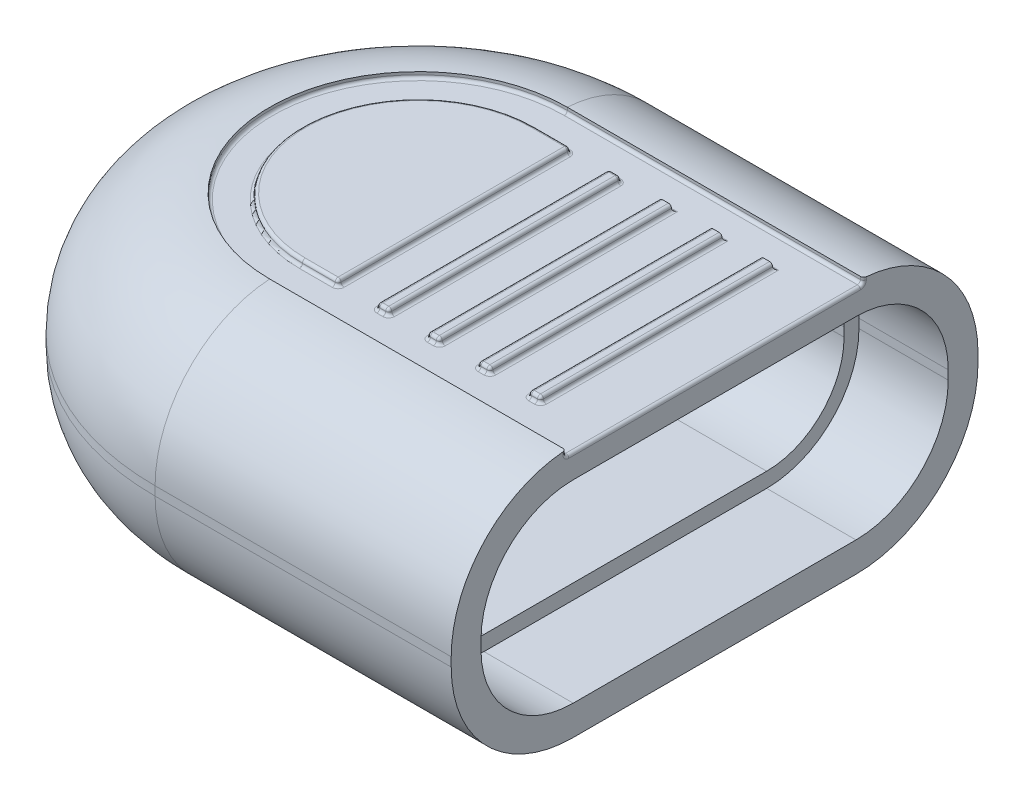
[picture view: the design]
ISO-10303-21;
HEADER;
FILE_DESCRIPTION(('STEP AP214'),'2;1');
FILE_NAME('part.step','',(''),(''),'','','');
FILE_SCHEMA(('AUTOMOTIVE_DESIGN { 1 0 10303 214 1 1 1 1 }'));
ENDSEC;
DATA;
#1=APPLICATION_CONTEXT('core data for automotive mechanical design processes');
#2=APPLICATION_PROTOCOL_DEFINITION('international standard','automotive_design',2000,#1);
#3=PRODUCT_CONTEXT('',#1,'mechanical');
#4=PRODUCT('Part','Part','',(#3));
#5=PRODUCT_RELATED_PRODUCT_CATEGORY('part','',(#4));
#6=PRODUCT_DEFINITION_FORMATION('','',#4);
#7=PRODUCT_DEFINITION_CONTEXT('part definition',#1,'design');
#8=PRODUCT_DEFINITION('design','',#6,#7);
#9=PRODUCT_DEFINITION_SHAPE('','',#8);
#10=(LENGTH_UNIT() NAMED_UNIT(*) SI_UNIT(.MILLI.,.METRE.));
#11=(NAMED_UNIT(*) PLANE_ANGLE_UNIT() SI_UNIT($,.RADIAN.));
#12=(NAMED_UNIT(*) SI_UNIT($,.STERADIAN.) SOLID_ANGLE_UNIT());
#13=UNCERTAINTY_MEASURE_WITH_UNIT(LENGTH_MEASURE(1.E-05),#10,'distance_accuracy_value','');
#14=(GEOMETRIC_REPRESENTATION_CONTEXT(3) GLOBAL_UNCERTAINTY_ASSIGNED_CONTEXT((#13)) GLOBAL_UNIT_ASSIGNED_CONTEXT((#10,
#11,#12)) REPRESENTATION_CONTEXT('',''));
#15=CARTESIAN_POINT('',(0.,0.,0.));
#16=DIRECTION('',(0.,0.,1.));
#17=DIRECTION('',(1.,0.,0.));
#18=AXIS2_PLACEMENT_3D('',#15,#16,#17);
#19=CARTESIAN_POINT('',(0.,4.25,0.));
#20=DIRECTION('',(0.,-1.,0.));
#21=DIRECTION('',(0.,0.,-1.));
#22=AXIS2_PLACEMENT_3D('',#19,#20,#21);
#23=CYLINDRICAL_SURFACE('',#22,7.35);
#24=DIRECTION('',(0.,-1.,0.));
#25=VECTOR('',#24,1.);
#26=CARTESIAN_POINT('',(-3.86781592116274,4.25,-6.25));
#27=LINE('',#26,#25);
#28=CARTESIAN_POINT('',(-3.86781592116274,-0.150000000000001,-6.25));
#29=VERTEX_POINT('',#28);
#30=CARTESIAN_POINT('',(-3.86781592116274,0.150000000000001,-6.25));
#31=VERTEX_POINT('',#30);
#32=EDGE_CURVE('E736',#29,#31,#27,.F.);
#33=ORIENTED_EDGE('',*,*,#32,.T.);
#34=CARTESIAN_POINT('',(0.,0.150000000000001,0.));
#35=DIRECTION('',(0.,-1.,0.));
#36=DIRECTION('',(0.,0.,-1.));
#37=AXIS2_PLACEMENT_3D('',#34,#35,#36);
#38=CIRCLE('',#37,7.35);
#39=CARTESIAN_POINT('',(-3.86781592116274,0.150000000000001,6.25));
#40=VERTEX_POINT('',#39);
#41=EDGE_CURVE('E931',#40,#31,#38,.T.);
#42=ORIENTED_EDGE('',*,*,#41,.F.);
#43=DIRECTION('',(0.,-1.,0.));
#44=VECTOR('',#43,1.);
#45=CARTESIAN_POINT('',(-3.86781592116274,4.25,6.25));
#46=LINE('',#45,#44);
#47=CARTESIAN_POINT('',(-3.86781592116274,-0.150000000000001,6.25));
#48=VERTEX_POINT('',#47);
#49=EDGE_CURVE('E756',#48,#40,#46,.F.);
#50=ORIENTED_EDGE('',*,*,#49,.F.);
#51=CARTESIAN_POINT('',(0.,-0.150000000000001,0.));
#52=DIRECTION('',(0.,-1.,0.));
#53=DIRECTION('',(0.,0.,-1.));
#54=AXIS2_PLACEMENT_3D('',#51,#52,#53);
#55=CIRCLE('',#54,7.35);
#56=EDGE_CURVE('E926',#29,#48,#55,.F.);
#57=ORIENTED_EDGE('',*,*,#56,.F.);
#58=EDGE_LOOP('',(#33,#42,#50,#57));
#59=FACE_BOUND('',#58,.T.);
#60=ADVANCED_FACE('F44',(#59),#23,.F.);
#61=CARTESIAN_POINT('',(9.95000000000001,4.25,-8.85));
#62=DIRECTION('',(1.,0.,0.));
#63=DIRECTION('',(0.,0.,-1.));
#64=AXIS2_PLACEMENT_3D('',#61,#62,#63);
#65=PLANE('',#64);
#66=CARTESIAN_POINT('',(9.95000000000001,0.150000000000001,-4.75));
#67=DIRECTION('',(1.,0.,0.));
#68=DIRECTION('',(0.,0.,-1.));
#69=AXIS2_PLACEMENT_3D('',#66,#67,#68);
#70=CIRCLE('',#69,4.1);
#71=CARTESIAN_POINT('',(9.95000000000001,0.150000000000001,-8.85));
#72=VERTEX_POINT('',#71);
#73=CARTESIAN_POINT('',(9.95000000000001,4.23503365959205,-5.1));
#74=VERTEX_POINT('',#73);
#75=EDGE_CURVE('E1022',#72,#74,#70,.T.);
#76=ORIENTED_EDGE('',*,*,#75,.T.);
#77=DIRECTION('',(0.,1.,0.));
#78=VECTOR('',#77,1.);
#79=CARTESIAN_POINT('',(9.95000000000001,4.25,-5.1));
#80=LINE('',#79,#78);
#81=CARTESIAN_POINT('',(9.95000000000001,4.15,-5.1));
#82=VERTEX_POINT('',#81);
#83=EDGE_CURVE('E1143',#74,#82,#80,.F.);
#84=ORIENTED_EDGE('',*,*,#83,.T.);
#85=CARTESIAN_POINT('',(9.95000000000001,4.15,-4.9));
#86=DIRECTION('',(1.,0.,0.));
#87=DIRECTION('',(0.,0.,-1.));
#88=AXIS2_PLACEMENT_3D('',#85,#86,#87);
#89=CIRCLE('',#88,0.2);
#90=CARTESIAN_POINT('',(9.95000000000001,3.95,-4.9));
#91=VERTEX_POINT('',#90);
#92=EDGE_CURVE('E1904',#91,#82,#89,.T.);
#93=ORIENTED_EDGE('',*,*,#92,.F.);
#94=DIRECTION('',(0.,0.,-1.));
#95=VECTOR('',#94,1.);
#96=CARTESIAN_POINT('',(9.95000000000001,3.95,-8.85));
#97=LINE('',#96,#95);
#98=CARTESIAN_POINT('',(9.95000000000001,3.95,4.9));
#99=VERTEX_POINT('',#98);
#100=EDGE_CURVE('E1908',#91,#99,#97,.F.);
#101=ORIENTED_EDGE('',*,*,#100,.T.);
#102=CARTESIAN_POINT('',(9.95000000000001,4.15,4.9));
#103=DIRECTION('',(1.,0.,0.));
#104=DIRECTION('',(0.,0.,-1.));
#105=AXIS2_PLACEMENT_3D('',#102,#103,#104);
#106=CIRCLE('',#105,0.2);
#107=CARTESIAN_POINT('',(9.95000000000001,4.15,5.1));
#108=VERTEX_POINT('',#107);
#109=EDGE_CURVE('E1086',#108,#99,#106,.T.);
#110=ORIENTED_EDGE('',*,*,#109,.F.);
#111=DIRECTION('',(0.,1.,0.));
#112=VECTOR('',#111,1.);
#113=CARTESIAN_POINT('',(9.95000000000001,4.24237095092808,5.1));
#114=LINE('',#113,#112);
#115=CARTESIAN_POINT('',(9.95000000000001,4.23503365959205,5.1));
#116=VERTEX_POINT('',#115);
#117=EDGE_CURVE('E1906',#108,#116,#114,.T.);
#118=ORIENTED_EDGE('',*,*,#117,.T.);
#119=CARTESIAN_POINT('',(9.95000000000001,0.150000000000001,4.75));
#120=DIRECTION('',(1.,0.,0.));
#121=DIRECTION('',(0.,0.,-1.));
#122=AXIS2_PLACEMENT_3D('',#119,#120,#121);
#123=CIRCLE('',#122,4.1);
#124=CARTESIAN_POINT('',(9.95000000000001,0.150000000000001,8.85));
#125=VERTEX_POINT('',#124);
#126=EDGE_CURVE('E1019',#116,#125,#123,.T.);
#127=ORIENTED_EDGE('',*,*,#126,.T.);
#128=DIRECTION('',(0.,-1.,0.));
#129=VECTOR('',#128,1.);
#130=CARTESIAN_POINT('',(9.95000000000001,4.25,8.85));
#131=LINE('',#130,#129);
#132=CARTESIAN_POINT('',(9.95000000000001,-0.150000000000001,8.85));
#133=VERTEX_POINT('',#132);
#134=EDGE_CURVE('E998',#125,#133,#131,.T.);
#135=ORIENTED_EDGE('',*,*,#134,.T.);
#136=CARTESIAN_POINT('',(9.95000000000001,-0.150000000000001,4.75));
#137=DIRECTION('',(1.,0.,0.));
#138=DIRECTION('',(0.,0.,-1.));
#139=AXIS2_PLACEMENT_3D('',#136,#137,#138);
#140=CIRCLE('',#139,4.1);
#141=CARTESIAN_POINT('',(9.95000000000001,-4.25,4.75));
#142=VERTEX_POINT('',#141);
#143=EDGE_CURVE('E1016',#133,#142,#140,.T.);
#144=ORIENTED_EDGE('',*,*,#143,.T.);
#145=DIRECTION('',(0.,0.,1.));
#146=VECTOR('',#145,1.);
#147=CARTESIAN_POINT('',(9.95000000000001,-4.25,-8.85));
#148=LINE('',#147,#146);
#149=CARTESIAN_POINT('',(9.95000000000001,-4.25,-4.75));
#150=VERTEX_POINT('',#149);
#151=EDGE_CURVE('E985',#150,#142,#148,.T.);
#152=ORIENTED_EDGE('',*,*,#151,.F.);
#153=CARTESIAN_POINT('',(9.95000000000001,-0.150000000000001,-4.75));
#154=DIRECTION('',(1.,0.,0.));
#155=DIRECTION('',(0.,0.,-1.));
#156=AXIS2_PLACEMENT_3D('',#153,#154,#155);
#157=CIRCLE('',#156,4.1);
#158=CARTESIAN_POINT('',(9.95000000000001,-0.150000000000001,-8.85));
#159=VERTEX_POINT('',#158);
#160=EDGE_CURVE('E1026',#150,#159,#157,.T.);
#161=ORIENTED_EDGE('',*,*,#160,.T.);
#162=DIRECTION('',(0.,-1.,0.));
#163=VECTOR('',#162,1.);
#164=CARTESIAN_POINT('',(9.95000000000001,4.25,-8.85));
#165=LINE('',#164,#163);
#166=EDGE_CURVE('E994',#72,#159,#165,.T.);
#167=ORIENTED_EDGE('',*,*,#166,.F.);
#168=EDGE_LOOP('',(#76,#84,#93,#101,#110,#118,#127,#135,#144,#152,#161,#167));
#169=FACE_BOUND('',#168,.T.);
#170=CARTESIAN_POINT('',(9.95000000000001,0.150000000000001,-4.75));
#171=DIRECTION('',(1.,0.,0.));
#172=DIRECTION('',(0.,0.,-1.));
#173=AXIS2_PLACEMENT_3D('',#170,#171,#172);
#174=CIRCLE('',#173,3.1);
#175=CARTESIAN_POINT('',(9.95000000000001,0.150000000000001,-7.85));
#176=VERTEX_POINT('',#175);
#177=CARTESIAN_POINT('',(9.95000000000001,3.25,-4.75));
#178=VERTEX_POINT('',#177);
#179=EDGE_CURVE('E822',#176,#178,#174,.T.);
#180=ORIENTED_EDGE('',*,*,#179,.F.);
#181=DIRECTION('',(0.,-1.,0.));
#182=VECTOR('',#181,1.);
#183=CARTESIAN_POINT('',(9.95000000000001,0.,-7.85));
#184=LINE('',#183,#182);
#185=CARTESIAN_POINT('',(9.95000000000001,-0.150000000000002,-7.85));
#186=VERTEX_POINT('',#185);
#187=EDGE_CURVE('E759',#176,#186,#184,.T.);
#188=ORIENTED_EDGE('',*,*,#187,.T.);
#189=CARTESIAN_POINT('',(9.95000000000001,-0.150000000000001,-4.75));
#190=DIRECTION('',(1.,0.,0.));
#191=DIRECTION('',(0.,0.,-1.));
#192=AXIS2_PLACEMENT_3D('',#189,#190,#191);
#193=CIRCLE('',#192,3.1);
#194=CARTESIAN_POINT('',(9.95000000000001,-3.25,-4.75));
#195=VERTEX_POINT('',#194);
#196=EDGE_CURVE('E791',#195,#186,#193,.T.);
#197=ORIENTED_EDGE('',*,*,#196,.F.);
#198=DIRECTION('',(0.,0.,1.));
#199=VECTOR('',#198,1.);
#200=CARTESIAN_POINT('',(9.95000000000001,-3.25,0.));
#201=LINE('',#200,#199);
#202=CARTESIAN_POINT('',(9.95000000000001,-3.25,4.75));
#203=VERTEX_POINT('',#202);
#204=EDGE_CURVE('E842',#195,#203,#201,.T.);
#205=ORIENTED_EDGE('',*,*,#204,.T.);
#206=CARTESIAN_POINT('',(9.95000000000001,-0.150000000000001,4.75));
#207=DIRECTION('',(1.,0.,0.));
#208=DIRECTION('',(0.,0.,-1.));
#209=AXIS2_PLACEMENT_3D('',#206,#207,#208);
#210=CIRCLE('',#209,3.1);
#211=CARTESIAN_POINT('',(9.95000000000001,-0.150000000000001,7.85));
#212=VERTEX_POINT('',#211);
#213=EDGE_CURVE('E838',#212,#203,#210,.T.);
#214=ORIENTED_EDGE('',*,*,#213,.F.);
#215=DIRECTION('',(0.,-1.,0.));
#216=VECTOR('',#215,1.);
#217=CARTESIAN_POINT('',(9.95000000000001,0.,7.85));
#218=LINE('',#217,#216);
#219=CARTESIAN_POINT('',(9.95000000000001,0.150000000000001,7.85));
#220=VERTEX_POINT('',#219);
#221=EDGE_CURVE('E834',#220,#212,#218,.T.);
#222=ORIENTED_EDGE('',*,*,#221,.F.);
#223=CARTESIAN_POINT('',(9.95000000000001,0.150000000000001,4.75));
#224=DIRECTION('',(1.,0.,0.));
#225=DIRECTION('',(0.,0.,-1.));
#226=AXIS2_PLACEMENT_3D('',#223,#224,#225);
#227=CIRCLE('',#226,3.1);
#228=CARTESIAN_POINT('',(9.95000000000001,3.25,4.75));
#229=VERTEX_POINT('',#228);
#230=EDGE_CURVE('E830',#229,#220,#227,.T.);
#231=ORIENTED_EDGE('',*,*,#230,.F.);
#232=DIRECTION('',(0.,0.,1.));
#233=VECTOR('',#232,1.);
#234=CARTESIAN_POINT('',(9.95000000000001,3.25,0.));
#235=LINE('',#234,#233);
#236=EDGE_CURVE('E826',#178,#229,#235,.T.);
#237=ORIENTED_EDGE('',*,*,#236,.F.);
#238=EDGE_LOOP('',(#180,#188,#197,#205,#214,#222,#231,#237));
#239=FACE_BOUND('',#238,.T.);
#240=ADVANCED_FACE('F1793',(#169,#239),#65,.T.);
#241=CARTESIAN_POINT('',(0.,0.150000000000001,-4.75));
#242=DIRECTION('',(1.,0.,0.));
#243=DIRECTION('',(0.,0.,-1.));
#244=AXIS2_PLACEMENT_3D('',#241,#242,#243);
#245=CYLINDRICAL_SURFACE('',#244,4.1);
#246=DIRECTION('',(1.,0.,0.));
#247=VECTOR('',#246,1.);
#248=CARTESIAN_POINT('',(0.,4.24237095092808,-5.));
#249=LINE('',#248,#247);
#250=CARTESIAN_POINT('',(0.,4.24237095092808,-5.));
#251=VERTEX_POINT('',#250);
#252=CARTESIAN_POINT('',(9.85000000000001,4.24237095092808,-5.));
#253=VERTEX_POINT('',#252);
#254=EDGE_CURVE('E1048',#251,#253,#249,.T.);
#255=ORIENTED_EDGE('',*,*,#254,.T.);
#256=CARTESIAN_POINT('',(9.85000000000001,4.24237095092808,-5.));
#257=CARTESIAN_POINT('',(9.85561729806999,4.24237091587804,-4.99999518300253));
#258=CARTESIAN_POINT('',(9.8612331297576,4.24234204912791,-5.00047302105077));
#259=CARTESIAN_POINT('',(9.87230133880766,4.24222639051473,-5.00235842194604));
#260=CARTESIAN_POINT('',(9.87775384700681,4.2421396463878,-5.00376521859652));
#261=CARTESIAN_POINT('',(9.88834713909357,4.24190791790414,-5.00747392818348));
#262=CARTESIAN_POINT('',(9.89348777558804,4.24176290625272,-5.0097762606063));
#263=CARTESIAN_POINT('',(9.90330831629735,4.24141444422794,-5.01520797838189));
#264=CARTESIAN_POINT('',(9.90798829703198,4.24121100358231,-5.01833722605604));
#265=CARTESIAN_POINT('',(9.91675889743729,4.24074595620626,-5.02533575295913));
#266=CARTESIAN_POINT('',(9.9208491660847,4.24048431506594,-5.02920546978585));
#267=CARTESIAN_POINT('',(9.92832272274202,4.23990450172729,-5.0375738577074));
#268=CARTESIAN_POINT('',(9.93170587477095,4.23958631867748,-5.04207264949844));
#269=CARTESIAN_POINT('',(9.93767549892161,4.2388962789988,-5.05157909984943));
#270=CARTESIAN_POINT('',(9.9402603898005,4.23852431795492,-5.05658774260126));
#271=CARTESIAN_POINT('',(9.94455186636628,4.23773301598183,-5.06696338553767));
#272=CARTESIAN_POINT('',(9.94625891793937,4.23731370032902,-5.07233019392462));
#273=CARTESIAN_POINT('',(9.9483337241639,4.23658301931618,-5.08144020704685));
#274=CARTESIAN_POINT('',(9.94895828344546,4.23628229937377,-5.08512786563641));
#275=CARTESIAN_POINT('',(9.94979137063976,4.23566739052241,-5.09254334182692));
#276=CARTESIAN_POINT('',(9.95000049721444,4.23535322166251,-5.09627109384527));
#277=CARTESIAN_POINT('',(9.95000000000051,4.23503365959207,-5.09999999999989));
#278=B_SPLINE_CURVE_WITH_KNOTS('',3,(#256,#257,#258,#259,#260,#261,#262,#263,#264,#265,#266,
#267,#268,#269,#270,#271,#272,#273,#274,#275,#276,#277),.UNSPECIFIED.,.F.,.F.,(4,2,2,2,2,2,2,2,
2,2,4),(0.,0.0168294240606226,0.033644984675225,0.0504684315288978,0.0672890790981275,
0.0841196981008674,0.100953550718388,0.117820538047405,0.134678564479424,0.145913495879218,
0.157132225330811),.UNSPECIFIED.);
#279=EDGE_CURVE('E1077',#253,#74,#278,.T.);
#280=ORIENTED_EDGE('',*,*,#279,.T.);
#281=ORIENTED_EDGE('',*,*,#75,.F.);
#282=DIRECTION('',(1.,0.,0.));
#283=VECTOR('',#282,1.);
#284=CARTESIAN_POINT('',(0.,0.150000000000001,-8.85));
#285=LINE('',#284,#283);
#286=CARTESIAN_POINT('',(0.,0.150000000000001,-8.85));
#287=VERTEX_POINT('',#286);
#288=EDGE_CURVE('E1029',#287,#72,#285,.T.);
#289=ORIENTED_EDGE('',*,*,#288,.F.);
#290=CARTESIAN_POINT('',(0.,0.150000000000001,-4.75));
#291=DIRECTION('',(1.,0.,0.));
#292=DIRECTION('',(0.,0.,-1.));
#293=AXIS2_PLACEMENT_3D('',#290,#291,#292);
#294=CIRCLE('',#293,4.1);
#295=EDGE_CURVE('E936',#287,#251,#294,.T.);
#296=ORIENTED_EDGE('',*,*,#295,.T.);
#297=EDGE_LOOP('',(#255,#280,#281,#289,#296));
#298=FACE_BOUND('',#297,.T.);
#299=ADVANCED_FACE('F1088',(#298),#245,.T.);
#300=CARTESIAN_POINT('',(0.,4.25,0.));
#301=DIRECTION('',(0.,-1.,0.));
#302=DIRECTION('',(0.,0.,-1.));
#303=AXIS2_PLACEMENT_3D('',#300,#301,#302);
#304=CYLINDRICAL_SURFACE('',#303,8.85);
#305=DIRECTION('',(0.,-1.,0.));
#306=VECTOR('',#305,1.);
#307=CARTESIAN_POINT('',(0.,4.25,-8.85));
#308=LINE('',#307,#306);
#309=CARTESIAN_POINT('',(0.,-0.150000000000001,-8.85));
#310=VERTEX_POINT('',#309);
#311=EDGE_CURVE('E989',#287,#310,#308,.T.);
#312=ORIENTED_EDGE('',*,*,#311,.T.);
#313=CARTESIAN_POINT('',(0.,-0.150000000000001,0.));
#314=DIRECTION('',(0.,1.,0.));
#315=DIRECTION('',(0.,0.,1.));
#316=AXIS2_PLACEMENT_3D('',#313,#314,#315);
#317=CIRCLE('',#316,8.85);
#318=CARTESIAN_POINT('',(0.,-0.150000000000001,8.85));
#319=VERTEX_POINT('',#318);
#320=EDGE_CURVE('E1039',#310,#319,#317,.T.);
#321=ORIENTED_EDGE('',*,*,#320,.T.);
#322=DIRECTION('',(0.,-1.,0.));
#323=VECTOR('',#322,1.);
#324=CARTESIAN_POINT('',(0.,4.25,8.85));
#325=LINE('',#324,#323);
#326=CARTESIAN_POINT('',(0.,0.150000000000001,8.85));
#327=VERTEX_POINT('',#326);
#328=EDGE_CURVE('E1002',#327,#319,#325,.T.);
#329=ORIENTED_EDGE('',*,*,#328,.F.);
#330=CARTESIAN_POINT('',(0.,0.150000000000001,0.));
#331=DIRECTION('',(0.,1.,0.));
#332=DIRECTION('',(0.,0.,1.));
#333=AXIS2_PLACEMENT_3D('',#330,#331,#332);
#334=CIRCLE('',#333,8.85);
#335=EDGE_CURVE('E1036',#327,#287,#334,.F.);
#336=ORIENTED_EDGE('',*,*,#335,.T.);
#337=EDGE_LOOP('',(#312,#321,#329,#336));
#338=FACE_BOUND('',#337,.T.);
#339=ADVANCED_FACE('F1867',(#338),#304,.T.);
#340=CARTESIAN_POINT('',(9.95000000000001,4.25,8.85));
#341=DIRECTION('',(0.,0.,1.));
#342=DIRECTION('',(1.,0.,0.));
#343=AXIS2_PLACEMENT_3D('',#340,#341,#342);
#344=PLANE('',#343);
#345=ORIENTED_EDGE('',*,*,#134,.F.);
#346=DIRECTION('',(-1.,0.,0.));
#347=VECTOR('',#346,1.);
#348=CARTESIAN_POINT('',(9.95000000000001,0.150000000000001,8.85));
#349=LINE('',#348,#347);
#350=EDGE_CURVE('E1045',#125,#327,#349,.T.);
#351=ORIENTED_EDGE('',*,*,#350,.T.);
#352=ORIENTED_EDGE('',*,*,#328,.T.);
#353=DIRECTION('',(-1.,0.,0.));
#354=VECTOR('',#353,1.);
#355=CARTESIAN_POINT('',(9.95000000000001,-0.150000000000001,8.85));
#356=LINE('',#355,#354);
#357=EDGE_CURVE('E1042',#319,#133,#356,.F.);
#358=ORIENTED_EDGE('',*,*,#357,.T.);
#359=EDGE_LOOP('',(#345,#351,#352,#358));
#360=FACE_BOUND('',#359,.T.);
#361=ADVANCED_FACE('F1862',(#360),#344,.T.);
#362=CARTESIAN_POINT('',(0.,4.25,-8.85));
#363=DIRECTION('',(0.,0.,-1.));
#364=DIRECTION('',(-1.,0.,0.));
#365=AXIS2_PLACEMENT_3D('',#362,#363,#364);
#366=PLANE('',#365);
#367=ORIENTED_EDGE('',*,*,#166,.T.);
#368=DIRECTION('',(1.,0.,0.));
#369=VECTOR('',#368,1.);
#370=CARTESIAN_POINT('',(0.,-0.150000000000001,-8.85));
#371=LINE('',#370,#369);
#372=EDGE_CURVE('E1033',#159,#310,#371,.F.);
#373=ORIENTED_EDGE('',*,*,#372,.T.);
#374=ORIENTED_EDGE('',*,*,#311,.F.);
#375=ORIENTED_EDGE('',*,*,#288,.T.);
#376=EDGE_LOOP('',(#367,#373,#374,#375));
#377=FACE_BOUND('',#376,.T.);
#378=ADVANCED_FACE('F1859',(#377),#366,.T.);
#379=CARTESIAN_POINT('',(0.,-4.25,0.));
#380=DIRECTION('',(0.,1.,0.));
#381=DIRECTION('',(0.,0.,1.));
#382=AXIS2_PLACEMENT_3D('',#379,#380,#381);
#383=PLANE('',#382);
#384=CARTESIAN_POINT('',(0.,-4.25,0.));
#385=DIRECTION('',(0.,1.,0.));
#386=DIRECTION('',(0.,0.,1.));
#387=AXIS2_PLACEMENT_3D('',#384,#385,#386);
#388=CIRCLE('',#387,4.75);
#389=CARTESIAN_POINT('',(0.,-4.25,4.75));
#390=VERTEX_POINT('',#389);
#391=CARTESIAN_POINT('',(0.,-4.25,-4.75));
#392=VERTEX_POINT('',#391);
#393=EDGE_CURVE('E1009',#390,#392,#388,.F.);
#394=ORIENTED_EDGE('',*,*,#393,.T.);
#395=DIRECTION('',(1.,0.,0.));
#396=VECTOR('',#395,1.);
#397=CARTESIAN_POINT('',(9.95000000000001,-4.25,-4.75));
#398=LINE('',#397,#396);
#399=EDGE_CURVE('E1012',#392,#150,#398,.T.);
#400=ORIENTED_EDGE('',*,*,#399,.T.);
#401=ORIENTED_EDGE('',*,*,#151,.T.);
#402=DIRECTION('',(-1.,0.,0.));
#403=VECTOR('',#402,1.);
#404=CARTESIAN_POINT('',(0.,-4.25,4.75));
#405=LINE('',#404,#403);
#406=EDGE_CURVE('E1006',#142,#390,#405,.T.);
#407=ORIENTED_EDGE('',*,*,#406,.T.);
#408=EDGE_LOOP('',(#394,#400,#401,#407));
#409=FACE_BOUND('',#408,.T.);
#410=ADVANCED_FACE('F1855',(#409),#383,.F.);
#411=CARTESIAN_POINT('',(0.,-0.150000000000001,4.75));
#412=DIRECTION('',(1.,0.,0.));
#413=DIRECTION('',(0.,0.,-1.));
#414=AXIS2_PLACEMENT_3D('',#411,#412,#413);
#415=CYLINDRICAL_SURFACE('',#414,4.1);
#416=ORIENTED_EDGE('',*,*,#143,.F.);
#417=ORIENTED_EDGE('',*,*,#357,.F.);
#418=CARTESIAN_POINT('',(0.,-0.150000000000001,4.75));
#419=DIRECTION('',(-1.,0.,0.));
#420=DIRECTION('',(0.,0.,1.));
#421=AXIS2_PLACEMENT_3D('',#418,#419,#420);
#422=CIRCLE('',#421,4.1);
#423=EDGE_CURVE('E990',#390,#319,#422,.T.);
#424=ORIENTED_EDGE('',*,*,#423,.F.);
#425=ORIENTED_EDGE('',*,*,#406,.F.);
#426=EDGE_LOOP('',(#416,#417,#424,#425));
#427=FACE_BOUND('',#426,.T.);
#428=ADVANCED_FACE('F1858',(#427),#415,.T.);
#429=CARTESIAN_POINT('',(0.,-0.150000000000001,0.));
#430=DIRECTION('',(0.,1.,0.));
#431=DIRECTION('',(0.,0.,1.));
#432=AXIS2_PLACEMENT_3D('',#429,#430,#431);
#433=TOROIDAL_SURFACE('',#432,4.75,4.1);
#434=ORIENTED_EDGE('',*,*,#423,.T.);
#435=ORIENTED_EDGE('',*,*,#320,.F.);
#436=CARTESIAN_POINT('',(0.,-0.150000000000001,-4.75));
#437=DIRECTION('',(1.,0.,0.));
#438=DIRECTION('',(0.,0.,-1.));
#439=AXIS2_PLACEMENT_3D('',#436,#437,#438);
#440=CIRCLE('',#439,4.1);
#441=EDGE_CURVE('E1049',#392,#310,#440,.T.);
#442=ORIENTED_EDGE('',*,*,#441,.F.);
#443=ORIENTED_EDGE('',*,*,#393,.F.);
#444=EDGE_LOOP('',(#434,#435,#442,#443));
#445=FACE_BOUND('',#444,.T.);
#446=ADVANCED_FACE('F1875',(#445),#433,.T.);
#447=CARTESIAN_POINT('',(0.,-0.150000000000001,-4.75));
#448=DIRECTION('',(-1.,0.,0.));
#449=DIRECTION('',(0.,0.,1.));
#450=AXIS2_PLACEMENT_3D('',#447,#448,#449);
#451=CYLINDRICAL_SURFACE('',#450,4.1);
#452=ORIENTED_EDGE('',*,*,#441,.T.);
#453=ORIENTED_EDGE('',*,*,#372,.F.);
#454=ORIENTED_EDGE('',*,*,#160,.F.);
#455=ORIENTED_EDGE('',*,*,#399,.F.);
#456=EDGE_LOOP('',(#452,#453,#454,#455));
#457=FACE_BOUND('',#456,.T.);
#458=ADVANCED_FACE('F1872',(#457),#451,.T.);
#459=CARTESIAN_POINT('',(9.95000000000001,0.150000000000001,4.75));
#460=DIRECTION('',(-1.,0.,0.));
#461=DIRECTION('',(0.,0.,1.));
#462=AXIS2_PLACEMENT_3D('',#459,#460,#461);
#463=CYLINDRICAL_SURFACE('',#462,4.1);
#464=ORIENTED_EDGE('',*,*,#126,.F.);
#465=CARTESIAN_POINT('',(9.95000000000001,4.23503365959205,5.1));
#466=CARTESIAN_POINT('',(9.95000475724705,4.23551667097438,5.09436780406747));
#467=CARTESIAN_POINT('',(9.94952444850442,4.23598704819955,5.08873569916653));
#468=CARTESIAN_POINT('',(9.94762747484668,4.23689211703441,5.07763218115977));
#469=CARTESIAN_POINT('',(9.94621142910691,4.23732683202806,5.07216066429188));
#470=CARTESIAN_POINT('',(9.94247564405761,4.23815105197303,5.06152803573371));
#471=CARTESIAN_POINT('',(9.9401554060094,4.23854053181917,5.05636709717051));
#472=CARTESIAN_POINT('',(9.93467797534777,4.2392673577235,5.04650778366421));
#473=CARTESIAN_POINT('',(9.93152096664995,4.23960471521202,5.04180930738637));
#474=CARTESIAN_POINT('',(9.92446615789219,4.24022246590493,5.03301874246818));
#475=CARTESIAN_POINT('',(9.92056999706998,4.24050298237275,5.02892534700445));
#476=CARTESIAN_POINT('',(9.91214167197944,4.24100587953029,5.02144974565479));
#477=CARTESIAN_POINT('',(9.90760938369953,4.24122824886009,5.01806767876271));
#478=CARTESIAN_POINT('',(9.89805027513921,4.24161358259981,5.01212055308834));
#479=CARTESIAN_POINT('',(9.89302463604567,4.24177668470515,5.00955360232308));
#480=CARTESIAN_POINT('',(9.8826134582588,4.24204423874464,5.00530083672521));
#481=CARTESIAN_POINT('',(9.87722814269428,4.24214872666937,5.00361448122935));
#482=CARTESIAN_POINT('',(9.86817396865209,4.24227314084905,5.00159723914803));
#483=CARTESIAN_POINT('',(9.86456272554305,4.24230985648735,5.00099863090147));
#484=CARTESIAN_POINT('',(9.85730149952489,4.24235872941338,5.00020007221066));
#485=CARTESIAN_POINT('',(9.85365157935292,4.24237092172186,4.99999955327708));
#486=CARTESIAN_POINT('',(9.85000000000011,4.24237095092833,4.99999999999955));
#487=B_SPLINE_CURVE_WITH_KNOTS('',3,(#465,#466,#467,#468,#469,#470,#471,#472,#473,#474,#475,
#476,#477,#478,#479,#480,#481,#482,#483,#484,#485,#486),.UNSPECIFIED.,.F.,.F.,(4,2,2,2,2,2,2,2,
2,2,4),(0.,0.0169365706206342,0.0338619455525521,0.0507966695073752,0.0677276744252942,
0.0846215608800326,0.101518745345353,0.118376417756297,0.135223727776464,0.14618537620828,
0.157131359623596),.UNSPECIFIED.);
#488=CARTESIAN_POINT('',(9.85000000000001,4.24237095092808,5.));
#489=VERTEX_POINT('',#488);
#490=EDGE_CURVE('E1134',#116,#489,#487,.T.);
#491=ORIENTED_EDGE('',*,*,#490,.T.);
#492=DIRECTION('',(-1.,0.,0.));
#493=VECTOR('',#492,1.);
#494=CARTESIAN_POINT('',(9.95000000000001,4.24237095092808,5.));
#495=LINE('',#494,#493);
#496=CARTESIAN_POINT('',(0.,4.24237095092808,5.));
#497=VERTEX_POINT('',#496);
#498=EDGE_CURVE('E914',#497,#489,#495,.F.);
#499=ORIENTED_EDGE('',*,*,#498,.F.);
#500=CARTESIAN_POINT('',(0.,0.150000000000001,4.75));
#501=DIRECTION('',(-1.,0.,0.));
#502=DIRECTION('',(0.,0.,1.));
#503=AXIS2_PLACEMENT_3D('',#500,#501,#502);
#504=CIRCLE('',#503,4.1);
#505=EDGE_CURVE('E1053',#327,#497,#504,.T.);
#506=ORIENTED_EDGE('',*,*,#505,.F.);
#507=ORIENTED_EDGE('',*,*,#350,.F.);
#508=EDGE_LOOP('',(#464,#491,#499,#506,#507));
#509=FACE_BOUND('',#508,.T.);
#510=ADVANCED_FACE('F1100',(#509),#463,.T.);
#511=CARTESIAN_POINT('',(0.,0.150000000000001,0.));
#512=DIRECTION('',(0.,1.,0.));
#513=DIRECTION('',(0.,0.,1.));
#514=AXIS2_PLACEMENT_3D('',#511,#512,#513);
#515=TOROIDAL_SURFACE('',#514,4.75,4.1);
#516=CARTESIAN_POINT('',(0.,4.24237095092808,0.));
#517=DIRECTION('',(0.,-1.,0.));
#518=DIRECTION('',(0.,0.,-1.));
#519=AXIS2_PLACEMENT_3D('',#516,#517,#518);
#520=CIRCLE('',#519,5.);
#521=EDGE_CURVE('E1066',#251,#497,#520,.F.);
#522=ORIENTED_EDGE('',*,*,#521,.F.);
#523=ORIENTED_EDGE('',*,*,#295,.F.);
#524=ORIENTED_EDGE('',*,*,#335,.F.);
#525=ORIENTED_EDGE('',*,*,#505,.T.);
#526=EDGE_LOOP('',(#522,#523,#524,#525));
#527=FACE_BOUND('',#526,.T.);
#528=ADVANCED_FACE('F1944',(#527),#515,.T.);
#529=CARTESIAN_POINT('',(0.,4.05,-3.9));
#530=DIRECTION('',(0.,0.,1.));
#531=DIRECTION('',(1.,0.,0.));
#532=AXIS2_PLACEMENT_3D('',#529,#530,#531);
#533=PLANE('',#532);
#534=DIRECTION('',(1.,0.,0.));
#535=VECTOR('',#534,1.);
#536=CARTESIAN_POINT('',(0.,4.15,-3.9));
#537=LINE('',#536,#535);
#538=CARTESIAN_POINT('',(8.,4.15,-3.9));
#539=VERTEX_POINT('',#538);
#540=CARTESIAN_POINT('',(7.6,4.15,-3.9));
#541=VERTEX_POINT('',#540);
#542=EDGE_CURVE('E1288',#539,#541,#537,.F.);
#543=ORIENTED_EDGE('',*,*,#542,.T.);
#544=CARTESIAN_POINT('',(7.7,4.15,-3.9));
#545=DIRECTION('',(0.,0.,1.));
#546=DIRECTION('',(1.,0.,0.));
#547=AXIS2_PLACEMENT_3D('',#544,#545,#546);
#548=CIRCLE('',#547,0.1);
#549=CARTESIAN_POINT('',(7.7,4.25,-3.9));
#550=VERTEX_POINT('',#549);
#551=EDGE_CURVE('E1562',#541,#550,#548,.F.);
#552=ORIENTED_EDGE('',*,*,#551,.T.);
#553=DIRECTION('',(1.,0.,0.));
#554=VECTOR('',#553,1.);
#555=CARTESIAN_POINT('',(0.,4.25,-3.9));
#556=LINE('',#555,#554);
#557=CARTESIAN_POINT('',(7.9,4.25,-3.9));
#558=VERTEX_POINT('',#557);
#559=EDGE_CURVE('E906',#550,#558,#556,.T.);
#560=ORIENTED_EDGE('',*,*,#559,.T.);
#561=CARTESIAN_POINT('',(7.9,4.15,-3.9));
#562=DIRECTION('',(0.,0.,1.));
#563=DIRECTION('',(1.,0.,0.));
#564=AXIS2_PLACEMENT_3D('',#561,#562,#563);
#565=CIRCLE('',#564,0.1);
#566=EDGE_CURVE('E1559',#558,#539,#565,.F.);
#567=ORIENTED_EDGE('',*,*,#566,.T.);
#568=EDGE_LOOP('',(#543,#552,#560,#567));
#569=FACE_BOUND('',#568,.T.);
#570=ADVANCED_FACE('F1963',(#569),#533,.F.);
#571=CARTESIAN_POINT('',(0.,4.05,-3.9));
#572=DIRECTION('',(0.,0.,1.));
#573=DIRECTION('',(1.,0.,0.));
#574=AXIS2_PLACEMENT_3D('',#571,#572,#573);
#575=PLANE('',#574);
#576=DIRECTION('',(1.,0.,0.));
#577=VECTOR('',#576,1.);
#578=CARTESIAN_POINT('',(0.,4.15,-3.9));
#579=LINE('',#578,#577);
#580=CARTESIAN_POINT('',(6.3,4.15,-3.9));
#581=VERTEX_POINT('',#580);
#582=CARTESIAN_POINT('',(5.9,4.15,-3.9));
#583=VERTEX_POINT('',#582);
#584=EDGE_CURVE('E1303',#581,#583,#579,.F.);
#585=ORIENTED_EDGE('',*,*,#584,.T.);
#586=CARTESIAN_POINT('',(6.,4.15,-3.9));
#587=DIRECTION('',(0.,0.,1.));
#588=DIRECTION('',(1.,0.,0.));
#589=AXIS2_PLACEMENT_3D('',#586,#587,#588);
#590=CIRCLE('',#589,0.1);
#591=CARTESIAN_POINT('',(6.,4.25,-3.9));
#592=VERTEX_POINT('',#591);
#593=EDGE_CURVE('E1578',#583,#592,#590,.F.);
#594=ORIENTED_EDGE('',*,*,#593,.T.);
#595=DIRECTION('',(1.,0.,0.));
#596=VECTOR('',#595,1.);
#597=CARTESIAN_POINT('',(0.,4.25,-3.9));
#598=LINE('',#597,#596);
#599=CARTESIAN_POINT('',(6.2,4.25,-3.9));
#600=VERTEX_POINT('',#599);
#601=EDGE_CURVE('E901',#592,#600,#598,.T.);
#602=ORIENTED_EDGE('',*,*,#601,.T.);
#603=CARTESIAN_POINT('',(6.2,4.15,-3.9));
#604=DIRECTION('',(0.,0.,1.));
#605=DIRECTION('',(1.,0.,0.));
#606=AXIS2_PLACEMENT_3D('',#603,#604,#605);
#607=CIRCLE('',#606,0.1);
#608=EDGE_CURVE('E1575',#600,#581,#607,.F.);
#609=ORIENTED_EDGE('',*,*,#608,.T.);
#610=EDGE_LOOP('',(#585,#594,#602,#609));
#611=FACE_BOUND('',#610,.T.);
#612=ADVANCED_FACE('F1957',(#611),#575,.F.);
#613=CARTESIAN_POINT('',(0.,4.05,-3.9));
#614=DIRECTION('',(0.,0.,1.));
#615=DIRECTION('',(1.,0.,0.));
#616=AXIS2_PLACEMENT_3D('',#613,#614,#615);
#617=PLANE('',#616);
#618=DIRECTION('',(1.,0.,0.));
#619=VECTOR('',#618,1.);
#620=CARTESIAN_POINT('',(0.,4.15,-3.9));
#621=LINE('',#620,#619);
#622=CARTESIAN_POINT('',(4.6,4.15,-3.9));
#623=VERTEX_POINT('',#622);
#624=CARTESIAN_POINT('',(4.2,4.15,-3.9));
#625=VERTEX_POINT('',#624);
#626=EDGE_CURVE('E1318',#623,#625,#621,.F.);
#627=ORIENTED_EDGE('',*,*,#626,.T.);
#628=CARTESIAN_POINT('',(4.3,4.15,-3.9));
#629=DIRECTION('',(0.,0.,1.));
#630=DIRECTION('',(1.,0.,0.));
#631=AXIS2_PLACEMENT_3D('',#628,#629,#630);
#632=CIRCLE('',#631,0.1);
#633=CARTESIAN_POINT('',(4.3,4.25,-3.9));
#634=VERTEX_POINT('',#633);
#635=EDGE_CURVE('E1594',#625,#634,#632,.F.);
#636=ORIENTED_EDGE('',*,*,#635,.T.);
#637=DIRECTION('',(1.,0.,0.));
#638=VECTOR('',#637,1.);
#639=CARTESIAN_POINT('',(0.,4.25,-3.9));
#640=LINE('',#639,#638);
#641=CARTESIAN_POINT('',(4.5,4.25,-3.9));
#642=VERTEX_POINT('',#641);
#643=EDGE_CURVE('E897',#634,#642,#640,.T.);
#644=ORIENTED_EDGE('',*,*,#643,.T.);
#645=CARTESIAN_POINT('',(4.5,4.15,-3.9));
#646=DIRECTION('',(0.,0.,1.));
#647=DIRECTION('',(1.,0.,0.));
#648=AXIS2_PLACEMENT_3D('',#645,#646,#647);
#649=CIRCLE('',#648,0.1);
#650=EDGE_CURVE('E1591',#642,#623,#649,.F.);
#651=ORIENTED_EDGE('',*,*,#650,.T.);
#652=EDGE_LOOP('',(#627,#636,#644,#651));
#653=FACE_BOUND('',#652,.T.);
#654=ADVANCED_FACE('F1950',(#653),#617,.F.);
#655=CARTESIAN_POINT('',(0.,4.05,5.));
#656=DIRECTION('',(0.,0.,1.));
#657=DIRECTION('',(1.,0.,0.));
#658=AXIS2_PLACEMENT_3D('',#655,#656,#657);
#659=PLANE('',#658);
#660=ORIENTED_EDGE('',*,*,#498,.T.);
#661=DIRECTION('',(0.,1.,0.));
#662=VECTOR('',#661,1.);
#663=CARTESIAN_POINT('',(9.85000000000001,4.05,5.));
#664=LINE('',#663,#662);
#665=CARTESIAN_POINT('',(9.85000000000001,4.15,5.));
#666=VERTEX_POINT('',#665);
#667=EDGE_CURVE('E1147',#489,#666,#664,.F.);
#668=ORIENTED_EDGE('',*,*,#667,.T.);
#669=DIRECTION('',(1.,0.,0.));
#670=VECTOR('',#669,1.);
#671=CARTESIAN_POINT('',(0.,4.15,5.));
#672=LINE('',#671,#670);
#673=CARTESIAN_POINT('',(0.,4.15,5.));
#674=VERTEX_POINT('',#673);
#675=EDGE_CURVE('E1142',#666,#674,#672,.F.);
#676=ORIENTED_EDGE('',*,*,#675,.T.);
#677=DIRECTION('',(0.,1.,0.));
#678=VECTOR('',#677,1.);
#679=CARTESIAN_POINT('',(0.,4.05,5.));
#680=LINE('',#679,#678);
#681=EDGE_CURVE('E911',#674,#497,#680,.T.);
#682=ORIENTED_EDGE('',*,*,#681,.T.);
#683=EDGE_LOOP('',(#660,#668,#676,#682));
#684=FACE_BOUND('',#683,.T.);
#685=ADVANCED_FACE('F1804',(#684),#659,.F.);
#686=CARTESIAN_POINT('',(0.,4.05,0.));
#687=DIRECTION('',(0.,1.,0.));
#688=DIRECTION('',(0.,0.,1.));
#689=AXIS2_PLACEMENT_3D('',#686,#687,#688);
#690=CYLINDRICAL_SURFACE('',#689,5.);
#691=ORIENTED_EDGE('',*,*,#681,.F.);
#692=CARTESIAN_POINT('',(0.,4.15,0.));
#693=DIRECTION('',(0.,1.,0.));
#694=DIRECTION('',(0.,0.,1.));
#695=AXIS2_PLACEMENT_3D('',#692,#693,#694);
#696=CIRCLE('',#695,5.);
#697=CARTESIAN_POINT('',(0.,4.15,-5.));
#698=VERTEX_POINT('',#697);
#699=EDGE_CURVE('E1353',#674,#698,#696,.F.);
#700=ORIENTED_EDGE('',*,*,#699,.T.);
#701=DIRECTION('',(0.,1.,0.));
#702=VECTOR('',#701,1.);
#703=CARTESIAN_POINT('',(0.,4.05,-5.));
#704=LINE('',#703,#702);
#705=EDGE_CURVE('E910',#698,#251,#704,.T.);
#706=ORIENTED_EDGE('',*,*,#705,.T.);
#707=ORIENTED_EDGE('',*,*,#521,.T.);
#708=EDGE_LOOP('',(#691,#700,#706,#707));
#709=FACE_BOUND('',#708,.T.);
#710=ADVANCED_FACE('F1946',(#709),#690,.F.);
#711=CARTESIAN_POINT('',(0.,4.05,-5.));
#712=DIRECTION('',(0.,0.,1.));
#713=DIRECTION('',(1.,0.,0.));
#714=AXIS2_PLACEMENT_3D('',#711,#712,#713);
#715=PLANE('',#714);
#716=DIRECTION('',(1.,0.,0.));
#717=VECTOR('',#716,1.);
#718=CARTESIAN_POINT('',(9.95000000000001,4.15,-5.));
#719=LINE('',#718,#717);
#720=CARTESIAN_POINT('',(9.85000000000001,4.15,-5.));
#721=VERTEX_POINT('',#720);
#722=EDGE_CURVE('E1070',#698,#721,#719,.T.);
#723=ORIENTED_EDGE('',*,*,#722,.T.);
#724=DIRECTION('',(0.,1.,0.));
#725=VECTOR('',#724,1.);
#726=CARTESIAN_POINT('',(9.85000000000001,4.05,-5.));
#727=LINE('',#726,#725);
#728=EDGE_CURVE('E1073',#721,#253,#727,.T.);
#729=ORIENTED_EDGE('',*,*,#728,.T.);
#730=ORIENTED_EDGE('',*,*,#254,.F.);
#731=ORIENTED_EDGE('',*,*,#705,.F.);
#732=EDGE_LOOP('',(#723,#729,#730,#731));
#733=FACE_BOUND('',#732,.T.);
#734=ADVANCED_FACE('F1955',(#733),#715,.T.);
#735=CARTESIAN_POINT('',(0.,4.05,0.));
#736=DIRECTION('',(0.,1.,0.));
#737=DIRECTION('',(0.,0.,1.));
#738=AXIS2_PLACEMENT_3D('',#735,#736,#737);
#739=PLANE('',#738);
#740=CARTESIAN_POINT('',(7.9,4.05,3.8));
#741=DIRECTION('',(0.,1.,0.));
#742=DIRECTION('',(0.,0.,1.));
#743=AXIS2_PLACEMENT_3D('',#740,#741,#742);
#744=CIRCLE('',#743,0.2);
#745=CARTESIAN_POINT('',(7.9,4.05,4.));
#746=VERTEX_POINT('',#745);
#747=CARTESIAN_POINT('',(8.1,4.05,3.8));
#748=VERTEX_POINT('',#747);
#749=EDGE_CURVE('E1269',#746,#748,#744,.T.);
#750=ORIENTED_EDGE('',*,*,#749,.F.);
#751=DIRECTION('',(1.,0.,0.));
#752=VECTOR('',#751,1.);
#753=CARTESIAN_POINT('',(7.6,4.05,4.));
#754=LINE('',#753,#752);
#755=CARTESIAN_POINT('',(7.7,4.05,4.));
#756=VERTEX_POINT('',#755);
#757=EDGE_CURVE('E1277',#746,#756,#754,.F.);
#758=ORIENTED_EDGE('',*,*,#757,.T.);
#759=CARTESIAN_POINT('',(7.7,4.05,3.8));
#760=DIRECTION('',(0.,1.,0.));
#761=DIRECTION('',(0.,0.,1.));
#762=AXIS2_PLACEMENT_3D('',#759,#760,#761);
#763=CIRCLE('',#762,0.2);
#764=CARTESIAN_POINT('',(7.5,4.05,3.8));
#765=VERTEX_POINT('',#764);
#766=EDGE_CURVE('E1273',#765,#756,#763,.T.);
#767=ORIENTED_EDGE('',*,*,#766,.F.);
#768=DIRECTION('',(0.,0.,1.));
#769=VECTOR('',#768,1.);
#770=CARTESIAN_POINT('',(7.5,4.05,-3.9));
#771=LINE('',#770,#769);
#772=CARTESIAN_POINT('',(7.5,4.05,-4.));
#773=VERTEX_POINT('',#772);
#774=EDGE_CURVE('E1265',#765,#773,#771,.F.);
#775=ORIENTED_EDGE('',*,*,#774,.T.);
#776=DIRECTION('',(1.,0.,0.));
#777=VECTOR('',#776,1.);
#778=CARTESIAN_POINT('',(0.,4.05,-4.));
#779=LINE('',#778,#777);
#780=CARTESIAN_POINT('',(8.1,4.05,-4.));
#781=VERTEX_POINT('',#780);
#782=EDGE_CURVE('E1259',#773,#781,#779,.T.);
#783=ORIENTED_EDGE('',*,*,#782,.T.);
#784=DIRECTION('',(0.,0.,1.));
#785=VECTOR('',#784,1.);
#786=CARTESIAN_POINT('',(8.1,4.05,0.));
#787=LINE('',#786,#785);
#788=EDGE_CURVE('E1262',#781,#748,#787,.T.);
#789=ORIENTED_EDGE('',*,*,#788,.T.);
#790=EDGE_LOOP('',(#750,#758,#767,#775,#783,#789));
#791=FACE_BOUND('',#790,.T.);
#792=CARTESIAN_POINT('',(6.2,4.05,3.8));
#793=DIRECTION('',(0.,1.,0.));
#794=DIRECTION('',(0.,0.,1.));
#795=AXIS2_PLACEMENT_3D('',#792,#793,#794);
#796=CIRCLE('',#795,0.2);
#797=CARTESIAN_POINT('',(6.2,4.05,4.));
#798=VERTEX_POINT('',#797);
#799=CARTESIAN_POINT('',(6.4,4.05,3.8));
#800=VERTEX_POINT('',#799);
#801=EDGE_CURVE('E1248',#798,#800,#796,.T.);
#802=ORIENTED_EDGE('',*,*,#801,.F.);
#803=DIRECTION('',(1.,0.,0.));
#804=VECTOR('',#803,1.);
#805=CARTESIAN_POINT('',(5.9,4.05,4.));
#806=LINE('',#805,#804);
#807=CARTESIAN_POINT('',(6.,4.05,4.));
#808=VERTEX_POINT('',#807);
#809=EDGE_CURVE('E1256',#798,#808,#806,.F.);
#810=ORIENTED_EDGE('',*,*,#809,.T.);
#811=CARTESIAN_POINT('',(6.,4.05,3.8));
#812=DIRECTION('',(0.,1.,0.));
#813=DIRECTION('',(0.,0.,1.));
#814=AXIS2_PLACEMENT_3D('',#811,#812,#813);
#815=CIRCLE('',#814,0.2);
#816=CARTESIAN_POINT('',(5.8,4.05,3.8));
#817=VERTEX_POINT('',#816);
#818=EDGE_CURVE('E1252',#817,#808,#815,.T.);
#819=ORIENTED_EDGE('',*,*,#818,.F.);
#820=DIRECTION('',(0.,0.,1.));
#821=VECTOR('',#820,1.);
#822=CARTESIAN_POINT('',(5.8,4.05,-3.9));
#823=LINE('',#822,#821);
#824=CARTESIAN_POINT('',(5.8,4.05,-4.));
#825=VERTEX_POINT('',#824);
#826=EDGE_CURVE('E1244',#817,#825,#823,.F.);
#827=ORIENTED_EDGE('',*,*,#826,.T.);
#828=DIRECTION('',(1.,0.,0.));
#829=VECTOR('',#828,1.);
#830=CARTESIAN_POINT('',(0.,4.05,-4.));
#831=LINE('',#830,#829);
#832=CARTESIAN_POINT('',(6.4,4.05,-4.));
#833=VERTEX_POINT('',#832);
#834=EDGE_CURVE('E1238',#825,#833,#831,.T.);
#835=ORIENTED_EDGE('',*,*,#834,.T.);
#836=DIRECTION('',(0.,0.,1.));
#837=VECTOR('',#836,1.);
#838=CARTESIAN_POINT('',(6.4,4.05,0.));
#839=LINE('',#838,#837);
#840=EDGE_CURVE('E1241',#833,#800,#839,.T.);
#841=ORIENTED_EDGE('',*,*,#840,.T.);
#842=EDGE_LOOP('',(#802,#810,#819,#827,#835,#841));
#843=FACE_BOUND('',#842,.T.);
#844=CARTESIAN_POINT('',(4.5,4.05,3.8));
#845=DIRECTION('',(0.,1.,0.));
#846=DIRECTION('',(0.,0.,1.));
#847=AXIS2_PLACEMENT_3D('',#844,#845,#846);
#848=CIRCLE('',#847,0.2);
#849=CARTESIAN_POINT('',(4.5,4.05,4.));
#850=VERTEX_POINT('',#849);
#851=CARTESIAN_POINT('',(4.7,4.05,3.8));
#852=VERTEX_POINT('',#851);
#853=EDGE_CURVE('E1227',#850,#852,#848,.T.);
#854=ORIENTED_EDGE('',*,*,#853,.F.);
#855=DIRECTION('',(1.,0.,0.));
#856=VECTOR('',#855,1.);
#857=CARTESIAN_POINT('',(4.2,4.05,4.));
#858=LINE('',#857,#856);
#859=CARTESIAN_POINT('',(4.3,4.05,4.));
#860=VERTEX_POINT('',#859);
#861=EDGE_CURVE('E1235',#850,#860,#858,.F.);
#862=ORIENTED_EDGE('',*,*,#861,.T.);
#863=CARTESIAN_POINT('',(4.3,4.05,3.8));
#864=DIRECTION('',(0.,1.,0.));
#865=DIRECTION('',(0.,0.,1.));
#866=AXIS2_PLACEMENT_3D('',#863,#864,#865);
#867=CIRCLE('',#866,0.2);
#868=CARTESIAN_POINT('',(4.1,4.05,3.8));
#869=VERTEX_POINT('',#868);
#870=EDGE_CURVE('E1231',#869,#860,#867,.T.);
#871=ORIENTED_EDGE('',*,*,#870,.F.);
#872=DIRECTION('',(0.,0.,1.));
#873=VECTOR('',#872,1.);
#874=CARTESIAN_POINT('',(4.1,4.05,-3.9));
#875=LINE('',#874,#873);
#876=CARTESIAN_POINT('',(4.1,4.05,-4.));
#877=VERTEX_POINT('',#876);
#878=EDGE_CURVE('E1223',#869,#877,#875,.F.);
#879=ORIENTED_EDGE('',*,*,#878,.T.);
#880=DIRECTION('',(1.,0.,0.));
#881=VECTOR('',#880,1.);
#882=CARTESIAN_POINT('',(0.,4.05,-4.));
#883=LINE('',#882,#881);
#884=CARTESIAN_POINT('',(4.7,4.05,-4.));
#885=VERTEX_POINT('',#884);
#886=EDGE_CURVE('E1217',#877,#885,#883,.T.);
#887=ORIENTED_EDGE('',*,*,#886,.T.);
#888=DIRECTION('',(0.,0.,1.));
#889=VECTOR('',#888,1.);
#890=CARTESIAN_POINT('',(4.7,4.05,0.));
#891=LINE('',#890,#889);
#892=EDGE_CURVE('E1220',#885,#852,#891,.T.);
#893=ORIENTED_EDGE('',*,*,#892,.T.);
#894=EDGE_LOOP('',(#854,#862,#871,#879,#887,#893));
#895=FACE_BOUND('',#894,.T.);
#896=CARTESIAN_POINT('',(2.8,4.05,3.8));
#897=DIRECTION('',(0.,1.,0.));
#898=DIRECTION('',(0.,0.,1.));
#899=AXIS2_PLACEMENT_3D('',#896,#897,#898);
#900=CIRCLE('',#899,0.2);
#901=CARTESIAN_POINT('',(2.8,4.05,4.));
#902=VERTEX_POINT('',#901);
#903=CARTESIAN_POINT('',(3.,4.05,3.8));
#904=VERTEX_POINT('',#903);
#905=EDGE_CURVE('E1206',#902,#904,#900,.T.);
#906=ORIENTED_EDGE('',*,*,#905,.F.);
#907=DIRECTION('',(1.,0.,0.));
#908=VECTOR('',#907,1.);
#909=CARTESIAN_POINT('',(2.5,4.05,4.));
#910=LINE('',#909,#908);
#911=CARTESIAN_POINT('',(2.6,4.05,4.));
#912=VERTEX_POINT('',#911);
#913=EDGE_CURVE('E1214',#902,#912,#910,.F.);
#914=ORIENTED_EDGE('',*,*,#913,.T.);
#915=CARTESIAN_POINT('',(2.6,4.05,3.8));
#916=DIRECTION('',(0.,1.,0.));
#917=DIRECTION('',(0.,0.,1.));
#918=AXIS2_PLACEMENT_3D('',#915,#916,#917);
#919=CIRCLE('',#918,0.2);
#920=CARTESIAN_POINT('',(2.4,4.05,3.8));
#921=VERTEX_POINT('',#920);
#922=EDGE_CURVE('E1210',#921,#912,#919,.T.);
#923=ORIENTED_EDGE('',*,*,#922,.F.);
#924=DIRECTION('',(0.,0.,1.));
#925=VECTOR('',#924,1.);
#926=CARTESIAN_POINT('',(2.4,4.05,-3.9));
#927=LINE('',#926,#925);
#928=CARTESIAN_POINT('',(2.4,4.05,-3.8));
#929=VERTEX_POINT('',#928);
#930=EDGE_CURVE('E1202',#921,#929,#927,.F.);
#931=ORIENTED_EDGE('',*,*,#930,.T.);
#932=CARTESIAN_POINT('',(2.6,4.05,-3.8));
#933=DIRECTION('',(0.,1.,0.));
#934=DIRECTION('',(0.,0.,1.));
#935=AXIS2_PLACEMENT_3D('',#932,#933,#934);
#936=CIRCLE('',#935,0.2);
#937=CARTESIAN_POINT('',(2.6,4.05,-4.));
#938=VERTEX_POINT('',#937);
#939=EDGE_CURVE('E1198',#938,#929,#936,.T.);
#940=ORIENTED_EDGE('',*,*,#939,.F.);
#941=DIRECTION('',(1.,0.,0.));
#942=VECTOR('',#941,1.);
#943=CARTESIAN_POINT('',(0.,4.05,-4.));
#944=LINE('',#943,#942);
#945=CARTESIAN_POINT('',(2.8,4.05,-4.));
#946=VERTEX_POINT('',#945);
#947=EDGE_CURVE('E1192',#938,#946,#944,.T.);
#948=ORIENTED_EDGE('',*,*,#947,.T.);
#949=CARTESIAN_POINT('',(2.8,4.05,-3.8));
#950=DIRECTION('',(0.,1.,0.));
#951=DIRECTION('',(0.,0.,1.));
#952=AXIS2_PLACEMENT_3D('',#949,#950,#951);
#953=CIRCLE('',#952,0.2);
#954=CARTESIAN_POINT('',(3.,4.05,-3.8));
#955=VERTEX_POINT('',#954);
#956=EDGE_CURVE('E1188',#955,#946,#953,.T.);
#957=ORIENTED_EDGE('',*,*,#956,.F.);
#958=DIRECTION('',(0.,0.,1.));
#959=VECTOR('',#958,1.);
#960=CARTESIAN_POINT('',(3.,4.05,0.));
#961=LINE('',#960,#959);
#962=EDGE_CURVE('E1195',#955,#904,#961,.T.);
#963=ORIENTED_EDGE('',*,*,#962,.T.);
#964=EDGE_LOOP('',(#906,#914,#923,#931,#940,#948,#957,#963));
#965=FACE_BOUND('',#964,.T.);
#966=CARTESIAN_POINT('',(1.1,4.05,-3.8));
#967=DIRECTION('',(0.,1.,0.));
#968=DIRECTION('',(0.,0.,1.));
#969=AXIS2_PLACEMENT_3D('',#966,#967,#968);
#970=CIRCLE('',#969,0.2);
#971=CARTESIAN_POINT('',(1.3,4.05,-3.8));
#972=VERTEX_POINT('',#971);
#973=CARTESIAN_POINT('',(1.1,4.05,-4.));
#974=VERTEX_POINT('',#973);
#975=EDGE_CURVE('E1177',#972,#974,#970,.T.);
#976=ORIENTED_EDGE('',*,*,#975,.F.);
#977=DIRECTION('',(0.,0.,1.));
#978=VECTOR('',#977,1.);
#979=CARTESIAN_POINT('',(1.3,4.05,0.));
#980=LINE('',#979,#978);
#981=CARTESIAN_POINT('',(1.3,4.05,3.8));
#982=VERTEX_POINT('',#981);
#983=EDGE_CURVE('E1185',#972,#982,#980,.T.);
#984=ORIENTED_EDGE('',*,*,#983,.T.);
#985=CARTESIAN_POINT('',(1.1,4.05,3.8));
#986=DIRECTION('',(0.,1.,0.));
#987=DIRECTION('',(0.,0.,1.));
#988=AXIS2_PLACEMENT_3D('',#985,#986,#987);
#989=CIRCLE('',#988,0.2);
#990=CARTESIAN_POINT('',(1.1,4.05,4.));
#991=VERTEX_POINT('',#990);
#992=EDGE_CURVE('E1181',#991,#982,#989,.T.);
#993=ORIENTED_EDGE('',*,*,#992,.F.);
#994=DIRECTION('',(1.,0.,0.));
#995=VECTOR('',#994,1.);
#996=CARTESIAN_POINT('',(0.,4.05,4.));
#997=LINE('',#996,#995);
#998=CARTESIAN_POINT('',(0.,4.05,4.));
#999=VERTEX_POINT('',#998);
#1000=EDGE_CURVE('E1173',#991,#999,#997,.F.);
#1001=ORIENTED_EDGE('',*,*,#1000,.T.);
#1002=CARTESIAN_POINT('',(0.,4.05,0.));
#1003=DIRECTION('',(0.,1.,0.));
#1004=DIRECTION('',(0.,0.,1.));
#1005=AXIS2_PLACEMENT_3D('',#1002,#1003,#1004);
#1006=CIRCLE('',#1005,4.);
#1007=CARTESIAN_POINT('',(0.,4.05,-4.));
#1008=VERTEX_POINT('',#1007);
#1009=EDGE_CURVE('E1167',#999,#1008,#1006,.F.);
#1010=ORIENTED_EDGE('',*,*,#1009,.T.);
#1011=DIRECTION('',(1.,0.,0.));
#1012=VECTOR('',#1011,1.);
#1013=CARTESIAN_POINT('',(0.,4.05,-4.));
#1014=LINE('',#1013,#1012);
#1015=EDGE_CURVE('E1170',#1008,#974,#1014,.T.);
#1016=ORIENTED_EDGE('',*,*,#1015,.T.);
#1017=EDGE_LOOP('',(#976,#984,#993,#1001,#1010,#1016));
#1018=FACE_BOUND('',#1017,.T.);
#1019=DIRECTION('',(1.,0.,0.));
#1020=VECTOR('',#1019,1.);
#1021=CARTESIAN_POINT('',(0.,4.05,-4.9));
#1022=LINE('',#1021,#1020);
#1023=CARTESIAN_POINT('',(9.85000000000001,4.05,-4.9));
#1024=VERTEX_POINT('',#1023);
#1025=CARTESIAN_POINT('',(0.,4.05,-4.9));
#1026=VERTEX_POINT('',#1025);
#1027=EDGE_CURVE('E1160',#1024,#1026,#1022,.F.);
#1028=ORIENTED_EDGE('',*,*,#1027,.T.);
#1029=CARTESIAN_POINT('',(0.,4.05,0.));
#1030=DIRECTION('',(0.,1.,0.));
#1031=DIRECTION('',(0.,0.,1.));
#1032=AXIS2_PLACEMENT_3D('',#1029,#1030,#1031);
#1033=CIRCLE('',#1032,4.9);
#1034=CARTESIAN_POINT('',(0.,4.05,4.9));
#1035=VERTEX_POINT('',#1034);
#1036=EDGE_CURVE('E1163',#1026,#1035,#1033,.T.);
#1037=ORIENTED_EDGE('',*,*,#1036,.T.);
#1038=DIRECTION('',(1.,0.,0.));
#1039=VECTOR('',#1038,1.);
#1040=CARTESIAN_POINT('',(0.,4.05,4.9));
#1041=LINE('',#1040,#1039);
#1042=CARTESIAN_POINT('',(9.85000000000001,4.05,4.9));
#1043=VERTEX_POINT('',#1042);
#1044=EDGE_CURVE('E1154',#1035,#1043,#1041,.T.);
#1045=ORIENTED_EDGE('',*,*,#1044,.T.);
#1046=DIRECTION('',(0.,0.,-1.));
#1047=VECTOR('',#1046,1.);
#1048=CARTESIAN_POINT('',(9.85000000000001,4.05,0.));
#1049=LINE('',#1048,#1047);
#1050=EDGE_CURVE('E1157',#1043,#1024,#1049,.T.);
#1051=ORIENTED_EDGE('',*,*,#1050,.T.);
#1052=EDGE_LOOP('',(#1028,#1037,#1045,#1051));
#1053=FACE_BOUND('',#1052,.T.);
#1054=ADVANCED_FACE('F1852',(#791,#843,#895,#965,#1018,#1053),#739,.T.);
#1055=CARTESIAN_POINT('',(0.,4.25,0.));
#1056=DIRECTION('',(0.,1.,0.));
#1057=DIRECTION('',(0.,0.,1.));
#1058=AXIS2_PLACEMENT_3D('',#1055,#1056,#1057);
#1059=PLANE('',#1058);
#1060=ORIENTED_EDGE('',*,*,#559,.F.);
#1061=DIRECTION('',(0.,0.,1.));
#1062=VECTOR('',#1061,1.);
#1063=CARTESIAN_POINT('',(7.7,4.25,0.));
#1064=LINE('',#1063,#1062);
#1065=CARTESIAN_POINT('',(7.7,4.25,3.8));
#1066=VERTEX_POINT('',#1065);
#1067=EDGE_CURVE('E1555',#550,#1066,#1064,.T.);
#1068=ORIENTED_EDGE('',*,*,#1067,.T.);
#1069=DIRECTION('',(1.,0.,0.));
#1070=VECTOR('',#1069,1.);
#1071=CARTESIAN_POINT('',(0.,4.25,3.8));
#1072=LINE('',#1071,#1070);
#1073=CARTESIAN_POINT('',(7.9,4.25,3.8));
#1074=VERTEX_POINT('',#1073);
#1075=EDGE_CURVE('E1356',#1066,#1074,#1072,.T.);
#1076=ORIENTED_EDGE('',*,*,#1075,.T.);
#1077=DIRECTION('',(0.,0.,1.));
#1078=VECTOR('',#1077,1.);
#1079=CARTESIAN_POINT('',(7.9,4.25,-3.9));
#1080=LINE('',#1079,#1078);
#1081=EDGE_CURVE('E1552',#1074,#558,#1080,.F.);
#1082=ORIENTED_EDGE('',*,*,#1081,.T.);
#1083=EDGE_LOOP('',(#1060,#1068,#1076,#1082));
#1084=FACE_BOUND('',#1083,.T.);
#1085=ADVANCED_FACE('F1848',(#1084),#1059,.T.);
#1086=DIRECTION('',(1.,0.,0.));
#1087=VECTOR('',#1086,1.);
#1088=CARTESIAN_POINT('',(0.,4.25,-3.8));
#1089=LINE('',#1088,#1087);
#1090=CARTESIAN_POINT('',(1.1,4.25,-3.8));
#1091=VERTEX_POINT('',#1090);
#1092=CARTESIAN_POINT('',(0.,4.25,-3.8));
#1093=VERTEX_POINT('',#1092);
#1094=EDGE_CURVE('E1616',#1091,#1093,#1089,.F.);
#1095=ORIENTED_EDGE('',*,*,#1094,.T.);
#1096=CARTESIAN_POINT('',(0.,4.25,0.));
#1097=DIRECTION('',(0.,1.,0.));
#1098=DIRECTION('',(0.,0.,1.));
#1099=AXIS2_PLACEMENT_3D('',#1096,#1097,#1098);
#1100=CIRCLE('',#1099,3.8);
#1101=CARTESIAN_POINT('',(0.,4.25,3.8));
#1102=VERTEX_POINT('',#1101);
#1103=EDGE_CURVE('E1619',#1093,#1102,#1100,.T.);
#1104=ORIENTED_EDGE('',*,*,#1103,.T.);
#1105=DIRECTION('',(1.,0.,0.));
#1106=VECTOR('',#1105,1.);
#1107=CARTESIAN_POINT('',(0.,4.25,3.8));
#1108=LINE('',#1107,#1106);
#1109=CARTESIAN_POINT('',(1.1,4.25,3.8));
#1110=VERTEX_POINT('',#1109);
#1111=EDGE_CURVE('E1610',#1102,#1110,#1108,.T.);
#1112=ORIENTED_EDGE('',*,*,#1111,.T.);
#1113=DIRECTION('',(0.,0.,1.));
#1114=VECTOR('',#1113,1.);
#1115=CARTESIAN_POINT('',(1.1,4.25,-3.8));
#1116=LINE('',#1115,#1114);
#1117=EDGE_CURVE('E1613',#1110,#1091,#1116,.F.);
#1118=ORIENTED_EDGE('',*,*,#1117,.T.);
#1119=EDGE_LOOP('',(#1095,#1104,#1112,#1118));
#1120=FACE_BOUND('',#1119,.T.);
#1121=ADVANCED_FACE('F1851',(#1120),#1059,.T.);
#1122=DIRECTION('',(1.,0.,0.));
#1123=VECTOR('',#1122,1.);
#1124=CARTESIAN_POINT('',(2.6,4.25,-3.8));
#1125=LINE('',#1124,#1123);
#1126=CARTESIAN_POINT('',(2.8,4.25,-3.8));
#1127=VERTEX_POINT('',#1126);
#1128=CARTESIAN_POINT('',(2.6,4.25,-3.8));
#1129=VERTEX_POINT('',#1128);
#1130=EDGE_CURVE('E1603',#1127,#1129,#1125,.F.);
#1131=ORIENTED_EDGE('',*,*,#1130,.T.);
#1132=DIRECTION('',(0.,0.,1.));
#1133=VECTOR('',#1132,1.);
#1134=CARTESIAN_POINT('',(2.6,4.25,0.));
#1135=LINE('',#1134,#1133);
#1136=CARTESIAN_POINT('',(2.6,4.25,3.8));
#1137=VERTEX_POINT('',#1136);
#1138=EDGE_CURVE('E1606',#1129,#1137,#1135,.T.);
#1139=ORIENTED_EDGE('',*,*,#1138,.T.);
#1140=DIRECTION('',(1.,0.,0.));
#1141=VECTOR('',#1140,1.);
#1142=CARTESIAN_POINT('',(0.,4.25,3.8));
#1143=LINE('',#1142,#1141);
#1144=CARTESIAN_POINT('',(2.8,4.25,3.8));
#1145=VERTEX_POINT('',#1144);
#1146=EDGE_CURVE('E1597',#1137,#1145,#1143,.T.);
#1147=ORIENTED_EDGE('',*,*,#1146,.T.);
#1148=DIRECTION('',(0.,0.,1.));
#1149=VECTOR('',#1148,1.);
#1150=CARTESIAN_POINT('',(2.8,4.25,-3.8));
#1151=LINE('',#1150,#1149);
#1152=EDGE_CURVE('E1600',#1145,#1127,#1151,.F.);
#1153=ORIENTED_EDGE('',*,*,#1152,.T.);
#1154=EDGE_LOOP('',(#1131,#1139,#1147,#1153));
#1155=FACE_BOUND('',#1154,.T.);
#1156=ADVANCED_FACE('F1854',(#1155),#1059,.T.);
#1157=ORIENTED_EDGE('',*,*,#643,.F.);
#1158=DIRECTION('',(0.,0.,1.));
#1159=VECTOR('',#1158,1.);
#1160=CARTESIAN_POINT('',(4.3,4.25,0.));
#1161=LINE('',#1160,#1159);
#1162=CARTESIAN_POINT('',(4.3,4.25,3.8));
#1163=VERTEX_POINT('',#1162);
#1164=EDGE_CURVE('E1587',#634,#1163,#1161,.T.);
#1165=ORIENTED_EDGE('',*,*,#1164,.T.);
#1166=DIRECTION('',(1.,0.,0.));
#1167=VECTOR('',#1166,1.);
#1168=CARTESIAN_POINT('',(0.,4.25,3.8));
#1169=LINE('',#1168,#1167);
#1170=CARTESIAN_POINT('',(4.5,4.25,3.8));
#1171=VERTEX_POINT('',#1170);
#1172=EDGE_CURVE('E1581',#1163,#1171,#1169,.T.);
#1173=ORIENTED_EDGE('',*,*,#1172,.T.);
#1174=DIRECTION('',(0.,0.,1.));
#1175=VECTOR('',#1174,1.);
#1176=CARTESIAN_POINT('',(4.5,4.25,-3.9));
#1177=LINE('',#1176,#1175);
#1178=EDGE_CURVE('E1584',#1171,#642,#1177,.F.);
#1179=ORIENTED_EDGE('',*,*,#1178,.T.);
#1180=EDGE_LOOP('',(#1157,#1165,#1173,#1179));
#1181=FACE_BOUND('',#1180,.T.);
#1182=ADVANCED_FACE('F3046',(#1181),#1059,.T.);
#1183=ORIENTED_EDGE('',*,*,#601,.F.);
#1184=DIRECTION('',(0.,0.,1.));
#1185=VECTOR('',#1184,1.);
#1186=CARTESIAN_POINT('',(6.,4.25,0.));
#1187=LINE('',#1186,#1185);
#1188=CARTESIAN_POINT('',(6.,4.25,3.8));
#1189=VERTEX_POINT('',#1188);
#1190=EDGE_CURVE('E1571',#592,#1189,#1187,.T.);
#1191=ORIENTED_EDGE('',*,*,#1190,.T.);
#1192=DIRECTION('',(1.,0.,0.));
#1193=VECTOR('',#1192,1.);
#1194=CARTESIAN_POINT('',(0.,4.25,3.8));
#1195=LINE('',#1194,#1193);
#1196=CARTESIAN_POINT('',(6.2,4.25,3.8));
#1197=VERTEX_POINT('',#1196);
#1198=EDGE_CURVE('E1565',#1189,#1197,#1195,.T.);
#1199=ORIENTED_EDGE('',*,*,#1198,.T.);
#1200=DIRECTION('',(0.,0.,1.));
#1201=VECTOR('',#1200,1.);
#1202=CARTESIAN_POINT('',(6.2,4.25,-3.9));
#1203=LINE('',#1202,#1201);
#1204=EDGE_CURVE('E1568',#1197,#600,#1203,.F.);
#1205=ORIENTED_EDGE('',*,*,#1204,.T.);
#1206=EDGE_LOOP('',(#1183,#1191,#1199,#1205));
#1207=FACE_BOUND('',#1206,.T.);
#1208=ADVANCED_FACE('F1129',(#1207),#1059,.T.);
#1209=CARTESIAN_POINT('',(9.85000000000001,4.25,5.1));
#1210=DIRECTION('',(0.,-1.,0.));
#1211=DIRECTION('',(0.,0.,-1.));
#1212=AXIS2_PLACEMENT_3D('',#1209,#1210,#1211);
#1213=CYLINDRICAL_SURFACE('',#1212,0.1);
#1214=ORIENTED_EDGE('',*,*,#490,.F.);
#1215=ORIENTED_EDGE('',*,*,#117,.F.);
#1216=CARTESIAN_POINT('',(9.85000000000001,4.15,5.1));
#1217=DIRECTION('',(0.,-1.,0.));
#1218=DIRECTION('',(0.,0.,-1.));
#1219=AXIS2_PLACEMENT_3D('',#1216,#1217,#1218);
#1220=CIRCLE('',#1219,0.1);
#1221=EDGE_CURVE('E902',#666,#108,#1220,.T.);
#1222=ORIENTED_EDGE('',*,*,#1221,.F.);
#1223=ORIENTED_EDGE('',*,*,#667,.F.);
#1224=EDGE_LOOP('',(#1214,#1215,#1222,#1223));
#1225=FACE_BOUND('',#1224,.T.);
#1226=ADVANCED_FACE('F1124',(#1225),#1213,.T.);
#1227=CARTESIAN_POINT('',(0.,4.15,4.9));
#1228=DIRECTION('',(1.,0.,0.));
#1229=DIRECTION('',(0.,0.,-1.));
#1230=AXIS2_PLACEMENT_3D('',#1227,#1228,#1229);
#1231=CYLINDRICAL_SURFACE('',#1230,0.1);
#1232=CARTESIAN_POINT('',(0.,4.15,4.9));
#1233=DIRECTION('',(1.,0.,0.));
#1234=DIRECTION('',(0.,0.,-1.));
#1235=AXIS2_PLACEMENT_3D('',#1232,#1233,#1234);
#1236=CIRCLE('',#1235,0.1);
#1237=EDGE_CURVE('E1378',#674,#1035,#1236,.T.);
#1238=ORIENTED_EDGE('',*,*,#1237,.F.);
#1239=ORIENTED_EDGE('',*,*,#675,.F.);
#1240=CARTESIAN_POINT('',(9.85000000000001,4.15,4.9));
#1241=DIRECTION('',(1.,0.,0.));
#1242=DIRECTION('',(0.,0.,-1.));
#1243=AXIS2_PLACEMENT_3D('',#1240,#1241,#1242);
#1244=CIRCLE('',#1243,0.1);
#1245=EDGE_CURVE('E1381',#1043,#666,#1244,.F.);
#1246=ORIENTED_EDGE('',*,*,#1245,.F.);
#1247=ORIENTED_EDGE('',*,*,#1044,.F.);
#1248=EDGE_LOOP('',(#1238,#1239,#1246,#1247));
#1249=FACE_BOUND('',#1248,.T.);
#1250=ADVANCED_FACE('F1120',(#1249),#1231,.F.);
#1251=CARTESIAN_POINT('',(9.85000000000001,4.15,4.9));
#1252=DIRECTION('',(1.,0.,0.));
#1253=DIRECTION('',(0.,0.,-1.));
#1254=AXIS2_PLACEMENT_3D('',#1251,#1252,#1253);
#1255=TOROIDAL_SURFACE('',#1254,0.2,0.1);
#1256=ORIENTED_EDGE('',*,*,#1221,.T.);
#1257=ORIENTED_EDGE('',*,*,#109,.T.);
#1258=CARTESIAN_POINT('',(9.85000000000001,3.95,4.9));
#1259=DIRECTION('',(0.,0.,1.));
#1260=DIRECTION('',(1.,0.,0.));
#1261=AXIS2_PLACEMENT_3D('',#1258,#1259,#1260);
#1262=CIRCLE('',#1261,0.1);
#1263=EDGE_CURVE('E1374',#1043,#99,#1262,.F.);
#1264=ORIENTED_EDGE('',*,*,#1263,.F.);
#1265=ORIENTED_EDGE('',*,*,#1245,.T.);
#1266=EDGE_LOOP('',(#1256,#1257,#1264,#1265));
#1267=FACE_BOUND('',#1266,.T.);
#1268=ADVANCED_FACE('F1116',(#1267),#1255,.T.);
#1269=CARTESIAN_POINT('',(0.,4.15,0.));
#1270=DIRECTION('',(0.,1.,0.));
#1271=DIRECTION('',(0.,0.,1.));
#1272=AXIS2_PLACEMENT_3D('',#1269,#1270,#1271);
#1273=TOROIDAL_SURFACE('',#1272,4.9,0.1);
#1274=ORIENTED_EDGE('',*,*,#1237,.T.);
#1275=ORIENTED_EDGE('',*,*,#1036,.F.);
#1276=CARTESIAN_POINT('',(0.,4.15,-4.9));
#1277=DIRECTION('',(-1.,0.,0.));
#1278=DIRECTION('',(0.,0.,1.));
#1279=AXIS2_PLACEMENT_3D('',#1276,#1277,#1278);
#1280=CIRCLE('',#1279,0.1);
#1281=EDGE_CURVE('E1370',#698,#1026,#1280,.T.);
#1282=ORIENTED_EDGE('',*,*,#1281,.F.);
#1283=ORIENTED_EDGE('',*,*,#699,.F.);
#1284=EDGE_LOOP('',(#1274,#1275,#1282,#1283));
#1285=FACE_BOUND('',#1284,.T.);
#1286=ADVANCED_FACE('F1112',(#1285),#1273,.F.);
#1287=CARTESIAN_POINT('',(9.85000000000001,3.95,0.));
#1288=DIRECTION('',(0.,0.,-1.));
#1289=DIRECTION('',(-1.,0.,0.));
#1290=AXIS2_PLACEMENT_3D('',#1287,#1288,#1289);
#1291=CYLINDRICAL_SURFACE('',#1290,0.1);
#1292=ORIENTED_EDGE('',*,*,#1263,.T.);
#1293=ORIENTED_EDGE('',*,*,#100,.F.);
#1294=CARTESIAN_POINT('',(9.85000000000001,3.95,-4.9));
#1295=DIRECTION('',(0.,0.,-1.));
#1296=DIRECTION('',(-1.,0.,0.));
#1297=AXIS2_PLACEMENT_3D('',#1294,#1295,#1296);
#1298=CIRCLE('',#1297,0.1);
#1299=EDGE_CURVE('E1366',#1024,#91,#1298,.T.);
#1300=ORIENTED_EDGE('',*,*,#1299,.F.);
#1301=ORIENTED_EDGE('',*,*,#1050,.F.);
#1302=EDGE_LOOP('',(#1292,#1293,#1300,#1301));
#1303=FACE_BOUND('',#1302,.T.);
#1304=ADVANCED_FACE('F1108',(#1303),#1291,.T.);
#1305=CARTESIAN_POINT('',(0.,4.15,-4.9));
#1306=DIRECTION('',(-1.,0.,0.));
#1307=DIRECTION('',(0.,0.,1.));
#1308=AXIS2_PLACEMENT_3D('',#1305,#1306,#1307);
#1309=CYLINDRICAL_SURFACE('',#1308,0.1);
#1310=ORIENTED_EDGE('',*,*,#1281,.T.);
#1311=ORIENTED_EDGE('',*,*,#1027,.F.);
#1312=CARTESIAN_POINT('',(9.85000000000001,4.15,-4.9));
#1313=DIRECTION('',(1.,0.,0.));
#1314=DIRECTION('',(0.,0.,-1.));
#1315=AXIS2_PLACEMENT_3D('',#1312,#1313,#1314);
#1316=CIRCLE('',#1315,0.1);
#1317=EDGE_CURVE('E1361',#721,#1024,#1316,.F.);
#1318=ORIENTED_EDGE('',*,*,#1317,.F.);
#1319=ORIENTED_EDGE('',*,*,#722,.F.);
#1320=EDGE_LOOP('',(#1310,#1311,#1318,#1319));
#1321=FACE_BOUND('',#1320,.T.);
#1322=ADVANCED_FACE('F1104',(#1321),#1309,.F.);
#1323=CARTESIAN_POINT('',(9.85000000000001,4.15,-4.9));
#1324=DIRECTION('',(1.,0.,0.));
#1325=DIRECTION('',(0.,0.,-1.));
#1326=AXIS2_PLACEMENT_3D('',#1323,#1324,#1325);
#1327=TOROIDAL_SURFACE('',#1326,0.2,0.1);
#1328=ORIENTED_EDGE('',*,*,#1299,.T.);
#1329=ORIENTED_EDGE('',*,*,#92,.T.);
#1330=CARTESIAN_POINT('',(9.85000000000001,4.15,-5.1));
#1331=DIRECTION('',(0.,-1.,0.));
#1332=DIRECTION('',(0.,0.,-1.));
#1333=AXIS2_PLACEMENT_3D('',#1330,#1331,#1332);
#1334=CIRCLE('',#1333,0.1);
#1335=EDGE_CURVE('E1357',#721,#82,#1334,.F.);
#1336=ORIENTED_EDGE('',*,*,#1335,.F.);
#1337=ORIENTED_EDGE('',*,*,#1317,.T.);
#1338=EDGE_LOOP('',(#1328,#1329,#1336,#1337));
#1339=FACE_BOUND('',#1338,.T.);
#1340=ADVANCED_FACE('F1098',(#1339),#1327,.T.);
#1341=CARTESIAN_POINT('',(9.85000000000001,4.05,-5.1));
#1342=DIRECTION('',(0.,1.,0.));
#1343=DIRECTION('',(0.,0.,1.));
#1344=AXIS2_PLACEMENT_3D('',#1341,#1342,#1343);
#1345=CYLINDRICAL_SURFACE('',#1344,0.1);
#1346=ORIENTED_EDGE('',*,*,#1335,.T.);
#1347=ORIENTED_EDGE('',*,*,#83,.F.);
#1348=ORIENTED_EDGE('',*,*,#279,.F.);
#1349=ORIENTED_EDGE('',*,*,#728,.F.);
#1350=EDGE_LOOP('',(#1346,#1347,#1348,#1349));
#1351=FACE_BOUND('',#1350,.T.);
#1352=ADVANCED_FACE('F1092',(#1351),#1345,.T.);
#1353=CARTESIAN_POINT('',(7.9,4.15,3.8));
#1354=DIRECTION('',(0.,1.,0.));
#1355=DIRECTION('',(0.,0.,1.));
#1356=AXIS2_PLACEMENT_3D('',#1353,#1354,#1355);
#1357=TOROIDAL_SURFACE('',#1356,0.2,0.1);
#1358=CARTESIAN_POINT('',(7.9,4.15,4.));
#1359=DIRECTION('',(-1.,0.,0.));
#1360=DIRECTION('',(0.,0.,1.));
#1361=AXIS2_PLACEMENT_3D('',#1358,#1359,#1360);
#1362=CIRCLE('',#1361,0.1);
#1363=CARTESIAN_POINT('',(7.9,4.15,3.9));
#1364=VERTEX_POINT('',#1363);
#1365=EDGE_CURVE('E1407',#746,#1364,#1362,.F.);
#1366=ORIENTED_EDGE('',*,*,#1365,.F.);
#1367=ORIENTED_EDGE('',*,*,#749,.T.);
#1368=CARTESIAN_POINT('',(8.1,4.15,3.8));
#1369=DIRECTION('',(0.,0.,-1.));
#1370=DIRECTION('',(-1.,0.,0.));
#1371=AXIS2_PLACEMENT_3D('',#1368,#1369,#1370);
#1372=CIRCLE('',#1371,0.1);
#1373=CARTESIAN_POINT('',(8.,4.15,3.8));
#1374=VERTEX_POINT('',#1373);
#1375=EDGE_CURVE('E1411',#1374,#748,#1372,.F.);
#1376=ORIENTED_EDGE('',*,*,#1375,.F.);
#1377=CARTESIAN_POINT('',(7.9,4.15,3.8));
#1378=DIRECTION('',(0.,1.,0.));
#1379=DIRECTION('',(0.,0.,1.));
#1380=AXIS2_PLACEMENT_3D('',#1377,#1378,#1379);
#1381=CIRCLE('',#1380,0.1);
#1382=EDGE_CURVE('E1362',#1374,#1364,#1381,.F.);
#1383=ORIENTED_EDGE('',*,*,#1382,.T.);
#1384=EDGE_LOOP('',(#1366,#1367,#1376,#1383));
#1385=FACE_BOUND('',#1384,.T.);
#1386=ADVANCED_FACE('F1097',(#1385),#1357,.F.);
#1387=CARTESIAN_POINT('',(8.1,4.15,0.));
#1388=DIRECTION('',(0.,0.,1.));
#1389=DIRECTION('',(1.,0.,0.));
#1390=AXIS2_PLACEMENT_3D('',#1387,#1388,#1389);
#1391=CYLINDRICAL_SURFACE('',#1390,0.1);
#1392=ORIENTED_EDGE('',*,*,#1375,.T.);
#1393=ORIENTED_EDGE('',*,*,#788,.F.);
#1394=CARTESIAN_POINT('',(8.1,4.15,-4.));
#1395=DIRECTION('',(0.707106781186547,0.,0.707106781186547));
#1396=DIRECTION('',(0.707106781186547,0.,-0.707106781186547));
#1397=AXIS2_PLACEMENT_3D('',#1394,#1395,#1396);
#1398=ELLIPSE('',#1397,0.14142135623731,0.1);
#1399=EDGE_CURVE('E1403',#539,#781,#1398,.T.);
#1400=ORIENTED_EDGE('',*,*,#1399,.F.);
#1401=DIRECTION('',(0.,0.,1.));
#1402=VECTOR('',#1401,1.);
#1403=CARTESIAN_POINT('',(8.,4.15,0.));
#1404=LINE('',#1403,#1402);
#1405=EDGE_CURVE('E1284',#1374,#539,#1404,.F.);
#1406=ORIENTED_EDGE('',*,*,#1405,.F.);
#1407=EDGE_LOOP('',(#1392,#1393,#1400,#1406));
#1408=FACE_BOUND('',#1407,.T.);
#1409=ADVANCED_FACE('F2010',(#1408),#1391,.F.);
#1410=CARTESIAN_POINT('',(0.,4.15,4.));
#1411=DIRECTION('',(-1.,0.,0.));
#1412=DIRECTION('',(0.,0.,1.));
#1413=AXIS2_PLACEMENT_3D('',#1410,#1411,#1412);
#1414=CYLINDRICAL_SURFACE('',#1413,0.1);
#1415=ORIENTED_EDGE('',*,*,#1365,.T.);
#1416=DIRECTION('',(1.,0.,0.));
#1417=VECTOR('',#1416,1.);
#1418=CARTESIAN_POINT('',(8.,4.15,3.9));
#1419=LINE('',#1418,#1417);
#1420=CARTESIAN_POINT('',(7.7,4.15,3.9));
#1421=VERTEX_POINT('',#1420);
#1422=EDGE_CURVE('E1280',#1421,#1364,#1419,.T.);
#1423=ORIENTED_EDGE('',*,*,#1422,.F.);
#1424=CARTESIAN_POINT('',(7.7,4.15,4.));
#1425=DIRECTION('',(1.,0.,0.));
#1426=DIRECTION('',(0.,0.,-1.));
#1427=AXIS2_PLACEMENT_3D('',#1424,#1425,#1426);
#1428=CIRCLE('',#1427,0.1);
#1429=EDGE_CURVE('E1395',#756,#1421,#1428,.T.);
#1430=ORIENTED_EDGE('',*,*,#1429,.F.);
#1431=ORIENTED_EDGE('',*,*,#757,.F.);
#1432=EDGE_LOOP('',(#1415,#1423,#1430,#1431));
#1433=FACE_BOUND('',#1432,.T.);
#1434=ADVANCED_FACE('F2018',(#1433),#1414,.F.);
#1435=CARTESIAN_POINT('',(0.,4.15,-4.));
#1436=DIRECTION('',(1.,0.,0.));
#1437=DIRECTION('',(0.,0.,-1.));
#1438=AXIS2_PLACEMENT_3D('',#1435,#1436,#1437);
#1439=CYLINDRICAL_SURFACE('',#1438,0.1);
#1440=ORIENTED_EDGE('',*,*,#1399,.T.);
#1441=ORIENTED_EDGE('',*,*,#782,.F.);
#1442=CARTESIAN_POINT('',(7.5,4.15,-4.));
#1443=DIRECTION('',(0.707106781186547,0.,-0.707106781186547));
#1444=DIRECTION('',(0.707106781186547,0.,0.707106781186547));
#1445=AXIS2_PLACEMENT_3D('',#1442,#1443,#1444);
#1446=ELLIPSE('',#1445,0.14142135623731,0.1);
#1447=EDGE_CURVE('E1391',#541,#773,#1446,.T.);
#1448=ORIENTED_EDGE('',*,*,#1447,.F.);
#1449=ORIENTED_EDGE('',*,*,#542,.F.);
#1450=EDGE_LOOP('',(#1440,#1441,#1448,#1449));
#1451=FACE_BOUND('',#1450,.T.);
#1452=ADVANCED_FACE('F1994',(#1451),#1439,.F.);
#1453=CARTESIAN_POINT('',(7.7,4.15,3.8));
#1454=DIRECTION('',(0.,1.,0.));
#1455=DIRECTION('',(0.,0.,1.));
#1456=AXIS2_PLACEMENT_3D('',#1453,#1454,#1455);
#1457=TOROIDAL_SURFACE('',#1456,0.2,0.1);
#1458=ORIENTED_EDGE('',*,*,#1429,.T.);
#1459=CARTESIAN_POINT('',(7.7,4.15,3.8));
#1460=DIRECTION('',(0.,1.,0.));
#1461=DIRECTION('',(0.,0.,1.));
#1462=AXIS2_PLACEMENT_3D('',#1459,#1460,#1461);
#1463=CIRCLE('',#1462,0.1);
#1464=CARTESIAN_POINT('',(7.6,4.15,3.8));
#1465=VERTEX_POINT('',#1464);
#1466=EDGE_CURVE('E1399',#1421,#1465,#1463,.F.);
#1467=ORIENTED_EDGE('',*,*,#1466,.T.);
#1468=CARTESIAN_POINT('',(7.5,4.15,3.8));
#1469=DIRECTION('',(0.,0.,-1.));
#1470=DIRECTION('',(-1.,0.,0.));
#1471=AXIS2_PLACEMENT_3D('',#1468,#1469,#1470);
#1472=CIRCLE('',#1471,0.1);
#1473=EDGE_CURVE('E1388',#765,#1465,#1472,.F.);
#1474=ORIENTED_EDGE('',*,*,#1473,.F.);
#1475=ORIENTED_EDGE('',*,*,#766,.T.);
#1476=EDGE_LOOP('',(#1458,#1467,#1474,#1475));
#1477=FACE_BOUND('',#1476,.T.);
#1478=ADVANCED_FACE('F2020',(#1477),#1457,.F.);
#1479=CARTESIAN_POINT('',(7.5,4.15,0.));
#1480=DIRECTION('',(0.,0.,-1.));
#1481=DIRECTION('',(-1.,0.,0.));
#1482=AXIS2_PLACEMENT_3D('',#1479,#1480,#1481);
#1483=CYLINDRICAL_SURFACE('',#1482,0.1);
#1484=ORIENTED_EDGE('',*,*,#1447,.T.);
#1485=ORIENTED_EDGE('',*,*,#774,.F.);
#1486=ORIENTED_EDGE('',*,*,#1473,.T.);
#1487=DIRECTION('',(0.,0.,1.));
#1488=VECTOR('',#1487,1.);
#1489=CARTESIAN_POINT('',(7.6,4.15,3.9));
#1490=LINE('',#1489,#1488);
#1491=EDGE_CURVE('E1150',#541,#1465,#1490,.T.);
#1492=ORIENTED_EDGE('',*,*,#1491,.F.);
#1493=EDGE_LOOP('',(#1484,#1485,#1486,#1492));
#1494=FACE_BOUND('',#1493,.T.);
#1495=ADVANCED_FACE('F1131',(#1494),#1483,.F.);
#1496=CARTESIAN_POINT('',(6.2,4.15,3.8));
#1497=DIRECTION('',(0.,1.,0.));
#1498=DIRECTION('',(0.,0.,1.));
#1499=AXIS2_PLACEMENT_3D('',#1496,#1497,#1498);
#1500=TOROIDAL_SURFACE('',#1499,0.2,0.1);
#1501=CARTESIAN_POINT('',(6.2,4.15,4.));
#1502=DIRECTION('',(-1.,0.,0.));
#1503=DIRECTION('',(0.,0.,1.));
#1504=AXIS2_PLACEMENT_3D('',#1501,#1502,#1503);
#1505=CIRCLE('',#1504,0.1);
#1506=CARTESIAN_POINT('',(6.2,4.15,3.9));
#1507=VERTEX_POINT('',#1506);
#1508=EDGE_CURVE('E1436',#798,#1507,#1505,.F.);
#1509=ORIENTED_EDGE('',*,*,#1508,.F.);
#1510=ORIENTED_EDGE('',*,*,#801,.T.);
#1511=CARTESIAN_POINT('',(6.4,4.15,3.8));
#1512=DIRECTION('',(0.,0.,-1.));
#1513=DIRECTION('',(-1.,0.,0.));
#1514=AXIS2_PLACEMENT_3D('',#1511,#1512,#1513);
#1515=CIRCLE('',#1514,0.1);
#1516=CARTESIAN_POINT('',(6.3,4.15,3.8));
#1517=VERTEX_POINT('',#1516);
#1518=EDGE_CURVE('E1440',#1517,#800,#1515,.F.);
#1519=ORIENTED_EDGE('',*,*,#1518,.F.);
#1520=CARTESIAN_POINT('',(6.2,4.15,3.8));
#1521=DIRECTION('',(0.,1.,0.));
#1522=DIRECTION('',(0.,0.,1.));
#1523=AXIS2_PLACEMENT_3D('',#1520,#1521,#1522);
#1524=CIRCLE('',#1523,0.1);
#1525=EDGE_CURVE('E1392',#1517,#1507,#1524,.F.);
#1526=ORIENTED_EDGE('',*,*,#1525,.T.);
#1527=EDGE_LOOP('',(#1509,#1510,#1519,#1526));
#1528=FACE_BOUND('',#1527,.T.);
#1529=ADVANCED_FACE('F2855',(#1528),#1500,.F.);
#1530=CARTESIAN_POINT('',(6.4,4.15,0.));
#1531=DIRECTION('',(0.,0.,1.));
#1532=DIRECTION('',(1.,0.,0.));
#1533=AXIS2_PLACEMENT_3D('',#1530,#1531,#1532);
#1534=CYLINDRICAL_SURFACE('',#1533,0.1);
#1535=ORIENTED_EDGE('',*,*,#1518,.T.);
#1536=ORIENTED_EDGE('',*,*,#840,.F.);
#1537=CARTESIAN_POINT('',(6.4,4.15,-4.));
#1538=DIRECTION('',(0.707106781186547,0.,0.707106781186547));
#1539=DIRECTION('',(0.707106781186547,0.,-0.707106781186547));
#1540=AXIS2_PLACEMENT_3D('',#1537,#1538,#1539);
#1541=ELLIPSE('',#1540,0.14142135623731,0.1);
#1542=EDGE_CURVE('E1432',#581,#833,#1541,.T.);
#1543=ORIENTED_EDGE('',*,*,#1542,.F.);
#1544=DIRECTION('',(0.,0.,1.));
#1545=VECTOR('',#1544,1.);
#1546=CARTESIAN_POINT('',(6.3,4.15,0.));
#1547=LINE('',#1546,#1545);
#1548=EDGE_CURVE('E1299',#1517,#581,#1547,.F.);
#1549=ORIENTED_EDGE('',*,*,#1548,.F.);
#1550=EDGE_LOOP('',(#1535,#1536,#1543,#1549));
#1551=FACE_BOUND('',#1550,.T.);
#1552=ADVANCED_FACE('F2846',(#1551),#1534,.F.);
#1553=CARTESIAN_POINT('',(0.,4.15,4.));
#1554=DIRECTION('',(-1.,0.,0.));
#1555=DIRECTION('',(0.,0.,1.));
#1556=AXIS2_PLACEMENT_3D('',#1553,#1554,#1555);
#1557=CYLINDRICAL_SURFACE('',#1556,0.1);
#1558=ORIENTED_EDGE('',*,*,#1508,.T.);
#1559=DIRECTION('',(1.,0.,0.));
#1560=VECTOR('',#1559,1.);
#1561=CARTESIAN_POINT('',(6.3,4.15,3.9));
#1562=LINE('',#1561,#1560);
#1563=CARTESIAN_POINT('',(6.,4.15,3.9));
#1564=VERTEX_POINT('',#1563);
#1565=EDGE_CURVE('E1295',#1564,#1507,#1562,.T.);
#1566=ORIENTED_EDGE('',*,*,#1565,.F.);
#1567=CARTESIAN_POINT('',(6.,4.15,4.));
#1568=DIRECTION('',(1.,0.,0.));
#1569=DIRECTION('',(0.,0.,-1.));
#1570=AXIS2_PLACEMENT_3D('',#1567,#1568,#1569);
#1571=CIRCLE('',#1570,0.1);
#1572=EDGE_CURVE('E1424',#808,#1564,#1571,.T.);
#1573=ORIENTED_EDGE('',*,*,#1572,.F.);
#1574=ORIENTED_EDGE('',*,*,#809,.F.);
#1575=EDGE_LOOP('',(#1558,#1566,#1573,#1574));
#1576=FACE_BOUND('',#1575,.T.);
#1577=ADVANCED_FACE('F2837',(#1576),#1557,.F.);
#1578=CARTESIAN_POINT('',(0.,4.15,-4.));
#1579=DIRECTION('',(1.,0.,0.));
#1580=DIRECTION('',(0.,0.,-1.));
#1581=AXIS2_PLACEMENT_3D('',#1578,#1579,#1580);
#1582=CYLINDRICAL_SURFACE('',#1581,0.1);
#1583=ORIENTED_EDGE('',*,*,#1542,.T.);
#1584=ORIENTED_EDGE('',*,*,#834,.F.);
#1585=CARTESIAN_POINT('',(5.8,4.15,-4.));
#1586=DIRECTION('',(0.707106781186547,0.,-0.707106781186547));
#1587=DIRECTION('',(0.707106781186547,0.,0.707106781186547));
#1588=AXIS2_PLACEMENT_3D('',#1585,#1586,#1587);
#1589=ELLIPSE('',#1588,0.14142135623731,0.1);
#1590=EDGE_CURVE('E1420',#583,#825,#1589,.T.);
#1591=ORIENTED_EDGE('',*,*,#1590,.F.);
#1592=ORIENTED_EDGE('',*,*,#584,.F.);
#1593=EDGE_LOOP('',(#1583,#1584,#1591,#1592));
#1594=FACE_BOUND('',#1593,.T.);
#1595=ADVANCED_FACE('F2828',(#1594),#1582,.F.);
#1596=CARTESIAN_POINT('',(6.,4.15,3.8));
#1597=DIRECTION('',(0.,1.,0.));
#1598=DIRECTION('',(0.,0.,1.));
#1599=AXIS2_PLACEMENT_3D('',#1596,#1597,#1598);
#1600=TOROIDAL_SURFACE('',#1599,0.2,0.1);
#1601=ORIENTED_EDGE('',*,*,#1572,.T.);
#1602=CARTESIAN_POINT('',(6.,4.15,3.8));
#1603=DIRECTION('',(0.,1.,0.));
#1604=DIRECTION('',(0.,0.,1.));
#1605=AXIS2_PLACEMENT_3D('',#1602,#1603,#1604);
#1606=CIRCLE('',#1605,0.1);
#1607=CARTESIAN_POINT('',(5.9,4.15,3.8));
#1608=VERTEX_POINT('',#1607);
#1609=EDGE_CURVE('E1428',#1564,#1608,#1606,.F.);
#1610=ORIENTED_EDGE('',*,*,#1609,.T.);
#1611=CARTESIAN_POINT('',(5.8,4.15,3.8));
#1612=DIRECTION('',(0.,0.,-1.));
#1613=DIRECTION('',(-1.,0.,0.));
#1614=AXIS2_PLACEMENT_3D('',#1611,#1612,#1613);
#1615=CIRCLE('',#1614,0.1);
#1616=EDGE_CURVE('E1417',#817,#1608,#1615,.F.);
#1617=ORIENTED_EDGE('',*,*,#1616,.F.);
#1618=ORIENTED_EDGE('',*,*,#818,.T.);
#1619=EDGE_LOOP('',(#1601,#1610,#1617,#1618));
#1620=FACE_BOUND('',#1619,.T.);
#1621=ADVANCED_FACE('F2819',(#1620),#1600,.F.);
#1622=CARTESIAN_POINT('',(5.8,4.15,0.));
#1623=DIRECTION('',(0.,0.,-1.));
#1624=DIRECTION('',(-1.,0.,0.));
#1625=AXIS2_PLACEMENT_3D('',#1622,#1623,#1624);
#1626=CYLINDRICAL_SURFACE('',#1625,0.1);
#1627=ORIENTED_EDGE('',*,*,#1590,.T.);
#1628=ORIENTED_EDGE('',*,*,#826,.F.);
#1629=ORIENTED_EDGE('',*,*,#1616,.T.);
#1630=DIRECTION('',(0.,0.,1.));
#1631=VECTOR('',#1630,1.);
#1632=CARTESIAN_POINT('',(5.9,4.15,3.9));
#1633=LINE('',#1632,#1631);
#1634=EDGE_CURVE('E1291',#583,#1608,#1633,.T.);
#1635=ORIENTED_EDGE('',*,*,#1634,.F.);
#1636=EDGE_LOOP('',(#1627,#1628,#1629,#1635));
#1637=FACE_BOUND('',#1636,.T.);
#1638=ADVANCED_FACE('F2810',(#1637),#1626,.F.);
#1639=CARTESIAN_POINT('',(4.5,4.15,3.8));
#1640=DIRECTION('',(0.,1.,0.));
#1641=DIRECTION('',(0.,0.,1.));
#1642=AXIS2_PLACEMENT_3D('',#1639,#1640,#1641);
#1643=TOROIDAL_SURFACE('',#1642,0.2,0.1);
#1644=CARTESIAN_POINT('',(4.5,4.15,4.));
#1645=DIRECTION('',(-1.,0.,0.));
#1646=DIRECTION('',(0.,0.,1.));
#1647=AXIS2_PLACEMENT_3D('',#1644,#1645,#1646);
#1648=CIRCLE('',#1647,0.1);
#1649=CARTESIAN_POINT('',(4.5,4.15,3.9));
#1650=VERTEX_POINT('',#1649);
#1651=EDGE_CURVE('E1465',#850,#1650,#1648,.F.);
#1652=ORIENTED_EDGE('',*,*,#1651,.F.);
#1653=ORIENTED_EDGE('',*,*,#853,.T.);
#1654=CARTESIAN_POINT('',(4.7,4.15,3.8));
#1655=DIRECTION('',(0.,0.,-1.));
#1656=DIRECTION('',(-1.,0.,0.));
#1657=AXIS2_PLACEMENT_3D('',#1654,#1655,#1656);
#1658=CIRCLE('',#1657,0.1);
#1659=CARTESIAN_POINT('',(4.6,4.15,3.8));
#1660=VERTEX_POINT('',#1659);
#1661=EDGE_CURVE('E1469',#1660,#852,#1658,.F.);
#1662=ORIENTED_EDGE('',*,*,#1661,.F.);
#1663=CARTESIAN_POINT('',(4.5,4.15,3.8));
#1664=DIRECTION('',(0.,1.,0.));
#1665=DIRECTION('',(0.,0.,1.));
#1666=AXIS2_PLACEMENT_3D('',#1663,#1664,#1665);
#1667=CIRCLE('',#1666,0.1);
#1668=EDGE_CURVE('E1421',#1660,#1650,#1667,.F.);
#1669=ORIENTED_EDGE('',*,*,#1668,.T.);
#1670=EDGE_LOOP('',(#1652,#1653,#1662,#1669));
#1671=FACE_BOUND('',#1670,.T.);
#1672=ADVANCED_FACE('F2801',(#1671),#1643,.F.);
#1673=CARTESIAN_POINT('',(4.7,4.15,0.));
#1674=DIRECTION('',(0.,0.,1.));
#1675=DIRECTION('',(1.,0.,0.));
#1676=AXIS2_PLACEMENT_3D('',#1673,#1674,#1675);
#1677=CYLINDRICAL_SURFACE('',#1676,0.1);
#1678=ORIENTED_EDGE('',*,*,#1661,.T.);
#1679=ORIENTED_EDGE('',*,*,#892,.F.);
#1680=CARTESIAN_POINT('',(4.7,4.15,-4.));
#1681=DIRECTION('',(0.707106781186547,0.,0.707106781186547));
#1682=DIRECTION('',(0.707106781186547,0.,-0.707106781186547));
#1683=AXIS2_PLACEMENT_3D('',#1680,#1681,#1682);
#1684=ELLIPSE('',#1683,0.14142135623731,0.1);
#1685=EDGE_CURVE('E1461',#623,#885,#1684,.T.);
#1686=ORIENTED_EDGE('',*,*,#1685,.F.);
#1687=DIRECTION('',(0.,0.,1.));
#1688=VECTOR('',#1687,1.);
#1689=CARTESIAN_POINT('',(4.6,4.15,0.));
#1690=LINE('',#1689,#1688);
#1691=EDGE_CURVE('E1314',#1660,#623,#1690,.F.);
#1692=ORIENTED_EDGE('',*,*,#1691,.F.);
#1693=EDGE_LOOP('',(#1678,#1679,#1686,#1692));
#1694=FACE_BOUND('',#1693,.T.);
#1695=ADVANCED_FACE('F2792',(#1694),#1677,.F.);
#1696=CARTESIAN_POINT('',(0.,4.15,4.));
#1697=DIRECTION('',(-1.,0.,0.));
#1698=DIRECTION('',(0.,0.,1.));
#1699=AXIS2_PLACEMENT_3D('',#1696,#1697,#1698);
#1700=CYLINDRICAL_SURFACE('',#1699,0.1);
#1701=ORIENTED_EDGE('',*,*,#1651,.T.);
#1702=DIRECTION('',(1.,0.,0.));
#1703=VECTOR('',#1702,1.);
#1704=CARTESIAN_POINT('',(4.6,4.15,3.9));
#1705=LINE('',#1704,#1703);
#1706=CARTESIAN_POINT('',(4.3,4.15,3.9));
#1707=VERTEX_POINT('',#1706);
#1708=EDGE_CURVE('E1310',#1707,#1650,#1705,.T.);
#1709=ORIENTED_EDGE('',*,*,#1708,.F.);
#1710=CARTESIAN_POINT('',(4.3,4.15,4.));
#1711=DIRECTION('',(1.,0.,0.));
#1712=DIRECTION('',(0.,0.,-1.));
#1713=AXIS2_PLACEMENT_3D('',#1710,#1711,#1712);
#1714=CIRCLE('',#1713,0.1);
#1715=EDGE_CURVE('E1453',#860,#1707,#1714,.T.);
#1716=ORIENTED_EDGE('',*,*,#1715,.F.);
#1717=ORIENTED_EDGE('',*,*,#861,.F.);
#1718=EDGE_LOOP('',(#1701,#1709,#1716,#1717));
#1719=FACE_BOUND('',#1718,.T.);
#1720=ADVANCED_FACE('F2783',(#1719),#1700,.F.);
#1721=CARTESIAN_POINT('',(0.,4.15,-4.));
#1722=DIRECTION('',(1.,0.,0.));
#1723=DIRECTION('',(0.,0.,-1.));
#1724=AXIS2_PLACEMENT_3D('',#1721,#1722,#1723);
#1725=CYLINDRICAL_SURFACE('',#1724,0.1);
#1726=ORIENTED_EDGE('',*,*,#1685,.T.);
#1727=ORIENTED_EDGE('',*,*,#886,.F.);
#1728=CARTESIAN_POINT('',(4.1,4.15,-4.));
#1729=DIRECTION('',(0.707106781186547,0.,-0.707106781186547));
#1730=DIRECTION('',(0.707106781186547,0.,0.707106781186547));
#1731=AXIS2_PLACEMENT_3D('',#1728,#1729,#1730);
#1732=ELLIPSE('',#1731,0.14142135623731,0.1);
#1733=EDGE_CURVE('E1449',#625,#877,#1732,.T.);
#1734=ORIENTED_EDGE('',*,*,#1733,.F.);
#1735=ORIENTED_EDGE('',*,*,#626,.F.);
#1736=EDGE_LOOP('',(#1726,#1727,#1734,#1735));
#1737=FACE_BOUND('',#1736,.T.);
#1738=ADVANCED_FACE('F2774',(#1737),#1725,.F.);
#1739=CARTESIAN_POINT('',(4.3,4.15,3.8));
#1740=DIRECTION('',(0.,1.,0.));
#1741=DIRECTION('',(0.,0.,1.));
#1742=AXIS2_PLACEMENT_3D('',#1739,#1740,#1741);
#1743=TOROIDAL_SURFACE('',#1742,0.2,0.1);
#1744=ORIENTED_EDGE('',*,*,#1715,.T.);
#1745=CARTESIAN_POINT('',(4.3,4.15,3.8));
#1746=DIRECTION('',(0.,1.,0.));
#1747=DIRECTION('',(0.,0.,1.));
#1748=AXIS2_PLACEMENT_3D('',#1745,#1746,#1747);
#1749=CIRCLE('',#1748,0.1);
#1750=CARTESIAN_POINT('',(4.2,4.15,3.8));
#1751=VERTEX_POINT('',#1750);
#1752=EDGE_CURVE('E1457',#1707,#1751,#1749,.F.);
#1753=ORIENTED_EDGE('',*,*,#1752,.T.);
#1754=CARTESIAN_POINT('',(4.1,4.15,3.8));
#1755=DIRECTION('',(0.,0.,-1.));
#1756=DIRECTION('',(-1.,0.,0.));
#1757=AXIS2_PLACEMENT_3D('',#1754,#1755,#1756);
#1758=CIRCLE('',#1757,0.1);
#1759=EDGE_CURVE('E1446',#869,#1751,#1758,.F.);
#1760=ORIENTED_EDGE('',*,*,#1759,.F.);
#1761=ORIENTED_EDGE('',*,*,#870,.T.);
#1762=EDGE_LOOP('',(#1744,#1753,#1760,#1761));
#1763=FACE_BOUND('',#1762,.T.);
#1764=ADVANCED_FACE('F2765',(#1763),#1743,.F.);
#1765=CARTESIAN_POINT('',(4.1,4.15,0.));
#1766=DIRECTION('',(0.,0.,-1.));
#1767=DIRECTION('',(-1.,0.,0.));
#1768=AXIS2_PLACEMENT_3D('',#1765,#1766,#1767);
#1769=CYLINDRICAL_SURFACE('',#1768,0.1);
#1770=ORIENTED_EDGE('',*,*,#1733,.T.);
#1771=ORIENTED_EDGE('',*,*,#878,.F.);
#1772=ORIENTED_EDGE('',*,*,#1759,.T.);
#1773=DIRECTION('',(0.,0.,1.));
#1774=VECTOR('',#1773,1.);
#1775=CARTESIAN_POINT('',(4.2,4.15,3.9));
#1776=LINE('',#1775,#1774);
#1777=EDGE_CURVE('E1306',#625,#1751,#1776,.T.);
#1778=ORIENTED_EDGE('',*,*,#1777,.F.);
#1779=EDGE_LOOP('',(#1770,#1771,#1772,#1778));
#1780=FACE_BOUND('',#1779,.T.);
#1781=ADVANCED_FACE('F2756',(#1780),#1769,.F.);
#1782=CARTESIAN_POINT('',(3.,4.15,0.));
#1783=DIRECTION('',(0.,0.,1.));
#1784=DIRECTION('',(1.,0.,0.));
#1785=AXIS2_PLACEMENT_3D('',#1782,#1783,#1784);
#1786=CYLINDRICAL_SURFACE('',#1785,0.1);
#1787=CARTESIAN_POINT('',(3.,4.15,3.8));
#1788=DIRECTION('',(0.,0.,-1.));
#1789=DIRECTION('',(-1.,0.,0.));
#1790=AXIS2_PLACEMENT_3D('',#1787,#1788,#1789);
#1791=CIRCLE('',#1790,0.1);
#1792=CARTESIAN_POINT('',(2.9,4.15,3.8));
#1793=VERTEX_POINT('',#1792);
#1794=EDGE_CURVE('E1507',#904,#1793,#1791,.T.);
#1795=ORIENTED_EDGE('',*,*,#1794,.F.);
#1796=ORIENTED_EDGE('',*,*,#962,.F.);
#1797=CARTESIAN_POINT('',(3.,4.15,-3.8));
#1798=DIRECTION('',(0.,0.,1.));
#1799=DIRECTION('',(1.,0.,0.));
#1800=AXIS2_PLACEMENT_3D('',#1797,#1798,#1799);
#1801=CIRCLE('',#1800,0.1);
#1802=CARTESIAN_POINT('',(2.9,4.15,-3.8));
#1803=VERTEX_POINT('',#1802);
#1804=EDGE_CURVE('E1450',#1803,#955,#1801,.T.);
#1805=ORIENTED_EDGE('',*,*,#1804,.F.);
#1806=DIRECTION('',(0.,0.,1.));
#1807=VECTOR('',#1806,1.);
#1808=CARTESIAN_POINT('',(2.9,4.15,0.));
#1809=LINE('',#1808,#1807);
#1810=EDGE_CURVE('E1329',#1793,#1803,#1809,.F.);
#1811=ORIENTED_EDGE('',*,*,#1810,.F.);
#1812=EDGE_LOOP('',(#1795,#1796,#1805,#1811));
#1813=FACE_BOUND('',#1812,.T.);
#1814=ADVANCED_FACE('F2747',(#1813),#1786,.F.);
#1815=CARTESIAN_POINT('',(2.8,4.15,-3.8));
#1816=DIRECTION('',(0.,1.,0.));
#1817=DIRECTION('',(0.,0.,1.));
#1818=AXIS2_PLACEMENT_3D('',#1815,#1816,#1817);
#1819=TOROIDAL_SURFACE('',#1818,0.2,0.1);
#1820=ORIENTED_EDGE('',*,*,#1804,.T.);
#1821=ORIENTED_EDGE('',*,*,#956,.T.);
#1822=CARTESIAN_POINT('',(2.8,4.15,-4.));
#1823=DIRECTION('',(-1.,0.,0.));
#1824=DIRECTION('',(0.,0.,1.));
#1825=AXIS2_PLACEMENT_3D('',#1822,#1823,#1824);
#1826=CIRCLE('',#1825,0.1);
#1827=CARTESIAN_POINT('',(2.8,4.15,-3.9));
#1828=VERTEX_POINT('',#1827);
#1829=EDGE_CURVE('E1503',#1828,#946,#1826,.F.);
#1830=ORIENTED_EDGE('',*,*,#1829,.F.);
#1831=CARTESIAN_POINT('',(2.8,4.15,-3.8));
#1832=DIRECTION('',(0.,1.,0.));
#1833=DIRECTION('',(0.,0.,1.));
#1834=AXIS2_PLACEMENT_3D('',#1831,#1832,#1833);
#1835=CIRCLE('',#1834,0.1);
#1836=EDGE_CURVE('E1514',#1828,#1803,#1835,.F.);
#1837=ORIENTED_EDGE('',*,*,#1836,.T.);
#1838=EDGE_LOOP('',(#1820,#1821,#1830,#1837));
#1839=FACE_BOUND('',#1838,.T.);
#1840=ADVANCED_FACE('F2738',(#1839),#1819,.F.);
#1841=CARTESIAN_POINT('',(2.8,4.15,3.8));
#1842=DIRECTION('',(0.,1.,0.));
#1843=DIRECTION('',(0.,0.,1.));
#1844=AXIS2_PLACEMENT_3D('',#1841,#1842,#1843);
#1845=TOROIDAL_SURFACE('',#1844,0.2,0.1);
#1846=ORIENTED_EDGE('',*,*,#1794,.T.);
#1847=CARTESIAN_POINT('',(2.8,4.15,3.8));
#1848=DIRECTION('',(0.,1.,0.));
#1849=DIRECTION('',(0.,0.,1.));
#1850=AXIS2_PLACEMENT_3D('',#1847,#1848,#1849);
#1851=CIRCLE('',#1850,0.1);
#1852=CARTESIAN_POINT('',(2.8,4.15,3.9));
#1853=VERTEX_POINT('',#1852);
#1854=EDGE_CURVE('E1511',#1793,#1853,#1851,.F.);
#1855=ORIENTED_EDGE('',*,*,#1854,.T.);
#1856=CARTESIAN_POINT('',(2.8,4.15,4.));
#1857=DIRECTION('',(-1.,0.,0.));
#1858=DIRECTION('',(0.,0.,1.));
#1859=AXIS2_PLACEMENT_3D('',#1856,#1857,#1858);
#1860=CIRCLE('',#1859,0.1);
#1861=EDGE_CURVE('E1499',#902,#1853,#1860,.F.);
#1862=ORIENTED_EDGE('',*,*,#1861,.F.);
#1863=ORIENTED_EDGE('',*,*,#905,.T.);
#1864=EDGE_LOOP('',(#1846,#1855,#1862,#1863));
#1865=FACE_BOUND('',#1864,.T.);
#1866=ADVANCED_FACE('F2729',(#1865),#1845,.F.);
#1867=CARTESIAN_POINT('',(0.,4.15,-4.));
#1868=DIRECTION('',(1.,0.,0.));
#1869=DIRECTION('',(0.,0.,-1.));
#1870=AXIS2_PLACEMENT_3D('',#1867,#1868,#1869);
#1871=CYLINDRICAL_SURFACE('',#1870,0.1);
#1872=ORIENTED_EDGE('',*,*,#1829,.T.);
#1873=ORIENTED_EDGE('',*,*,#947,.F.);
#1874=CARTESIAN_POINT('',(2.6,4.15,-4.));
#1875=DIRECTION('',(1.,0.,0.));
#1876=DIRECTION('',(0.,0.,-1.));
#1877=AXIS2_PLACEMENT_3D('',#1874,#1875,#1876);
#1878=CIRCLE('',#1877,0.1);
#1879=CARTESIAN_POINT('',(2.6,4.15,-3.9));
#1880=VERTEX_POINT('',#1879);
#1881=EDGE_CURVE('E1495',#1880,#938,#1878,.T.);
#1882=ORIENTED_EDGE('',*,*,#1881,.F.);
#1883=DIRECTION('',(1.,0.,0.));
#1884=VECTOR('',#1883,1.);
#1885=CARTESIAN_POINT('',(0.,4.15,-3.9));
#1886=LINE('',#1885,#1884);
#1887=EDGE_CURVE('E1333',#1828,#1880,#1886,.F.);
#1888=ORIENTED_EDGE('',*,*,#1887,.F.);
#1889=EDGE_LOOP('',(#1872,#1873,#1882,#1888));
#1890=FACE_BOUND('',#1889,.T.);
#1891=ADVANCED_FACE('F2720',(#1890),#1871,.F.);
#1892=CARTESIAN_POINT('',(0.,4.15,4.));
#1893=DIRECTION('',(-1.,0.,0.));
#1894=DIRECTION('',(0.,0.,1.));
#1895=AXIS2_PLACEMENT_3D('',#1892,#1893,#1894);
#1896=CYLINDRICAL_SURFACE('',#1895,0.1);
#1897=ORIENTED_EDGE('',*,*,#1861,.T.);
#1898=DIRECTION('',(1.,0.,0.));
#1899=VECTOR('',#1898,1.);
#1900=CARTESIAN_POINT('',(2.9,4.15,3.9));
#1901=LINE('',#1900,#1899);
#1902=CARTESIAN_POINT('',(2.6,4.15,3.9));
#1903=VERTEX_POINT('',#1902);
#1904=EDGE_CURVE('E1325',#1903,#1853,#1901,.T.);
#1905=ORIENTED_EDGE('',*,*,#1904,.F.);
#1906=CARTESIAN_POINT('',(2.6,4.15,4.));
#1907=DIRECTION('',(1.,0.,0.));
#1908=DIRECTION('',(0.,0.,-1.));
#1909=AXIS2_PLACEMENT_3D('',#1906,#1907,#1908);
#1910=CIRCLE('',#1909,0.1);
#1911=EDGE_CURVE('E1483',#912,#1903,#1910,.T.);
#1912=ORIENTED_EDGE('',*,*,#1911,.F.);
#1913=ORIENTED_EDGE('',*,*,#913,.F.);
#1914=EDGE_LOOP('',(#1897,#1905,#1912,#1913));
#1915=FACE_BOUND('',#1914,.T.);
#1916=ADVANCED_FACE('F2711',(#1915),#1896,.F.);
#1917=CARTESIAN_POINT('',(2.6,4.15,-3.8));
#1918=DIRECTION('',(0.,1.,0.));
#1919=DIRECTION('',(0.,0.,1.));
#1920=AXIS2_PLACEMENT_3D('',#1917,#1918,#1919);
#1921=TOROIDAL_SURFACE('',#1920,0.2,0.1);
#1922=ORIENTED_EDGE('',*,*,#1881,.T.);
#1923=ORIENTED_EDGE('',*,*,#939,.T.);
#1924=CARTESIAN_POINT('',(2.4,4.15,-3.8));
#1925=DIRECTION('',(0.,0.,1.));
#1926=DIRECTION('',(1.,0.,0.));
#1927=AXIS2_PLACEMENT_3D('',#1924,#1925,#1926);
#1928=CIRCLE('',#1927,0.1);
#1929=CARTESIAN_POINT('',(2.5,4.15,-3.8));
#1930=VERTEX_POINT('',#1929);
#1931=EDGE_CURVE('E1479',#1930,#929,#1928,.F.);
#1932=ORIENTED_EDGE('',*,*,#1931,.F.);
#1933=CARTESIAN_POINT('',(2.6,4.15,-3.8));
#1934=DIRECTION('',(0.,1.,0.));
#1935=DIRECTION('',(0.,0.,1.));
#1936=AXIS2_PLACEMENT_3D('',#1933,#1934,#1935);
#1937=CIRCLE('',#1936,0.1);
#1938=EDGE_CURVE('E1491',#1930,#1880,#1937,.F.);
#1939=ORIENTED_EDGE('',*,*,#1938,.T.);
#1940=EDGE_LOOP('',(#1922,#1923,#1932,#1939));
#1941=FACE_BOUND('',#1940,.T.);
#1942=ADVANCED_FACE('F2702',(#1941),#1921,.F.);
#1943=CARTESIAN_POINT('',(2.6,4.15,3.8));
#1944=DIRECTION('',(0.,1.,0.));
#1945=DIRECTION('',(0.,0.,1.));
#1946=AXIS2_PLACEMENT_3D('',#1943,#1944,#1945);
#1947=TOROIDAL_SURFACE('',#1946,0.2,0.1);
#1948=ORIENTED_EDGE('',*,*,#1911,.T.);
#1949=CARTESIAN_POINT('',(2.6,4.15,3.8));
#1950=DIRECTION('',(0.,1.,0.));
#1951=DIRECTION('',(0.,0.,1.));
#1952=AXIS2_PLACEMENT_3D('',#1949,#1950,#1951);
#1953=CIRCLE('',#1952,0.1);
#1954=CARTESIAN_POINT('',(2.5,4.15,3.8));
#1955=VERTEX_POINT('',#1954);
#1956=EDGE_CURVE('E1487',#1903,#1955,#1953,.F.);
#1957=ORIENTED_EDGE('',*,*,#1956,.T.);
#1958=CARTESIAN_POINT('',(2.4,4.15,3.8));
#1959=DIRECTION('',(0.,0.,-1.));
#1960=DIRECTION('',(-1.,0.,0.));
#1961=AXIS2_PLACEMENT_3D('',#1958,#1959,#1960);
#1962=CIRCLE('',#1961,0.1);
#1963=EDGE_CURVE('E1475',#921,#1955,#1962,.F.);
#1964=ORIENTED_EDGE('',*,*,#1963,.F.);
#1965=ORIENTED_EDGE('',*,*,#922,.T.);
#1966=EDGE_LOOP('',(#1948,#1957,#1964,#1965));
#1967=FACE_BOUND('',#1966,.T.);
#1968=ADVANCED_FACE('F2693',(#1967),#1947,.F.);
#1969=CARTESIAN_POINT('',(2.4,4.15,0.));
#1970=DIRECTION('',(0.,0.,-1.));
#1971=DIRECTION('',(-1.,0.,0.));
#1972=AXIS2_PLACEMENT_3D('',#1969,#1970,#1971);
#1973=CYLINDRICAL_SURFACE('',#1972,0.1);
#1974=ORIENTED_EDGE('',*,*,#1931,.T.);
#1975=ORIENTED_EDGE('',*,*,#930,.F.);
#1976=ORIENTED_EDGE('',*,*,#1963,.T.);
#1977=DIRECTION('',(0.,0.,1.));
#1978=VECTOR('',#1977,1.);
#1979=CARTESIAN_POINT('',(2.5,4.15,3.9));
#1980=LINE('',#1979,#1978);
#1981=EDGE_CURVE('E1321',#1930,#1955,#1980,.T.);
#1982=ORIENTED_EDGE('',*,*,#1981,.F.);
#1983=EDGE_LOOP('',(#1974,#1975,#1976,#1982));
#1984=FACE_BOUND('',#1983,.T.);
#1985=ADVANCED_FACE('F2684',(#1984),#1973,.F.);
#1986=CARTESIAN_POINT('',(1.1,4.15,-3.8));
#1987=DIRECTION('',(0.,1.,0.));
#1988=DIRECTION('',(0.,0.,1.));
#1989=AXIS2_PLACEMENT_3D('',#1986,#1987,#1988);
#1990=TOROIDAL_SURFACE('',#1989,0.2,0.1);
#1991=CARTESIAN_POINT('',(1.3,4.15,-3.8));
#1992=DIRECTION('',(0.,0.,1.));
#1993=DIRECTION('',(1.,0.,0.));
#1994=AXIS2_PLACEMENT_3D('',#1991,#1992,#1993);
#1995=CIRCLE('',#1994,0.1);
#1996=CARTESIAN_POINT('',(1.2,4.15,-3.8));
#1997=VERTEX_POINT('',#1996);
#1998=EDGE_CURVE('E1540',#972,#1997,#1995,.F.);
#1999=ORIENTED_EDGE('',*,*,#1998,.F.);
#2000=ORIENTED_EDGE('',*,*,#975,.T.);
#2001=CARTESIAN_POINT('',(1.1,4.15,-4.));
#2002=DIRECTION('',(-1.,0.,0.));
#2003=DIRECTION('',(0.,0.,1.));
#2004=AXIS2_PLACEMENT_3D('',#2001,#2002,#2003);
#2005=CIRCLE('',#2004,0.1);
#2006=CARTESIAN_POINT('',(1.1,4.15,-3.9));
#2007=VERTEX_POINT('',#2006);
#2008=EDGE_CURVE('E1544',#2007,#974,#2005,.F.);
#2009=ORIENTED_EDGE('',*,*,#2008,.F.);
#2010=CARTESIAN_POINT('',(1.1,4.15,-3.8));
#2011=DIRECTION('',(0.,1.,0.));
#2012=DIRECTION('',(0.,0.,1.));
#2013=AXIS2_PLACEMENT_3D('',#2010,#2011,#2012);
#2014=CIRCLE('',#2013,0.1);
#2015=EDGE_CURVE('E1480',#2007,#1997,#2014,.F.);
#2016=ORIENTED_EDGE('',*,*,#2015,.T.);
#2017=EDGE_LOOP('',(#1999,#2000,#2009,#2016));
#2018=FACE_BOUND('',#2017,.T.);
#2019=ADVANCED_FACE('F2675',(#2018),#1990,.F.);
#2020=CARTESIAN_POINT('',(0.,4.15,-4.));
#2021=DIRECTION('',(1.,0.,0.));
#2022=DIRECTION('',(0.,0.,-1.));
#2023=AXIS2_PLACEMENT_3D('',#2020,#2021,#2022);
#2024=CYLINDRICAL_SURFACE('',#2023,0.1);
#2025=ORIENTED_EDGE('',*,*,#2008,.T.);
#2026=ORIENTED_EDGE('',*,*,#1015,.F.);
#2027=CARTESIAN_POINT('',(0.,4.15,-4.));
#2028=DIRECTION('',(1.,0.,0.));
#2029=DIRECTION('',(0.,0.,-1.));
#2030=AXIS2_PLACEMENT_3D('',#2027,#2028,#2029);
#2031=CIRCLE('',#2030,0.1);
#2032=CARTESIAN_POINT('',(0.,4.15,-3.9));
#2033=VERTEX_POINT('',#2032);
#2034=EDGE_CURVE('E1536',#2033,#1008,#2031,.T.);
#2035=ORIENTED_EDGE('',*,*,#2034,.F.);
#2036=DIRECTION('',(1.,0.,0.));
#2037=VECTOR('',#2036,1.);
#2038=CARTESIAN_POINT('',(0.,4.15,-3.9));
#2039=LINE('',#2038,#2037);
#2040=EDGE_CURVE('E1345',#2007,#2033,#2039,.F.);
#2041=ORIENTED_EDGE('',*,*,#2040,.F.);
#2042=EDGE_LOOP('',(#2025,#2026,#2035,#2041));
#2043=FACE_BOUND('',#2042,.T.);
#2044=ADVANCED_FACE('F2666',(#2043),#2024,.F.);
#2045=CARTESIAN_POINT('',(1.3,4.15,0.));
#2046=DIRECTION('',(0.,0.,1.));
#2047=DIRECTION('',(1.,0.,0.));
#2048=AXIS2_PLACEMENT_3D('',#2045,#2046,#2047);
#2049=CYLINDRICAL_SURFACE('',#2048,0.1);
#2050=ORIENTED_EDGE('',*,*,#1998,.T.);
#2051=DIRECTION('',(0.,0.,1.));
#2052=VECTOR('',#2051,1.);
#2053=CARTESIAN_POINT('',(1.2,4.15,0.));
#2054=LINE('',#2053,#2052);
#2055=CARTESIAN_POINT('',(1.2,4.15,3.8));
#2056=VERTEX_POINT('',#2055);
#2057=EDGE_CURVE('E1341',#2056,#1997,#2054,.F.);
#2058=ORIENTED_EDGE('',*,*,#2057,.F.);
#2059=CARTESIAN_POINT('',(1.3,4.15,3.8));
#2060=DIRECTION('',(0.,0.,-1.));
#2061=DIRECTION('',(-1.,0.,0.));
#2062=AXIS2_PLACEMENT_3D('',#2059,#2060,#2061);
#2063=CIRCLE('',#2062,0.1);
#2064=EDGE_CURVE('E1528',#982,#2056,#2063,.T.);
#2065=ORIENTED_EDGE('',*,*,#2064,.F.);
#2066=ORIENTED_EDGE('',*,*,#983,.F.);
#2067=EDGE_LOOP('',(#2050,#2058,#2065,#2066));
#2068=FACE_BOUND('',#2067,.T.);
#2069=ADVANCED_FACE('F2657',(#2068),#2049,.F.);
#2070=CARTESIAN_POINT('',(0.,4.15,0.));
#2071=DIRECTION('',(0.,1.,0.));
#2072=DIRECTION('',(0.,0.,1.));
#2073=AXIS2_PLACEMENT_3D('',#2070,#2071,#2072);
#2074=TOROIDAL_SURFACE('',#2073,4.,0.1);
#2075=ORIENTED_EDGE('',*,*,#2034,.T.);
#2076=ORIENTED_EDGE('',*,*,#1009,.F.);
#2077=CARTESIAN_POINT('',(0.,4.15,4.));
#2078=DIRECTION('',(-1.,0.,0.));
#2079=DIRECTION('',(0.,0.,1.));
#2080=AXIS2_PLACEMENT_3D('',#2077,#2078,#2079);
#2081=CIRCLE('',#2080,0.1);
#2082=CARTESIAN_POINT('',(0.,4.15,3.9));
#2083=VERTEX_POINT('',#2082);
#2084=EDGE_CURVE('E1524',#2083,#999,#2081,.T.);
#2085=ORIENTED_EDGE('',*,*,#2084,.F.);
#2086=CARTESIAN_POINT('',(0.,4.15,0.));
#2087=DIRECTION('',(0.,1.,0.));
#2088=DIRECTION('',(0.,0.,1.));
#2089=AXIS2_PLACEMENT_3D('',#2086,#2087,#2088);
#2090=CIRCLE('',#2089,3.9);
#2091=EDGE_CURVE('E1349',#2033,#2083,#2090,.T.);
#2092=ORIENTED_EDGE('',*,*,#2091,.F.);
#2093=EDGE_LOOP('',(#2075,#2076,#2085,#2092));
#2094=FACE_BOUND('',#2093,.T.);
#2095=ADVANCED_FACE('F2648',(#2094),#2074,.F.);
#2096=CARTESIAN_POINT('',(1.1,4.15,3.8));
#2097=DIRECTION('',(0.,1.,0.));
#2098=DIRECTION('',(0.,0.,1.));
#2099=AXIS2_PLACEMENT_3D('',#2096,#2097,#2098);
#2100=TOROIDAL_SURFACE('',#2099,0.2,0.1);
#2101=ORIENTED_EDGE('',*,*,#2064,.T.);
#2102=CARTESIAN_POINT('',(1.1,4.15,3.8));
#2103=DIRECTION('',(0.,1.,0.));
#2104=DIRECTION('',(0.,0.,1.));
#2105=AXIS2_PLACEMENT_3D('',#2102,#2103,#2104);
#2106=CIRCLE('',#2105,0.1);
#2107=CARTESIAN_POINT('',(1.1,4.15,3.9));
#2108=VERTEX_POINT('',#2107);
#2109=EDGE_CURVE('E1532',#2056,#2108,#2106,.F.);
#2110=ORIENTED_EDGE('',*,*,#2109,.T.);
#2111=CARTESIAN_POINT('',(1.1,4.15,4.));
#2112=DIRECTION('',(-1.,0.,0.));
#2113=DIRECTION('',(0.,0.,1.));
#2114=AXIS2_PLACEMENT_3D('',#2111,#2112,#2113);
#2115=CIRCLE('',#2114,0.1);
#2116=EDGE_CURVE('E1521',#991,#2108,#2115,.F.);
#2117=ORIENTED_EDGE('',*,*,#2116,.F.);
#2118=ORIENTED_EDGE('',*,*,#992,.T.);
#2119=EDGE_LOOP('',(#2101,#2110,#2117,#2118));
#2120=FACE_BOUND('',#2119,.T.);
#2121=ADVANCED_FACE('F2639',(#2120),#2100,.F.);
#2122=CARTESIAN_POINT('',(0.,4.15,4.));
#2123=DIRECTION('',(-1.,0.,0.));
#2124=DIRECTION('',(0.,0.,1.));
#2125=AXIS2_PLACEMENT_3D('',#2122,#2123,#2124);
#2126=CYLINDRICAL_SURFACE('',#2125,0.1);
#2127=ORIENTED_EDGE('',*,*,#2084,.T.);
#2128=ORIENTED_EDGE('',*,*,#1000,.F.);
#2129=ORIENTED_EDGE('',*,*,#2116,.T.);
#2130=DIRECTION('',(1.,0.,0.));
#2131=VECTOR('',#2130,1.);
#2132=CARTESIAN_POINT('',(1.2,4.15,3.9));
#2133=LINE('',#2132,#2131);
#2134=EDGE_CURVE('E1337',#2083,#2108,#2133,.T.);
#2135=ORIENTED_EDGE('',*,*,#2134,.F.);
#2136=EDGE_LOOP('',(#2127,#2128,#2129,#2135));
#2137=FACE_BOUND('',#2136,.T.);
#2138=ADVANCED_FACE('F2036',(#2137),#2126,.F.);
#2139=CARTESIAN_POINT('',(7.9,4.15,0.));
#2140=DIRECTION('',(0.,0.,-1.));
#2141=DIRECTION('',(-1.,0.,0.));
#2142=AXIS2_PLACEMENT_3D('',#2139,#2140,#2141);
#2143=CYLINDRICAL_SURFACE('',#2142,0.1);
#2144=CARTESIAN_POINT('',(7.9,4.15,3.8));
#2145=DIRECTION('',(0.,0.,1.));
#2146=DIRECTION('',(1.,0.,0.));
#2147=AXIS2_PLACEMENT_3D('',#2144,#2145,#2146);
#2148=CIRCLE('',#2147,0.1);
#2149=EDGE_CURVE('E1525',#1374,#1074,#2148,.T.);
#2150=ORIENTED_EDGE('',*,*,#2149,.F.);
#2151=ORIENTED_EDGE('',*,*,#1405,.T.);
#2152=ORIENTED_EDGE('',*,*,#566,.F.);
#2153=ORIENTED_EDGE('',*,*,#1081,.F.);
#2154=EDGE_LOOP('',(#2150,#2151,#2152,#2153));
#2155=FACE_BOUND('',#2154,.T.);
#2156=ADVANCED_FACE('F2006',(#2155),#2143,.T.);
#2157=CARTESIAN_POINT('',(7.9,4.15,3.8));
#2158=DIRECTION('',(0.,1.,0.));
#2159=DIRECTION('',(0.,0.,1.));
#2160=AXIS2_PLACEMENT_3D('',#2157,#2158,#2159);
#2161=SPHERICAL_SURFACE('',#2160,0.1);
#2162=ORIENTED_EDGE('',*,*,#1382,.F.);
#2163=ORIENTED_EDGE('',*,*,#2149,.T.);
#2164=CARTESIAN_POINT('',(7.9,4.15,3.8));
#2165=DIRECTION('',(-1.,0.,0.));
#2166=DIRECTION('',(0.,0.,1.));
#2167=AXIS2_PLACEMENT_3D('',#2164,#2165,#2166);
#2168=CIRCLE('',#2167,0.1);
#2169=EDGE_CURVE('E1632',#1364,#1074,#2168,.T.);
#2170=ORIENTED_EDGE('',*,*,#2169,.F.);
#2171=EDGE_LOOP('',(#2162,#2163,#2170));
#2172=FACE_BOUND('',#2171,.T.);
#2173=ADVANCED_FACE('F2028',(#2172),#2161,.T.);
#2174=CARTESIAN_POINT('',(0.,4.15,3.8));
#2175=DIRECTION('',(1.,0.,0.));
#2176=DIRECTION('',(0.,0.,-1.));
#2177=AXIS2_PLACEMENT_3D('',#2174,#2175,#2176);
#2178=CYLINDRICAL_SURFACE('',#2177,0.1);
#2179=CARTESIAN_POINT('',(7.7,4.15,3.8));
#2180=DIRECTION('',(-1.,0.,0.));
#2181=DIRECTION('',(0.,0.,1.));
#2182=AXIS2_PLACEMENT_3D('',#2179,#2180,#2181);
#2183=CIRCLE('',#2182,0.1);
#2184=EDGE_CURVE('E1627',#1421,#1066,#2183,.T.);
#2185=ORIENTED_EDGE('',*,*,#2184,.F.);
#2186=ORIENTED_EDGE('',*,*,#1422,.T.);
#2187=ORIENTED_EDGE('',*,*,#2169,.T.);
#2188=ORIENTED_EDGE('',*,*,#1075,.F.);
#2189=EDGE_LOOP('',(#2185,#2186,#2187,#2188));
#2190=FACE_BOUND('',#2189,.T.);
#2191=ADVANCED_FACE('F2026',(#2190),#2178,.T.);
#2192=CARTESIAN_POINT('',(7.7,4.15,3.8));
#2193=DIRECTION('',(0.,1.,0.));
#2194=DIRECTION('',(0.,0.,1.));
#2195=AXIS2_PLACEMENT_3D('',#2192,#2193,#2194);
#2196=SPHERICAL_SURFACE('',#2195,0.1);
#2197=ORIENTED_EDGE('',*,*,#1466,.F.);
#2198=ORIENTED_EDGE('',*,*,#2184,.T.);
#2199=CARTESIAN_POINT('',(7.7,4.15,3.8));
#2200=DIRECTION('',(0.,0.,-1.));
#2201=DIRECTION('',(-1.,0.,0.));
#2202=AXIS2_PLACEMENT_3D('',#2199,#2200,#2201);
#2203=CIRCLE('',#2202,0.1);
#2204=EDGE_CURVE('E1624',#1465,#1066,#2203,.T.);
#2205=ORIENTED_EDGE('',*,*,#2204,.F.);
#2206=EDGE_LOOP('',(#2197,#2198,#2205));
#2207=FACE_BOUND('',#2206,.T.);
#2208=ADVANCED_FACE('F2024',(#2207),#2196,.T.);
#2209=CARTESIAN_POINT('',(7.7,4.15,0.));
#2210=DIRECTION('',(0.,0.,1.));
#2211=DIRECTION('',(1.,0.,0.));
#2212=AXIS2_PLACEMENT_3D('',#2209,#2210,#2211);
#2213=CYLINDRICAL_SURFACE('',#2212,0.1);
#2214=ORIENTED_EDGE('',*,*,#551,.F.);
#2215=ORIENTED_EDGE('',*,*,#1491,.T.);
#2216=ORIENTED_EDGE('',*,*,#2204,.T.);
#2217=ORIENTED_EDGE('',*,*,#1067,.F.);
#2218=EDGE_LOOP('',(#2214,#2215,#2216,#2217));
#2219=FACE_BOUND('',#2218,.T.);
#2220=ADVANCED_FACE('F2001',(#2219),#2213,.T.);
#2221=CARTESIAN_POINT('',(6.2,4.15,0.));
#2222=DIRECTION('',(0.,0.,-1.));
#2223=DIRECTION('',(-1.,0.,0.));
#2224=AXIS2_PLACEMENT_3D('',#2221,#2222,#2223);
#2225=CYLINDRICAL_SURFACE('',#2224,0.1);
#2226=CARTESIAN_POINT('',(6.2,4.15,3.8));
#2227=DIRECTION('',(0.,0.,1.));
#2228=DIRECTION('',(1.,0.,0.));
#2229=AXIS2_PLACEMENT_3D('',#2226,#2227,#2228);
#2230=CIRCLE('',#2229,0.1);
#2231=EDGE_CURVE('E1628',#1517,#1197,#2230,.T.);
#2232=ORIENTED_EDGE('',*,*,#2231,.F.);
#2233=ORIENTED_EDGE('',*,*,#1548,.T.);
#2234=ORIENTED_EDGE('',*,*,#608,.F.);
#2235=ORIENTED_EDGE('',*,*,#1204,.F.);
#2236=EDGE_LOOP('',(#2232,#2233,#2234,#2235));
#2237=FACE_BOUND('',#2236,.T.);
#2238=ADVANCED_FACE('F2056',(#2237),#2225,.T.);
#2239=CARTESIAN_POINT('',(6.2,4.15,3.8));
#2240=DIRECTION('',(0.,1.,0.));
#2241=DIRECTION('',(0.,0.,1.));
#2242=AXIS2_PLACEMENT_3D('',#2239,#2240,#2241);
#2243=SPHERICAL_SURFACE('',#2242,0.1);
#2244=ORIENTED_EDGE('',*,*,#1525,.F.);
#2245=ORIENTED_EDGE('',*,*,#2231,.T.);
#2246=CARTESIAN_POINT('',(6.2,4.15,3.8));
#2247=DIRECTION('',(-1.,0.,0.));
#2248=DIRECTION('',(0.,0.,1.));
#2249=AXIS2_PLACEMENT_3D('',#2246,#2247,#2248);
#2250=CIRCLE('',#2249,0.1);
#2251=EDGE_CURVE('E1647',#1507,#1197,#2250,.T.);
#2252=ORIENTED_EDGE('',*,*,#2251,.F.);
#2253=EDGE_LOOP('',(#2244,#2245,#2252));
#2254=FACE_BOUND('',#2253,.T.);
#2255=ADVANCED_FACE('F2052',(#2254),#2243,.T.);
#2256=CARTESIAN_POINT('',(0.,4.15,3.8));
#2257=DIRECTION('',(1.,0.,0.));
#2258=DIRECTION('',(0.,0.,-1.));
#2259=AXIS2_PLACEMENT_3D('',#2256,#2257,#2258);
#2260=CYLINDRICAL_SURFACE('',#2259,0.1);
#2261=CARTESIAN_POINT('',(6.,4.15,3.8));
#2262=DIRECTION('',(-1.,0.,0.));
#2263=DIRECTION('',(0.,0.,1.));
#2264=AXIS2_PLACEMENT_3D('',#2261,#2262,#2263);
#2265=CIRCLE('',#2264,0.1);
#2266=EDGE_CURVE('E1642',#1564,#1189,#2265,.T.);
#2267=ORIENTED_EDGE('',*,*,#2266,.F.);
#2268=ORIENTED_EDGE('',*,*,#1565,.T.);
#2269=ORIENTED_EDGE('',*,*,#2251,.T.);
#2270=ORIENTED_EDGE('',*,*,#1198,.F.);
#2271=EDGE_LOOP('',(#2267,#2268,#2269,#2270));
#2272=FACE_BOUND('',#2271,.T.);
#2273=ADVANCED_FACE('F2048',(#2272),#2260,.T.);
#2274=CARTESIAN_POINT('',(6.,4.15,3.8));
#2275=DIRECTION('',(0.,1.,0.));
#2276=DIRECTION('',(0.,0.,1.));
#2277=AXIS2_PLACEMENT_3D('',#2274,#2275,#2276);
#2278=SPHERICAL_SURFACE('',#2277,0.1);
#2279=ORIENTED_EDGE('',*,*,#1609,.F.);
#2280=ORIENTED_EDGE('',*,*,#2266,.T.);
#2281=CARTESIAN_POINT('',(6.,4.15,3.8));
#2282=DIRECTION('',(0.,0.,-1.));
#2283=DIRECTION('',(-1.,0.,0.));
#2284=AXIS2_PLACEMENT_3D('',#2281,#2282,#2283);
#2285=CIRCLE('',#2284,0.1);
#2286=EDGE_CURVE('E1639',#1608,#1189,#2285,.T.);
#2287=ORIENTED_EDGE('',*,*,#2286,.F.);
#2288=EDGE_LOOP('',(#2279,#2280,#2287));
#2289=FACE_BOUND('',#2288,.T.);
#2290=ADVANCED_FACE('F2044',(#2289),#2278,.T.);
#2291=CARTESIAN_POINT('',(6.,4.15,0.));
#2292=DIRECTION('',(0.,0.,1.));
#2293=DIRECTION('',(1.,0.,0.));
#2294=AXIS2_PLACEMENT_3D('',#2291,#2292,#2293);
#2295=CYLINDRICAL_SURFACE('',#2294,0.1);
#2296=ORIENTED_EDGE('',*,*,#593,.F.);
#2297=ORIENTED_EDGE('',*,*,#1634,.T.);
#2298=ORIENTED_EDGE('',*,*,#2286,.T.);
#2299=ORIENTED_EDGE('',*,*,#1190,.F.);
#2300=EDGE_LOOP('',(#2296,#2297,#2298,#2299));
#2301=FACE_BOUND('',#2300,.T.);
#2302=ADVANCED_FACE('F2040',(#2301),#2295,.T.);
#2303=CARTESIAN_POINT('',(4.5,4.15,0.));
#2304=DIRECTION('',(0.,0.,-1.));
#2305=DIRECTION('',(-1.,0.,0.));
#2306=AXIS2_PLACEMENT_3D('',#2303,#2304,#2305);
#2307=CYLINDRICAL_SURFACE('',#2306,0.1);
#2308=CARTESIAN_POINT('',(4.5,4.15,3.8));
#2309=DIRECTION('',(0.,0.,1.));
#2310=DIRECTION('',(1.,0.,0.));
#2311=AXIS2_PLACEMENT_3D('',#2308,#2309,#2310);
#2312=CIRCLE('',#2311,0.1);
#2313=EDGE_CURVE('E1643',#1660,#1171,#2312,.T.);
#2314=ORIENTED_EDGE('',*,*,#2313,.F.);
#2315=ORIENTED_EDGE('',*,*,#1691,.T.);
#2316=ORIENTED_EDGE('',*,*,#650,.F.);
#2317=ORIENTED_EDGE('',*,*,#1178,.F.);
#2318=EDGE_LOOP('',(#2314,#2315,#2316,#2317));
#2319=FACE_BOUND('',#2318,.T.);
#2320=ADVANCED_FACE('F2043',(#2319),#2307,.T.);
#2321=CARTESIAN_POINT('',(4.5,4.15,3.8));
#2322=DIRECTION('',(0.,1.,0.));
#2323=DIRECTION('',(0.,0.,1.));
#2324=AXIS2_PLACEMENT_3D('',#2321,#2322,#2323);
#2325=SPHERICAL_SURFACE('',#2324,0.1);
#2326=ORIENTED_EDGE('',*,*,#1668,.F.);
#2327=ORIENTED_EDGE('',*,*,#2313,.T.);
#2328=CARTESIAN_POINT('',(4.5,4.15,3.8));
#2329=DIRECTION('',(-1.,0.,0.));
#2330=DIRECTION('',(0.,0.,1.));
#2331=AXIS2_PLACEMENT_3D('',#2328,#2329,#2330);
#2332=CIRCLE('',#2331,0.1);
#2333=EDGE_CURVE('E1662',#1650,#1171,#2332,.T.);
#2334=ORIENTED_EDGE('',*,*,#2333,.F.);
#2335=EDGE_LOOP('',(#2326,#2327,#2334));
#2336=FACE_BOUND('',#2335,.T.);
#2337=ADVANCED_FACE('F2073',(#2336),#2325,.T.);
#2338=CARTESIAN_POINT('',(0.,4.15,3.8));
#2339=DIRECTION('',(1.,0.,0.));
#2340=DIRECTION('',(0.,0.,-1.));
#2341=AXIS2_PLACEMENT_3D('',#2338,#2339,#2340);
#2342=CYLINDRICAL_SURFACE('',#2341,0.1);
#2343=CARTESIAN_POINT('',(4.3,4.15,3.8));
#2344=DIRECTION('',(-1.,0.,0.));
#2345=DIRECTION('',(0.,0.,1.));
#2346=AXIS2_PLACEMENT_3D('',#2343,#2344,#2345);
#2347=CIRCLE('',#2346,0.1);
#2348=EDGE_CURVE('E1657',#1707,#1163,#2347,.T.);
#2349=ORIENTED_EDGE('',*,*,#2348,.F.);
#2350=ORIENTED_EDGE('',*,*,#1708,.T.);
#2351=ORIENTED_EDGE('',*,*,#2333,.T.);
#2352=ORIENTED_EDGE('',*,*,#1172,.F.);
#2353=EDGE_LOOP('',(#2349,#2350,#2351,#2352));
#2354=FACE_BOUND('',#2353,.T.);
#2355=ADVANCED_FACE('F2069',(#2354),#2342,.T.);
#2356=CARTESIAN_POINT('',(4.3,4.15,3.8));
#2357=DIRECTION('',(0.,1.,0.));
#2358=DIRECTION('',(0.,0.,1.));
#2359=AXIS2_PLACEMENT_3D('',#2356,#2357,#2358);
#2360=SPHERICAL_SURFACE('',#2359,0.1);
#2361=ORIENTED_EDGE('',*,*,#1752,.F.);
#2362=ORIENTED_EDGE('',*,*,#2348,.T.);
#2363=CARTESIAN_POINT('',(4.3,4.15,3.8));
#2364=DIRECTION('',(0.,0.,-1.));
#2365=DIRECTION('',(-1.,0.,0.));
#2366=AXIS2_PLACEMENT_3D('',#2363,#2364,#2365);
#2367=CIRCLE('',#2366,0.1);
#2368=EDGE_CURVE('E1654',#1751,#1163,#2367,.T.);
#2369=ORIENTED_EDGE('',*,*,#2368,.F.);
#2370=EDGE_LOOP('',(#2361,#2362,#2369));
#2371=FACE_BOUND('',#2370,.T.);
#2372=ADVANCED_FACE('F2065',(#2371),#2360,.T.);
#2373=CARTESIAN_POINT('',(4.3,4.15,0.));
#2374=DIRECTION('',(0.,0.,1.));
#2375=DIRECTION('',(1.,0.,0.));
#2376=AXIS2_PLACEMENT_3D('',#2373,#2374,#2375);
#2377=CYLINDRICAL_SURFACE('',#2376,0.1);
#2378=ORIENTED_EDGE('',*,*,#635,.F.);
#2379=ORIENTED_EDGE('',*,*,#1777,.T.);
#2380=ORIENTED_EDGE('',*,*,#2368,.T.);
#2381=ORIENTED_EDGE('',*,*,#1164,.F.);
#2382=EDGE_LOOP('',(#2378,#2379,#2380,#2381));
#2383=FACE_BOUND('',#2382,.T.);
#2384=ADVANCED_FACE('F2061',(#2383),#2377,.T.);
#2385=CARTESIAN_POINT('',(2.8,4.15,-3.8));
#2386=DIRECTION('',(0.,1.,0.));
#2387=DIRECTION('',(0.,0.,1.));
#2388=AXIS2_PLACEMENT_3D('',#2385,#2386,#2387);
#2389=SPHERICAL_SURFACE('',#2388,0.1);
#2390=CARTESIAN_POINT('',(2.8,4.15,-3.8));
#2391=DIRECTION('',(0.,0.,1.));
#2392=DIRECTION('',(1.,0.,0.));
#2393=AXIS2_PLACEMENT_3D('',#2390,#2391,#2392);
#2394=CIRCLE('',#2393,0.1);
#2395=EDGE_CURVE('E1692',#1803,#1127,#2394,.T.);
#2396=ORIENTED_EDGE('',*,*,#2395,.F.);
#2397=ORIENTED_EDGE('',*,*,#1836,.F.);
#2398=CARTESIAN_POINT('',(2.8,4.15,-3.8));
#2399=DIRECTION('',(-1.,0.,0.));
#2400=DIRECTION('',(0.,0.,1.));
#2401=AXIS2_PLACEMENT_3D('',#2398,#2399,#2400);
#2402=CIRCLE('',#2401,0.1);
#2403=EDGE_CURVE('E1658',#1127,#1828,#2402,.T.);
#2404=ORIENTED_EDGE('',*,*,#2403,.F.);
#2405=EDGE_LOOP('',(#2396,#2397,#2404));
#2406=FACE_BOUND('',#2405,.T.);
#2407=ADVANCED_FACE('F2064',(#2406),#2389,.T.);
#2408=CARTESIAN_POINT('',(0.,4.15,-3.8));
#2409=DIRECTION('',(-1.,0.,0.));
#2410=DIRECTION('',(0.,0.,1.));
#2411=AXIS2_PLACEMENT_3D('',#2408,#2409,#2410);
#2412=CYLINDRICAL_SURFACE('',#2411,0.1);
#2413=ORIENTED_EDGE('',*,*,#2403,.T.);
#2414=ORIENTED_EDGE('',*,*,#1887,.T.);
#2415=CARTESIAN_POINT('',(2.6,4.15,-3.8));
#2416=DIRECTION('',(-1.,0.,0.));
#2417=DIRECTION('',(0.,0.,1.));
#2418=AXIS2_PLACEMENT_3D('',#2415,#2416,#2417);
#2419=CIRCLE('',#2418,0.1);
#2420=EDGE_CURVE('E1688',#1129,#1880,#2419,.T.);
#2421=ORIENTED_EDGE('',*,*,#2420,.F.);
#2422=ORIENTED_EDGE('',*,*,#1130,.F.);
#2423=EDGE_LOOP('',(#2413,#2414,#2421,#2422));
#2424=FACE_BOUND('',#2423,.T.);
#2425=ADVANCED_FACE('F2105',(#2424),#2412,.T.);
#2426=CARTESIAN_POINT('',(2.8,4.15,0.));
#2427=DIRECTION('',(0.,0.,-1.));
#2428=DIRECTION('',(-1.,0.,0.));
#2429=AXIS2_PLACEMENT_3D('',#2426,#2427,#2428);
#2430=CYLINDRICAL_SURFACE('',#2429,0.1);
#2431=ORIENTED_EDGE('',*,*,#2395,.T.);
#2432=ORIENTED_EDGE('',*,*,#1152,.F.);
#2433=CARTESIAN_POINT('',(2.8,4.15,3.8));
#2434=DIRECTION('',(0.,0.,1.));
#2435=DIRECTION('',(1.,0.,0.));
#2436=AXIS2_PLACEMENT_3D('',#2433,#2434,#2435);
#2437=CIRCLE('',#2436,0.1);
#2438=EDGE_CURVE('E1684',#1793,#1145,#2437,.T.);
#2439=ORIENTED_EDGE('',*,*,#2438,.F.);
#2440=ORIENTED_EDGE('',*,*,#1810,.T.);
#2441=EDGE_LOOP('',(#2431,#2432,#2439,#2440));
#2442=FACE_BOUND('',#2441,.T.);
#2443=ADVANCED_FACE('F2101',(#2442),#2430,.T.);
#2444=CARTESIAN_POINT('',(2.6,4.15,-3.8));
#2445=DIRECTION('',(0.,1.,0.));
#2446=DIRECTION('',(0.,0.,1.));
#2447=AXIS2_PLACEMENT_3D('',#2444,#2445,#2446);
#2448=SPHERICAL_SURFACE('',#2447,0.1);
#2449=ORIENTED_EDGE('',*,*,#2420,.T.);
#2450=ORIENTED_EDGE('',*,*,#1938,.F.);
#2451=CARTESIAN_POINT('',(2.6,4.15,-3.8));
#2452=DIRECTION('',(0.,0.,1.));
#2453=DIRECTION('',(1.,0.,0.));
#2454=AXIS2_PLACEMENT_3D('',#2451,#2452,#2453);
#2455=CIRCLE('',#2454,0.1);
#2456=EDGE_CURVE('E1680',#1129,#1930,#2455,.T.);
#2457=ORIENTED_EDGE('',*,*,#2456,.F.);
#2458=EDGE_LOOP('',(#2449,#2450,#2457));
#2459=FACE_BOUND('',#2458,.T.);
#2460=ADVANCED_FACE('F2097',(#2459),#2448,.T.);
#2461=CARTESIAN_POINT('',(2.8,4.15,3.8));
#2462=DIRECTION('',(0.,1.,0.));
#2463=DIRECTION('',(0.,0.,1.));
#2464=AXIS2_PLACEMENT_3D('',#2461,#2462,#2463);
#2465=SPHERICAL_SURFACE('',#2464,0.1);
#2466=ORIENTED_EDGE('',*,*,#1854,.F.);
#2467=ORIENTED_EDGE('',*,*,#2438,.T.);
#2468=CARTESIAN_POINT('',(2.8,4.15,3.8));
#2469=DIRECTION('',(-1.,0.,0.));
#2470=DIRECTION('',(0.,0.,1.));
#2471=AXIS2_PLACEMENT_3D('',#2468,#2469,#2470);
#2472=CIRCLE('',#2471,0.1);
#2473=EDGE_CURVE('E1676',#1853,#1145,#2472,.T.);
#2474=ORIENTED_EDGE('',*,*,#2473,.F.);
#2475=EDGE_LOOP('',(#2466,#2467,#2474));
#2476=FACE_BOUND('',#2475,.T.);
#2477=ADVANCED_FACE('F2093',(#2476),#2465,.T.);
#2478=CARTESIAN_POINT('',(2.6,4.15,0.));
#2479=DIRECTION('',(0.,0.,1.));
#2480=DIRECTION('',(1.,0.,0.));
#2481=AXIS2_PLACEMENT_3D('',#2478,#2479,#2480);
#2482=CYLINDRICAL_SURFACE('',#2481,0.1);
#2483=ORIENTED_EDGE('',*,*,#2456,.T.);
#2484=ORIENTED_EDGE('',*,*,#1981,.T.);
#2485=CARTESIAN_POINT('',(2.6,4.15,3.8));
#2486=DIRECTION('',(0.,0.,1.));
#2487=DIRECTION('',(1.,0.,0.));
#2488=AXIS2_PLACEMENT_3D('',#2485,#2486,#2487);
#2489=CIRCLE('',#2488,0.1);
#2490=EDGE_CURVE('E1672',#1137,#1955,#2489,.T.);
#2491=ORIENTED_EDGE('',*,*,#2490,.F.);
#2492=ORIENTED_EDGE('',*,*,#1138,.F.);
#2493=EDGE_LOOP('',(#2483,#2484,#2491,#2492));
#2494=FACE_BOUND('',#2493,.T.);
#2495=ADVANCED_FACE('F2089',(#2494),#2482,.T.);
#2496=CARTESIAN_POINT('',(0.,4.15,3.8));
#2497=DIRECTION('',(1.,0.,0.));
#2498=DIRECTION('',(0.,0.,-1.));
#2499=AXIS2_PLACEMENT_3D('',#2496,#2497,#2498);
#2500=CYLINDRICAL_SURFACE('',#2499,0.1);
#2501=ORIENTED_EDGE('',*,*,#2473,.T.);
#2502=ORIENTED_EDGE('',*,*,#1146,.F.);
#2503=CARTESIAN_POINT('',(2.6,4.15,3.8));
#2504=DIRECTION('',(-1.,0.,0.));
#2505=DIRECTION('',(0.,0.,1.));
#2506=AXIS2_PLACEMENT_3D('',#2503,#2504,#2505);
#2507=CIRCLE('',#2506,0.1);
#2508=EDGE_CURVE('E1669',#1903,#1137,#2507,.T.);
#2509=ORIENTED_EDGE('',*,*,#2508,.F.);
#2510=ORIENTED_EDGE('',*,*,#1904,.T.);
#2511=EDGE_LOOP('',(#2501,#2502,#2509,#2510));
#2512=FACE_BOUND('',#2511,.T.);
#2513=ADVANCED_FACE('F2085',(#2512),#2500,.T.);
#2514=CARTESIAN_POINT('',(2.6,4.15,3.8));
#2515=DIRECTION('',(0.,1.,0.));
#2516=DIRECTION('',(0.,0.,1.));
#2517=AXIS2_PLACEMENT_3D('',#2514,#2515,#2516);
#2518=SPHERICAL_SURFACE('',#2517,0.1);
#2519=ORIENTED_EDGE('',*,*,#2490,.T.);
#2520=ORIENTED_EDGE('',*,*,#1956,.F.);
#2521=ORIENTED_EDGE('',*,*,#2508,.T.);
#2522=EDGE_LOOP('',(#2519,#2520,#2521));
#2523=FACE_BOUND('',#2522,.T.);
#2524=ADVANCED_FACE('F2081',(#2523),#2518,.T.);
#2525=CARTESIAN_POINT('',(1.1,4.15,0.));
#2526=DIRECTION('',(0.,0.,-1.));
#2527=DIRECTION('',(-1.,0.,0.));
#2528=AXIS2_PLACEMENT_3D('',#2525,#2526,#2527);
#2529=CYLINDRICAL_SURFACE('',#2528,0.1);
#2530=CARTESIAN_POINT('',(1.1,4.15,3.8));
#2531=DIRECTION('',(0.,0.,1.));
#2532=DIRECTION('',(1.,0.,0.));
#2533=AXIS2_PLACEMENT_3D('',#2530,#2531,#2532);
#2534=CIRCLE('',#2533,0.1);
#2535=EDGE_CURVE('E1712',#2056,#1110,#2534,.T.);
#2536=ORIENTED_EDGE('',*,*,#2535,.F.);
#2537=ORIENTED_EDGE('',*,*,#2057,.T.);
#2538=CARTESIAN_POINT('',(1.1,4.15,-3.8));
#2539=DIRECTION('',(0.,0.,-1.));
#2540=DIRECTION('',(-1.,0.,0.));
#2541=AXIS2_PLACEMENT_3D('',#2538,#2539,#2540);
#2542=CIRCLE('',#2541,0.1);
#2543=EDGE_CURVE('E1673',#1091,#1997,#2542,.T.);
#2544=ORIENTED_EDGE('',*,*,#2543,.F.);
#2545=ORIENTED_EDGE('',*,*,#1117,.F.);
#2546=EDGE_LOOP('',(#2536,#2537,#2544,#2545));
#2547=FACE_BOUND('',#2546,.T.);
#2548=ADVANCED_FACE('F2084',(#2547),#2529,.T.);
#2549=CARTESIAN_POINT('',(1.1,4.15,-3.8));
#2550=DIRECTION('',(0.,1.,0.));
#2551=DIRECTION('',(0.,0.,1.));
#2552=AXIS2_PLACEMENT_3D('',#2549,#2550,#2551);
#2553=SPHERICAL_SURFACE('',#2552,0.1);
#2554=ORIENTED_EDGE('',*,*,#2543,.T.);
#2555=ORIENTED_EDGE('',*,*,#2015,.F.);
#2556=CARTESIAN_POINT('',(1.1,4.15,-3.8));
#2557=DIRECTION('',(-1.,0.,0.));
#2558=DIRECTION('',(0.,0.,1.));
#2559=AXIS2_PLACEMENT_3D('',#2556,#2557,#2558);
#2560=CIRCLE('',#2559,0.1);
#2561=EDGE_CURVE('E1708',#1091,#2007,#2560,.T.);
#2562=ORIENTED_EDGE('',*,*,#2561,.F.);
#2563=EDGE_LOOP('',(#2554,#2555,#2562));
#2564=FACE_BOUND('',#2563,.T.);
#2565=ADVANCED_FACE('F2129',(#2564),#2553,.T.);
#2566=CARTESIAN_POINT('',(1.1,4.15,3.8));
#2567=DIRECTION('',(0.,1.,0.));
#2568=DIRECTION('',(0.,0.,1.));
#2569=AXIS2_PLACEMENT_3D('',#2566,#2567,#2568);
#2570=SPHERICAL_SURFACE('',#2569,0.1);
#2571=ORIENTED_EDGE('',*,*,#2109,.F.);
#2572=ORIENTED_EDGE('',*,*,#2535,.T.);
#2573=CARTESIAN_POINT('',(1.1,4.15,3.8));
#2574=DIRECTION('',(-1.,0.,0.));
#2575=DIRECTION('',(0.,0.,1.));
#2576=AXIS2_PLACEMENT_3D('',#2573,#2574,#2575);
#2577=CIRCLE('',#2576,0.1);
#2578=EDGE_CURVE('E1704',#2108,#1110,#2577,.T.);
#2579=ORIENTED_EDGE('',*,*,#2578,.F.);
#2580=EDGE_LOOP('',(#2571,#2572,#2579));
#2581=FACE_BOUND('',#2580,.T.);
#2582=ADVANCED_FACE('F2125',(#2581),#2570,.T.);
#2583=CARTESIAN_POINT('',(0.,4.15,-3.8));
#2584=DIRECTION('',(-1.,0.,0.));
#2585=DIRECTION('',(0.,0.,1.));
#2586=AXIS2_PLACEMENT_3D('',#2583,#2584,#2585);
#2587=CYLINDRICAL_SURFACE('',#2586,0.1);
#2588=ORIENTED_EDGE('',*,*,#2561,.T.);
#2589=ORIENTED_EDGE('',*,*,#2040,.T.);
#2590=CARTESIAN_POINT('',(0.,4.15,-3.8));
#2591=DIRECTION('',(-1.,0.,0.));
#2592=DIRECTION('',(0.,0.,1.));
#2593=AXIS2_PLACEMENT_3D('',#2590,#2591,#2592);
#2594=CIRCLE('',#2593,0.1);
#2595=EDGE_CURVE('E1701',#1093,#2033,#2594,.T.);
#2596=ORIENTED_EDGE('',*,*,#2595,.F.);
#2597=ORIENTED_EDGE('',*,*,#1094,.F.);
#2598=EDGE_LOOP('',(#2588,#2589,#2596,#2597));
#2599=FACE_BOUND('',#2598,.T.);
#2600=ADVANCED_FACE('F2121',(#2599),#2587,.T.);
#2601=CARTESIAN_POINT('',(0.,4.15,3.8));
#2602=DIRECTION('',(1.,0.,0.));
#2603=DIRECTION('',(0.,0.,-1.));
#2604=AXIS2_PLACEMENT_3D('',#2601,#2602,#2603);
#2605=CYLINDRICAL_SURFACE('',#2604,0.1);
#2606=ORIENTED_EDGE('',*,*,#2578,.T.);
#2607=ORIENTED_EDGE('',*,*,#1111,.F.);
#2608=CARTESIAN_POINT('',(0.,4.15,3.8));
#2609=DIRECTION('',(-1.,0.,0.));
#2610=DIRECTION('',(0.,-1.,0.));
#2611=AXIS2_PLACEMENT_3D('',#2608,#2609,#2610);
#2612=CIRCLE('',#2611,0.1);
#2613=EDGE_CURVE('E896',#2083,#1102,#2612,.T.);
#2614=ORIENTED_EDGE('',*,*,#2613,.F.);
#2615=ORIENTED_EDGE('',*,*,#2134,.T.);
#2616=EDGE_LOOP('',(#2606,#2607,#2614,#2615));
#2617=FACE_BOUND('',#2616,.T.);
#2618=ADVANCED_FACE('F2117',(#2617),#2605,.T.);
#2619=CARTESIAN_POINT('',(0.,4.15,0.));
#2620=DIRECTION('',(0.,1.,0.));
#2621=DIRECTION('',(0.,0.,1.));
#2622=AXIS2_PLACEMENT_3D('',#2619,#2620,#2621);
#2623=TOROIDAL_SURFACE('',#2622,3.8,0.1);
#2624=ORIENTED_EDGE('',*,*,#2595,.T.);
#2625=ORIENTED_EDGE('',*,*,#2091,.T.);
#2626=ORIENTED_EDGE('',*,*,#2613,.T.);
#2627=ORIENTED_EDGE('',*,*,#1103,.F.);
#2628=EDGE_LOOP('',(#2624,#2625,#2626,#2627));
#2629=FACE_BOUND('',#2628,.T.);
#2630=ADVANCED_FACE('F2113',(#2629),#2623,.T.);
#2631=CARTESIAN_POINT('',(6.95000000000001,0.,0.));
#2632=DIRECTION('',(1.,0.,0.));
#2633=DIRECTION('',(0.,0.,-1.));
#2634=AXIS2_PLACEMENT_3D('',#2631,#2632,#2633);
#2635=PLANE('',#2634);
#2636=DIRECTION('',(0.,-1.,0.));
#2637=VECTOR('',#2636,1.);
#2638=CARTESIAN_POINT('',(6.95000000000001,0.,-7.85));
#2639=LINE('',#2638,#2637);
#2640=CARTESIAN_POINT('',(6.95000000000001,0.150000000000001,-7.85));
#2641=VERTEX_POINT('',#2640);
#2642=CARTESIAN_POINT('',(6.95000000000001,-0.150000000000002,-7.85));
#2643=VERTEX_POINT('',#2642);
#2644=EDGE_CURVE('E787',#2641,#2643,#2639,.T.);
#2645=ORIENTED_EDGE('',*,*,#2644,.F.);
#2646=CARTESIAN_POINT('',(6.95000000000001,0.150000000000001,-4.75));
#2647=DIRECTION('',(1.,0.,0.));
#2648=DIRECTION('',(0.,0.,-1.));
#2649=AXIS2_PLACEMENT_3D('',#2646,#2647,#2648);
#2650=CIRCLE('',#2649,3.1);
#2651=CARTESIAN_POINT('',(6.95000000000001,3.25,-4.75));
#2652=VERTEX_POINT('',#2651);
#2653=EDGE_CURVE('E790',#2641,#2652,#2650,.T.);
#2654=ORIENTED_EDGE('',*,*,#2653,.T.);
#2655=DIRECTION('',(0.,0.,1.));
#2656=VECTOR('',#2655,1.);
#2657=CARTESIAN_POINT('',(6.95000000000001,3.25,0.));
#2658=LINE('',#2657,#2656);
#2659=CARTESIAN_POINT('',(6.95000000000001,3.25,4.75));
#2660=VERTEX_POINT('',#2659);
#2661=EDGE_CURVE('E795',#2652,#2660,#2658,.T.);
#2662=ORIENTED_EDGE('',*,*,#2661,.T.);
#2663=CARTESIAN_POINT('',(6.95000000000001,0.150000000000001,4.75));
#2664=DIRECTION('',(1.,0.,0.));
#2665=DIRECTION('',(0.,0.,-1.));
#2666=AXIS2_PLACEMENT_3D('',#2663,#2664,#2665);
#2667=CIRCLE('',#2666,3.1);
#2668=CARTESIAN_POINT('',(6.95000000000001,0.150000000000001,7.85));
#2669=VERTEX_POINT('',#2668);
#2670=EDGE_CURVE('E799',#2660,#2669,#2667,.T.);
#2671=ORIENTED_EDGE('',*,*,#2670,.T.);
#2672=DIRECTION('',(0.,-1.,0.));
#2673=VECTOR('',#2672,1.);
#2674=CARTESIAN_POINT('',(6.95000000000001,0.,7.85));
#2675=LINE('',#2674,#2673);
#2676=CARTESIAN_POINT('',(6.95000000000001,-0.150000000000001,7.85));
#2677=VERTEX_POINT('',#2676);
#2678=EDGE_CURVE('E803',#2669,#2677,#2675,.T.);
#2679=ORIENTED_EDGE('',*,*,#2678,.T.);
#2680=CARTESIAN_POINT('',(6.95000000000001,-0.150000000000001,4.75));
#2681=DIRECTION('',(1.,0.,0.));
#2682=DIRECTION('',(0.,0.,-1.));
#2683=AXIS2_PLACEMENT_3D('',#2680,#2681,#2682);
#2684=CIRCLE('',#2683,3.1);
#2685=CARTESIAN_POINT('',(6.95000000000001,-3.25,4.75));
#2686=VERTEX_POINT('',#2685);
#2687=EDGE_CURVE('E807',#2677,#2686,#2684,.T.);
#2688=ORIENTED_EDGE('',*,*,#2687,.T.);
#2689=DIRECTION('',(0.,0.,1.));
#2690=VECTOR('',#2689,1.);
#2691=CARTESIAN_POINT('',(6.95000000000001,-3.25,0.));
#2692=LINE('',#2691,#2690);
#2693=CARTESIAN_POINT('',(6.95000000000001,-3.25,-4.75));
#2694=VERTEX_POINT('',#2693);
#2695=EDGE_CURVE('E811',#2694,#2686,#2692,.T.);
#2696=ORIENTED_EDGE('',*,*,#2695,.F.);
#2697=CARTESIAN_POINT('',(6.95000000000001,-0.150000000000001,-4.75));
#2698=DIRECTION('',(1.,0.,0.));
#2699=DIRECTION('',(0.,0.,-1.));
#2700=AXIS2_PLACEMENT_3D('',#2697,#2698,#2699);
#2701=CIRCLE('',#2700,3.1);
#2702=EDGE_CURVE('E814',#2694,#2643,#2701,.T.);
#2703=ORIENTED_EDGE('',*,*,#2702,.T.);
#2704=EDGE_LOOP('',(#2645,#2654,#2662,#2671,#2679,#2688,#2696,#2703));
#2705=FACE_BOUND('',#2704,.T.);
#2706=CARTESIAN_POINT('',(6.95000000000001,-0.150000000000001,4.75));
#2707=DIRECTION('',(1.,0.,0.));
#2708=DIRECTION('',(0.,0.,-1.));
#2709=AXIS2_PLACEMENT_3D('',#2706,#2707,#2708);
#2710=CIRCLE('',#2709,2.6);
#2711=CARTESIAN_POINT('',(6.95000000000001,-2.75,4.75));
#2712=VERTEX_POINT('',#2711);
#2713=CARTESIAN_POINT('',(6.95000000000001,-0.150000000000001,7.35));
#2714=VERTEX_POINT('',#2713);
#2715=EDGE_CURVE('E892',#2712,#2714,#2710,.F.);
#2716=ORIENTED_EDGE('',*,*,#2715,.T.);
#2717=DIRECTION('',(0.,1.,0.));
#2718=VECTOR('',#2717,1.);
#2719=CARTESIAN_POINT('',(6.95000000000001,4.25,7.35));
#2720=LINE('',#2719,#2718);
#2721=CARTESIAN_POINT('',(6.95000000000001,0.150000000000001,7.35));
#2722=VERTEX_POINT('',#2721);
#2723=EDGE_CURVE('E889',#2714,#2722,#2720,.T.);
#2724=ORIENTED_EDGE('',*,*,#2723,.T.);
#2725=CARTESIAN_POINT('',(6.95000000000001,0.150000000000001,4.75));
#2726=DIRECTION('',(1.,0.,0.));
#2727=DIRECTION('',(0.,0.,-1.));
#2728=AXIS2_PLACEMENT_3D('',#2725,#2726,#2727);
#2729=CIRCLE('',#2728,2.6);
#2730=CARTESIAN_POINT('',(6.95000000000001,2.75,4.75));
#2731=VERTEX_POINT('',#2730);
#2732=EDGE_CURVE('E879',#2722,#2731,#2729,.F.);
#2733=ORIENTED_EDGE('',*,*,#2732,.T.);
#2734=DIRECTION('',(0.,0.,-1.));
#2735=VECTOR('',#2734,1.);
#2736=CARTESIAN_POINT('',(6.95000000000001,2.75,0.));
#2737=LINE('',#2736,#2735);
#2738=CARTESIAN_POINT('',(6.95000000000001,2.75,-4.75));
#2739=VERTEX_POINT('',#2738);
#2740=EDGE_CURVE('E852',#2731,#2739,#2737,.T.);
#2741=ORIENTED_EDGE('',*,*,#2740,.T.);
#2742=CARTESIAN_POINT('',(6.95000000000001,0.150000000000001,-4.75));
#2743=DIRECTION('',(1.,0.,0.));
#2744=DIRECTION('',(0.,0.,-1.));
#2745=AXIS2_PLACEMENT_3D('',#2742,#2743,#2744);
#2746=CIRCLE('',#2745,2.6);
#2747=CARTESIAN_POINT('',(6.95000000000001,0.150000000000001,-7.35));
#2748=VERTEX_POINT('',#2747);
#2749=EDGE_CURVE('E1623',#2739,#2748,#2746,.F.);
#2750=ORIENTED_EDGE('',*,*,#2749,.T.);
#2751=DIRECTION('',(0.,-1.,0.));
#2752=VECTOR('',#2751,1.);
#2753=CARTESIAN_POINT('',(6.95000000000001,4.25,-7.35));
#2754=LINE('',#2753,#2752);
#2755=CARTESIAN_POINT('',(6.95000000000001,-0.150000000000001,-7.35));
#2756=VERTEX_POINT('',#2755);
#2757=EDGE_CURVE('E876',#2748,#2756,#2754,.T.);
#2758=ORIENTED_EDGE('',*,*,#2757,.T.);
#2759=CARTESIAN_POINT('',(6.95000000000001,-0.150000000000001,-4.75));
#2760=DIRECTION('',(1.,0.,0.));
#2761=DIRECTION('',(0.,0.,-1.));
#2762=AXIS2_PLACEMENT_3D('',#2759,#2760,#2761);
#2763=CIRCLE('',#2762,2.6);
#2764=CARTESIAN_POINT('',(6.95000000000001,-2.75,-4.75));
#2765=VERTEX_POINT('',#2764);
#2766=EDGE_CURVE('E882',#2756,#2765,#2763,.F.);
#2767=ORIENTED_EDGE('',*,*,#2766,.T.);
#2768=DIRECTION('',(0.,0.,-1.));
#2769=VECTOR('',#2768,1.);
#2770=CARTESIAN_POINT('',(6.95000000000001,-2.75,0.));
#2771=LINE('',#2770,#2769);
#2772=EDGE_CURVE('E885',#2712,#2765,#2771,.T.);
#2773=ORIENTED_EDGE('',*,*,#2772,.F.);
#2774=EDGE_LOOP('',(#2716,#2724,#2733,#2741,#2750,#2758,#2767,#2773));
#2775=FACE_BOUND('',#2774,.T.);
#2776=ADVANCED_FACE('F2116',(#2705,#2775),#2635,.T.);
#2777=CARTESIAN_POINT('',(6.95000000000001,0.,-7.85));
#2778=DIRECTION('',(0.,0.,1.));
#2779=DIRECTION('',(1.,0.,0.));
#2780=AXIS2_PLACEMENT_3D('',#2777,#2778,#2779);
#2781=PLANE('',#2780);
#2782=ORIENTED_EDGE('',*,*,#187,.F.);
#2783=DIRECTION('',(1.,0.,0.));
#2784=VECTOR('',#2783,1.);
#2785=CARTESIAN_POINT('',(6.95000000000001,0.150000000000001,-7.85));
#2786=LINE('',#2785,#2784);
#2787=EDGE_CURVE('E818',#2641,#176,#2786,.T.);
#2788=ORIENTED_EDGE('',*,*,#2787,.F.);
#2789=ORIENTED_EDGE('',*,*,#2644,.T.);
#2790=DIRECTION('',(1.,0.,0.));
#2791=VECTOR('',#2790,1.);
#2792=CARTESIAN_POINT('',(6.95000000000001,-0.150000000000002,-7.85));
#2793=LINE('',#2792,#2791);
#2794=EDGE_CURVE('E849',#2643,#186,#2793,.T.);
#2795=ORIENTED_EDGE('',*,*,#2794,.T.);
#2796=EDGE_LOOP('',(#2782,#2788,#2789,#2795));
#2797=FACE_BOUND('',#2796,.T.);
#2798=ADVANCED_FACE('F1978',(#2797),#2781,.T.);
#2799=CARTESIAN_POINT('',(6.95000000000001,-0.150000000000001,-4.75));
#2800=DIRECTION('',(1.,0.,0.));
#2801=DIRECTION('',(0.,0.,-1.));
#2802=AXIS2_PLACEMENT_3D('',#2799,#2800,#2801);
#2803=CYLINDRICAL_SURFACE('',#2802,3.1);
#2804=ORIENTED_EDGE('',*,*,#196,.T.);
#2805=ORIENTED_EDGE('',*,*,#2794,.F.);
#2806=ORIENTED_EDGE('',*,*,#2702,.F.);
#2807=DIRECTION('',(1.,0.,0.));
#2808=VECTOR('',#2807,1.);
#2809=CARTESIAN_POINT('',(6.95000000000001,-3.25,-4.75));
#2810=LINE('',#2809,#2808);
#2811=EDGE_CURVE('E853',#2694,#195,#2810,.T.);
#2812=ORIENTED_EDGE('',*,*,#2811,.T.);
#2813=EDGE_LOOP('',(#2804,#2805,#2806,#2812));
#2814=FACE_BOUND('',#2813,.T.);
#2815=ADVANCED_FACE('F2393',(#2814),#2803,.F.);
#2816=CARTESIAN_POINT('',(6.95000000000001,-3.25,0.));
#2817=DIRECTION('',(0.,1.,0.));
#2818=DIRECTION('',(0.,0.,1.));
#2819=AXIS2_PLACEMENT_3D('',#2816,#2817,#2818);
#2820=PLANE('',#2819);
#2821=ORIENTED_EDGE('',*,*,#204,.F.);
#2822=ORIENTED_EDGE('',*,*,#2811,.F.);
#2823=ORIENTED_EDGE('',*,*,#2695,.T.);
#2824=DIRECTION('',(1.,0.,0.));
#2825=VECTOR('',#2824,1.);
#2826=CARTESIAN_POINT('',(6.95000000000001,-3.25,4.75));
#2827=LINE('',#2826,#2825);
#2828=EDGE_CURVE('E856',#2686,#203,#2827,.T.);
#2829=ORIENTED_EDGE('',*,*,#2828,.T.);
#2830=EDGE_LOOP('',(#2821,#2822,#2823,#2829));
#2831=FACE_BOUND('',#2830,.T.);
#2832=ADVANCED_FACE('F2384',(#2831),#2820,.T.);
#2833=CARTESIAN_POINT('',(6.95000000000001,-0.150000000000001,4.75));
#2834=DIRECTION('',(1.,0.,0.));
#2835=DIRECTION('',(0.,0.,-1.));
#2836=AXIS2_PLACEMENT_3D('',#2833,#2834,#2835);
#2837=CYLINDRICAL_SURFACE('',#2836,3.1);
#2838=ORIENTED_EDGE('',*,*,#213,.T.);
#2839=ORIENTED_EDGE('',*,*,#2828,.F.);
#2840=ORIENTED_EDGE('',*,*,#2687,.F.);
#2841=DIRECTION('',(1.,0.,0.));
#2842=VECTOR('',#2841,1.);
#2843=CARTESIAN_POINT('',(6.95000000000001,-0.150000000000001,7.85));
#2844=LINE('',#2843,#2842);
#2845=EDGE_CURVE('E859',#2677,#212,#2844,.T.);
#2846=ORIENTED_EDGE('',*,*,#2845,.T.);
#2847=EDGE_LOOP('',(#2838,#2839,#2840,#2846));
#2848=FACE_BOUND('',#2847,.T.);
#2849=ADVANCED_FACE('F2375',(#2848),#2837,.F.);
#2850=CARTESIAN_POINT('',(6.95000000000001,0.,7.85));
#2851=DIRECTION('',(0.,0.,1.));
#2852=DIRECTION('',(1.,0.,0.));
#2853=AXIS2_PLACEMENT_3D('',#2850,#2851,#2852);
#2854=PLANE('',#2853);
#2855=ORIENTED_EDGE('',*,*,#221,.T.);
#2856=ORIENTED_EDGE('',*,*,#2845,.F.);
#2857=ORIENTED_EDGE('',*,*,#2678,.F.);
#2858=DIRECTION('',(1.,0.,0.));
#2859=VECTOR('',#2858,1.);
#2860=CARTESIAN_POINT('',(6.95000000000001,0.150000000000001,7.85));
#2861=LINE('',#2860,#2859);
#2862=EDGE_CURVE('E862',#2669,#220,#2861,.T.);
#2863=ORIENTED_EDGE('',*,*,#2862,.T.);
#2864=EDGE_LOOP('',(#2855,#2856,#2857,#2863));
#2865=FACE_BOUND('',#2864,.T.);
#2866=ADVANCED_FACE('F2366',(#2865),#2854,.F.);
#2867=CARTESIAN_POINT('',(6.95000000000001,0.150000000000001,4.75));
#2868=DIRECTION('',(1.,0.,0.));
#2869=DIRECTION('',(0.,0.,-1.));
#2870=AXIS2_PLACEMENT_3D('',#2867,#2868,#2869);
#2871=CYLINDRICAL_SURFACE('',#2870,3.1);
#2872=ORIENTED_EDGE('',*,*,#230,.T.);
#2873=ORIENTED_EDGE('',*,*,#2862,.F.);
#2874=ORIENTED_EDGE('',*,*,#2670,.F.);
#2875=DIRECTION('',(1.,0.,0.));
#2876=VECTOR('',#2875,1.);
#2877=CARTESIAN_POINT('',(6.95000000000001,3.25,4.75));
#2878=LINE('',#2877,#2876);
#2879=EDGE_CURVE('E865',#2660,#229,#2878,.T.);
#2880=ORIENTED_EDGE('',*,*,#2879,.T.);
#2881=EDGE_LOOP('',(#2872,#2873,#2874,#2880));
#2882=FACE_BOUND('',#2881,.T.);
#2883=ADVANCED_FACE('F2359',(#2882),#2871,.F.);
#2884=CARTESIAN_POINT('',(6.95000000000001,3.25,0.));
#2885=DIRECTION('',(0.,1.,0.));
#2886=DIRECTION('',(0.,0.,1.));
#2887=AXIS2_PLACEMENT_3D('',#2884,#2885,#2886);
#2888=PLANE('',#2887);
#2889=CARTESIAN_POINT('',(8.65000000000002,3.25,0.65));
#2890=DIRECTION('',(0.,1.,0.));
#2891=DIRECTION('',(0.,0.,1.));
#2892=AXIS2_PLACEMENT_3D('',#2889,#2890,#2891);
#2893=CIRCLE('',#2892,0.2);
#2894=CARTESIAN_POINT('',(8.65000000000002,3.25,0.85));
#2895=VERTEX_POINT('',#2894);
#2896=CARTESIAN_POINT('',(8.45000000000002,3.25,0.65));
#2897=VERTEX_POINT('',#2896);
#2898=EDGE_CURVE('E1753',#2895,#2897,#2893,.F.);
#2899=ORIENTED_EDGE('',*,*,#2898,.F.);
#2900=DIRECTION('',(-1.,0.,0.));
#2901=VECTOR('',#2900,1.);
#2902=CARTESIAN_POINT('',(6.95000000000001,3.25,0.849999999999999));
#2903=LINE('',#2902,#2901);
#2904=CARTESIAN_POINT('',(9.05000000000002,3.25,0.85));
#2905=VERTEX_POINT('',#2904);
#2906=EDGE_CURVE('E620',#2895,#2905,#2903,.F.);
#2907=ORIENTED_EDGE('',*,*,#2906,.T.);
#2908=CARTESIAN_POINT('',(9.05000000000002,3.25,0.65));
#2909=DIRECTION('',(0.,1.,0.));
#2910=DIRECTION('',(0.,0.,1.));
#2911=AXIS2_PLACEMENT_3D('',#2908,#2909,#2910);
#2912=CIRCLE('',#2911,0.2);
#2913=CARTESIAN_POINT('',(9.25000000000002,3.25,0.65));
#2914=VERTEX_POINT('',#2913);
#2915=EDGE_CURVE('E1757',#2914,#2905,#2912,.F.);
#2916=ORIENTED_EDGE('',*,*,#2915,.F.);
#2917=DIRECTION('',(0.,0.,1.));
#2918=VECTOR('',#2917,1.);
#2919=CARTESIAN_POINT('',(9.25000000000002,3.25,0.));
#2920=LINE('',#2919,#2918);
#2921=CARTESIAN_POINT('',(9.25000000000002,3.25,-0.65));
#2922=VERTEX_POINT('',#2921);
#2923=EDGE_CURVE('E1749',#2914,#2922,#2920,.F.);
#2924=ORIENTED_EDGE('',*,*,#2923,.T.);
#2925=CARTESIAN_POINT('',(9.05000000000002,3.25,-0.65));
#2926=DIRECTION('',(0.,1.,0.));
#2927=DIRECTION('',(0.,0.,1.));
#2928=AXIS2_PLACEMENT_3D('',#2925,#2926,#2927);
#2929=CIRCLE('',#2928,0.2);
#2930=CARTESIAN_POINT('',(9.05000000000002,3.25,-0.85));
#2931=VERTEX_POINT('',#2930);
#2932=EDGE_CURVE('E1745',#2931,#2922,#2929,.F.);
#2933=ORIENTED_EDGE('',*,*,#2932,.F.);
#2934=DIRECTION('',(1.,0.,0.));
#2935=VECTOR('',#2934,1.);
#2936=CARTESIAN_POINT('',(6.95000000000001,3.25,-0.85));
#2937=LINE('',#2936,#2935);
#2938=CARTESIAN_POINT('',(8.65000000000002,3.25,-0.85));
#2939=VERTEX_POINT('',#2938);
#2940=EDGE_CURVE('E1739',#2931,#2939,#2937,.F.);
#2941=ORIENTED_EDGE('',*,*,#2940,.T.);
#2942=CARTESIAN_POINT('',(8.65000000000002,3.25,-0.65));
#2943=DIRECTION('',(0.,1.,0.));
#2944=DIRECTION('',(0.,0.,1.));
#2945=AXIS2_PLACEMENT_3D('',#2942,#2943,#2944);
#2946=CIRCLE('',#2945,0.2);
#2947=CARTESIAN_POINT('',(8.45000000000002,3.25,-0.65));
#2948=VERTEX_POINT('',#2947);
#2949=EDGE_CURVE('E1735',#2948,#2939,#2946,.F.);
#2950=ORIENTED_EDGE('',*,*,#2949,.F.);
#2951=DIRECTION('',(0.,0.,-1.));
#2952=VECTOR('',#2951,1.);
#2953=CARTESIAN_POINT('',(8.45000000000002,3.25,0.));
#2954=LINE('',#2953,#2952);
#2955=EDGE_CURVE('E1742',#2948,#2897,#2954,.F.);
#2956=ORIENTED_EDGE('',*,*,#2955,.T.);
#2957=EDGE_LOOP('',(#2899,#2907,#2916,#2924,#2933,#2941,#2950,#2956));
#2958=FACE_BOUND('',#2957,.T.);
#2959=ORIENTED_EDGE('',*,*,#236,.T.);
#2960=ORIENTED_EDGE('',*,*,#2879,.F.);
#2961=ORIENTED_EDGE('',*,*,#2661,.F.);
#2962=DIRECTION('',(1.,0.,0.));
#2963=VECTOR('',#2962,1.);
#2964=CARTESIAN_POINT('',(6.95000000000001,3.25,-4.75));
#2965=LINE('',#2964,#2963);
#2966=EDGE_CURVE('E868',#2652,#178,#2965,.T.);
#2967=ORIENTED_EDGE('',*,*,#2966,.T.);
#2968=EDGE_LOOP('',(#2959,#2960,#2961,#2967));
#2969=FACE_BOUND('',#2968,.T.);
#2970=ADVANCED_FACE('F1764',(#2958,#2969),#2888,.F.);
#2971=CARTESIAN_POINT('',(6.95000000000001,0.150000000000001,-4.75));
#2972=DIRECTION('',(1.,0.,0.));
#2973=DIRECTION('',(0.,0.,-1.));
#2974=AXIS2_PLACEMENT_3D('',#2971,#2972,#2973);
#2975=CYLINDRICAL_SURFACE('',#2974,3.1);
#2976=ORIENTED_EDGE('',*,*,#179,.T.);
#2977=ORIENTED_EDGE('',*,*,#2966,.F.);
#2978=ORIENTED_EDGE('',*,*,#2653,.F.);
#2979=ORIENTED_EDGE('',*,*,#2787,.T.);
#2980=EDGE_LOOP('',(#2976,#2977,#2978,#2979));
#2981=FACE_BOUND('',#2980,.T.);
#2982=ADVANCED_FACE('F1834',(#2981),#2975,.F.);
#2983=CARTESIAN_POINT('',(0.,-0.150000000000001,0.));
#2984=DIRECTION('',(0.,1.,0.));
#2985=DIRECTION('',(0.,0.,1.));
#2986=AXIS2_PLACEMENT_3D('',#2983,#2984,#2985);
#2987=TOROIDAL_SURFACE('',#2986,4.75,2.6);
#2988=CARTESIAN_POINT('',(0.,-0.150000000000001,4.75));
#2989=DIRECTION('',(-1.,0.,0.));
#2990=DIRECTION('',(0.,0.,1.));
#2991=AXIS2_PLACEMENT_3D('',#2988,#2989,#2990);
#2992=CIRCLE('',#2991,2.6);
#2993=CARTESIAN_POINT('',(0.,-2.75,4.75));
#2994=VERTEX_POINT('',#2993);
#2995=CARTESIAN_POINT('',(0.,-0.150000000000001,7.35));
#2996=VERTEX_POINT('',#2995);
#2997=EDGE_CURVE('E942',#2994,#2996,#2992,.T.);
#2998=ORIENTED_EDGE('',*,*,#2997,.F.);
#2999=CARTESIAN_POINT('',(0.,-2.75,0.));
#3000=DIRECTION('',(0.,1.,0.));
#3001=DIRECTION('',(0.,0.,1.));
#3002=AXIS2_PLACEMENT_3D('',#2999,#3000,#3001);
#3003=CIRCLE('',#3002,4.75);
#3004=CARTESIAN_POINT('',(0.,-2.75,-4.75));
#3005=VERTEX_POINT('',#3004);
#3006=EDGE_CURVE('E950',#2994,#3005,#3003,.F.);
#3007=ORIENTED_EDGE('',*,*,#3006,.T.);
#3008=CARTESIAN_POINT('',(0.,-0.150000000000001,-4.75));
#3009=DIRECTION('',(-1.,0.,0.));
#3010=DIRECTION('',(0.,0.,1.));
#3011=AXIS2_PLACEMENT_3D('',#3008,#3009,#3010);
#3012=CIRCLE('',#3011,2.6);
#3013=CARTESIAN_POINT('',(0.,-0.150000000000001,-7.35));
#3014=VERTEX_POINT('',#3013);
#3015=EDGE_CURVE('E947',#3005,#3014,#3012,.F.);
#3016=ORIENTED_EDGE('',*,*,#3015,.T.);
#3017=EDGE_CURVE('E921',#3014,#29,#55,.F.);
#3018=ORIENTED_EDGE('',*,*,#3017,.T.);
#3019=ORIENTED_EDGE('',*,*,#56,.T.);
#3020=CARTESIAN_POINT('',(0.,-0.150000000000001,0.));
#3021=DIRECTION('',(0.,-1.,0.));
#3022=DIRECTION('',(0.,0.,-1.));
#3023=AXIS2_PLACEMENT_3D('',#3020,#3021,#3022);
#3024=CIRCLE('',#3023,7.35);
#3025=EDGE_CURVE('E760',#48,#2996,#3024,.F.);
#3026=ORIENTED_EDGE('',*,*,#3025,.T.);
#3027=EDGE_LOOP('',(#2998,#3007,#3016,#3018,#3019,#3026));
#3028=FACE_BOUND('',#3027,.T.);
#3029=ADVANCED_FACE('F1830',(#3028),#2987,.F.);
#3030=CARTESIAN_POINT('',(0.,0.150000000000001,0.));
#3031=DIRECTION('',(0.,1.,0.));
#3032=DIRECTION('',(0.,0.,1.));
#3033=AXIS2_PLACEMENT_3D('',#3030,#3031,#3032);
#3034=TOROIDAL_SURFACE('',#3033,4.75,2.6);
#3035=CARTESIAN_POINT('',(0.,0.150000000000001,4.75));
#3036=DIRECTION('',(-1.,0.,0.));
#3037=DIRECTION('',(0.,0.,1.));
#3038=AXIS2_PLACEMENT_3D('',#3035,#3036,#3037);
#3039=CIRCLE('',#3038,2.6);
#3040=CARTESIAN_POINT('',(0.,0.150000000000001,7.35));
#3041=VERTEX_POINT('',#3040);
#3042=CARTESIAN_POINT('',(0.,2.75,4.75));
#3043=VERTEX_POINT('',#3042);
#3044=EDGE_CURVE('E961',#3041,#3043,#3039,.T.);
#3045=ORIENTED_EDGE('',*,*,#3044,.F.);
#3046=EDGE_CURVE('E927',#3041,#40,#38,.T.);
#3047=ORIENTED_EDGE('',*,*,#3046,.T.);
#3048=ORIENTED_EDGE('',*,*,#41,.T.);
#3049=CARTESIAN_POINT('',(0.,0.150000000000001,0.));
#3050=DIRECTION('',(0.,1.,0.));
#3051=DIRECTION('',(0.,0.,1.));
#3052=AXIS2_PLACEMENT_3D('',#3049,#3050,#3051);
#3053=CIRCLE('',#3052,7.35);
#3054=CARTESIAN_POINT('',(0.,0.150000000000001,-7.35));
#3055=VERTEX_POINT('',#3054);
#3056=EDGE_CURVE('E747',#31,#3055,#3053,.F.);
#3057=ORIENTED_EDGE('',*,*,#3056,.T.);
#3058=CARTESIAN_POINT('',(0.,0.150000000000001,-4.75));
#3059=DIRECTION('',(1.,0.,0.));
#3060=DIRECTION('',(0.,0.,-1.));
#3061=AXIS2_PLACEMENT_3D('',#3058,#3059,#3060);
#3062=CIRCLE('',#3061,2.6);
#3063=CARTESIAN_POINT('',(0.,2.75,-4.75));
#3064=VERTEX_POINT('',#3063);
#3065=EDGE_CURVE('E920',#3055,#3064,#3062,.T.);
#3066=ORIENTED_EDGE('',*,*,#3065,.T.);
#3067=CARTESIAN_POINT('',(0.,2.75,0.));
#3068=DIRECTION('',(0.,1.,0.));
#3069=DIRECTION('',(0.,0.,1.));
#3070=AXIS2_PLACEMENT_3D('',#3067,#3068,#3069);
#3071=CIRCLE('',#3070,4.75);
#3072=EDGE_CURVE('E925',#3064,#3043,#3071,.T.);
#3073=ORIENTED_EDGE('',*,*,#3072,.T.);
#3074=EDGE_LOOP('',(#3045,#3047,#3048,#3057,#3066,#3073));
#3075=FACE_BOUND('',#3074,.T.);
#3076=ADVANCED_FACE('F1833',(#3075),#3034,.F.);
#3077=CARTESIAN_POINT('',(0.,-0.150000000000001,-4.75));
#3078=DIRECTION('',(-1.,0.,0.));
#3079=DIRECTION('',(0.,0.,1.));
#3080=AXIS2_PLACEMENT_3D('',#3077,#3078,#3079);
#3081=CYLINDRICAL_SURFACE('',#3080,2.6);
#3082=ORIENTED_EDGE('',*,*,#2766,.F.);
#3083=DIRECTION('',(-1.,0.,0.));
#3084=VECTOR('',#3083,1.);
#3085=CARTESIAN_POINT('',(0.,-0.150000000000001,-7.35));
#3086=LINE('',#3085,#3084);
#3087=CARTESIAN_POINT('',(4.95000000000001,-0.150000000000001,-7.35));
#3088=VERTEX_POINT('',#3087);
#3089=EDGE_CURVE('E962',#2756,#3088,#3086,.T.);
#3090=ORIENTED_EDGE('',*,*,#3089,.T.);
#3091=DIRECTION('',(1.,0.,0.));
#3092=VECTOR('',#3091,1.);
#3093=CARTESIAN_POINT('',(-8.851,-0.150000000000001,-7.35));
#3094=LINE('',#3093,#3092);
#3095=EDGE_CURVE('E748',#3014,#3088,#3094,.T.);
#3096=ORIENTED_EDGE('',*,*,#3095,.F.);
#3097=ORIENTED_EDGE('',*,*,#3015,.F.);
#3098=DIRECTION('',(1.,0.,0.));
#3099=VECTOR('',#3098,1.);
#3100=CARTESIAN_POINT('',(0.,-2.75,-4.75));
#3101=LINE('',#3100,#3099);
#3102=EDGE_CURVE('E953',#3005,#2765,#3101,.T.);
#3103=ORIENTED_EDGE('',*,*,#3102,.T.);
#3104=EDGE_LOOP('',(#3082,#3090,#3096,#3097,#3103));
#3105=FACE_BOUND('',#3104,.T.);
#3106=ADVANCED_FACE('F1828',(#3105),#3081,.F.);
#3107=CARTESIAN_POINT('',(0.,-0.150000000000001,4.75));
#3108=DIRECTION('',(1.,0.,0.));
#3109=DIRECTION('',(0.,0.,-1.));
#3110=AXIS2_PLACEMENT_3D('',#3107,#3108,#3109);
#3111=CYLINDRICAL_SURFACE('',#3110,2.6);
#3112=ORIENTED_EDGE('',*,*,#2715,.F.);
#3113=DIRECTION('',(1.,0.,0.));
#3114=VECTOR('',#3113,1.);
#3115=CARTESIAN_POINT('',(0.,-2.75,4.75));
#3116=LINE('',#3115,#3114);
#3117=EDGE_CURVE('E946',#2712,#2994,#3116,.F.);
#3118=ORIENTED_EDGE('',*,*,#3117,.T.);
#3119=ORIENTED_EDGE('',*,*,#2997,.T.);
#3120=DIRECTION('',(1.,0.,0.));
#3121=VECTOR('',#3120,1.);
#3122=CARTESIAN_POINT('',(9.95000000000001,-0.150000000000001,7.35));
#3123=LINE('',#3122,#3121);
#3124=CARTESIAN_POINT('',(4.95000000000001,-0.150000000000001,7.35));
#3125=VERTEX_POINT('',#3124);
#3126=EDGE_CURVE('E937',#2996,#3125,#3123,.T.);
#3127=ORIENTED_EDGE('',*,*,#3126,.T.);
#3128=EDGE_CURVE('E941',#3125,#2714,#3123,.T.);
#3129=ORIENTED_EDGE('',*,*,#3128,.T.);
#3130=EDGE_LOOP('',(#3112,#3118,#3119,#3127,#3129));
#3131=FACE_BOUND('',#3130,.T.);
#3132=ADVANCED_FACE('F1824',(#3131),#3111,.F.);
#3133=CARTESIAN_POINT('',(0.,-2.75,0.));
#3134=DIRECTION('',(0.,1.,0.));
#3135=DIRECTION('',(0.,0.,1.));
#3136=AXIS2_PLACEMENT_3D('',#3133,#3134,#3135);
#3137=PLANE('',#3136);
#3138=ORIENTED_EDGE('',*,*,#3117,.F.);
#3139=ORIENTED_EDGE('',*,*,#2772,.T.);
#3140=ORIENTED_EDGE('',*,*,#3102,.F.);
#3141=ORIENTED_EDGE('',*,*,#3006,.F.);
#3142=EDGE_LOOP('',(#3138,#3139,#3140,#3141));
#3143=FACE_BOUND('',#3142,.T.);
#3144=ADVANCED_FACE('F1820',(#3143),#3137,.T.);
#3145=CARTESIAN_POINT('',(0.,0.150000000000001,-4.75));
#3146=DIRECTION('',(1.,0.,0.));
#3147=DIRECTION('',(0.,0.,-1.));
#3148=AXIS2_PLACEMENT_3D('',#3145,#3146,#3147);
#3149=CYLINDRICAL_SURFACE('',#3148,2.6);
#3150=ORIENTED_EDGE('',*,*,#2749,.F.);
#3151=DIRECTION('',(1.,0.,0.));
#3152=VECTOR('',#3151,1.);
#3153=CARTESIAN_POINT('',(0.,2.75,-4.75));
#3154=LINE('',#3153,#3152);
#3155=EDGE_CURVE('E979',#2739,#3064,#3154,.F.);
#3156=ORIENTED_EDGE('',*,*,#3155,.T.);
#3157=ORIENTED_EDGE('',*,*,#3065,.F.);
#3158=DIRECTION('',(-1.,0.,0.));
#3159=VECTOR('',#3158,1.);
#3160=CARTESIAN_POINT('',(0.,0.150000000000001,-7.35));
#3161=LINE('',#3160,#3159);
#3162=CARTESIAN_POINT('',(4.95000000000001,0.150000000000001,-7.35));
#3163=VERTEX_POINT('',#3162);
#3164=EDGE_CURVE('E966',#3055,#3163,#3161,.F.);
#3165=ORIENTED_EDGE('',*,*,#3164,.T.);
#3166=EDGE_CURVE('E957',#3163,#2748,#3161,.F.);
#3167=ORIENTED_EDGE('',*,*,#3166,.T.);
#3168=EDGE_LOOP('',(#3150,#3156,#3157,#3165,#3167));
#3169=FACE_BOUND('',#3168,.T.);
#3170=ADVANCED_FACE('F1823',(#3169),#3149,.F.);
#3171=CARTESIAN_POINT('',(9.95000000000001,0.150000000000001,4.75));
#3172=DIRECTION('',(-1.,0.,0.));
#3173=DIRECTION('',(0.,0.,1.));
#3174=AXIS2_PLACEMENT_3D('',#3171,#3172,#3173);
#3175=CYLINDRICAL_SURFACE('',#3174,2.6);
#3176=ORIENTED_EDGE('',*,*,#2732,.F.);
#3177=DIRECTION('',(1.,0.,0.));
#3178=VECTOR('',#3177,1.);
#3179=CARTESIAN_POINT('',(9.95000000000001,0.150000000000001,7.35));
#3180=LINE('',#3179,#3178);
#3181=CARTESIAN_POINT('',(4.95000000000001,0.150000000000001,7.35));
#3182=VERTEX_POINT('',#3181);
#3183=EDGE_CURVE('E932',#2722,#3182,#3180,.F.);
#3184=ORIENTED_EDGE('',*,*,#3183,.T.);
#3185=DIRECTION('',(1.,0.,0.));
#3186=VECTOR('',#3185,1.);
#3187=CARTESIAN_POINT('',(-8.851,0.150000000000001,7.35));
#3188=LINE('',#3187,#3186);
#3189=EDGE_CURVE('E778',#3041,#3182,#3188,.T.);
#3190=ORIENTED_EDGE('',*,*,#3189,.F.);
#3191=ORIENTED_EDGE('',*,*,#3044,.T.);
#3192=DIRECTION('',(1.,0.,0.));
#3193=VECTOR('',#3192,1.);
#3194=CARTESIAN_POINT('',(0.,2.75,4.75));
#3195=LINE('',#3194,#3193);
#3196=EDGE_CURVE('E975',#3043,#2731,#3195,.T.);
#3197=ORIENTED_EDGE('',*,*,#3196,.T.);
#3198=EDGE_LOOP('',(#3176,#3184,#3190,#3191,#3197));
#3199=FACE_BOUND('',#3198,.T.);
#3200=ADVANCED_FACE('F1818',(#3199),#3175,.F.);
#3201=CARTESIAN_POINT('',(0.,2.75,0.));
#3202=DIRECTION('',(0.,1.,0.));
#3203=DIRECTION('',(0.,0.,1.));
#3204=AXIS2_PLACEMENT_3D('',#3201,#3202,#3203);
#3205=PLANE('',#3204);
#3206=ORIENTED_EDGE('',*,*,#2740,.F.);
#3207=ORIENTED_EDGE('',*,*,#3196,.F.);
#3208=ORIENTED_EDGE('',*,*,#3072,.F.);
#3209=ORIENTED_EDGE('',*,*,#3155,.F.);
#3210=EDGE_LOOP('',(#3206,#3207,#3208,#3209));
#3211=FACE_BOUND('',#3210,.T.);
#3212=ADVANCED_FACE('F1814',(#3211),#3205,.F.);
#3213=CARTESIAN_POINT('',(0.,4.25,-7.35));
#3214=DIRECTION('',(0.,0.,-1.));
#3215=DIRECTION('',(-1.,0.,0.));
#3216=AXIS2_PLACEMENT_3D('',#3213,#3214,#3215);
#3217=PLANE('',#3216);
#3218=ORIENTED_EDGE('',*,*,#3166,.F.);
#3219=DIRECTION('',(0.,1.,0.));
#3220=VECTOR('',#3219,1.);
#3221=CARTESIAN_POINT('',(4.95000000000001,0.,-7.35));
#3222=LINE('',#3221,#3220);
#3223=EDGE_CURVE('E733',#3088,#3163,#3222,.T.);
#3224=ORIENTED_EDGE('',*,*,#3223,.F.);
#3225=ORIENTED_EDGE('',*,*,#3089,.F.);
#3226=ORIENTED_EDGE('',*,*,#2757,.F.);
#3227=EDGE_LOOP('',(#3218,#3224,#3225,#3226));
#3228=FACE_BOUND('',#3227,.T.);
#3229=ADVANCED_FACE('F1810',(#3228),#3217,.F.);
#3230=CARTESIAN_POINT('',(9.95000000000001,4.25,7.35));
#3231=DIRECTION('',(0.,0.,1.));
#3232=DIRECTION('',(1.,0.,0.));
#3233=AXIS2_PLACEMENT_3D('',#3230,#3231,#3232);
#3234=PLANE('',#3233);
#3235=ORIENTED_EDGE('',*,*,#3128,.F.);
#3236=DIRECTION('',(0.,1.,0.));
#3237=VECTOR('',#3236,1.);
#3238=CARTESIAN_POINT('',(4.95000000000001,0.,7.35));
#3239=LINE('',#3238,#3237);
#3240=EDGE_CURVE('E765',#3125,#3182,#3239,.T.);
#3241=ORIENTED_EDGE('',*,*,#3240,.T.);
#3242=ORIENTED_EDGE('',*,*,#3183,.F.);
#3243=ORIENTED_EDGE('',*,*,#2723,.F.);
#3244=EDGE_LOOP('',(#3235,#3241,#3242,#3243));
#3245=FACE_BOUND('',#3244,.T.);
#3246=ADVANCED_FACE('F1806',(#3245),#3234,.F.);
#3247=CARTESIAN_POINT('',(4.95000000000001,0.,0.));
#3248=DIRECTION('',(1.,0.,0.));
#3249=DIRECTION('',(0.,0.,-1.));
#3250=AXIS2_PLACEMENT_3D('',#3247,#3248,#3249);
#3251=PLANE('',#3250);
#3252=DIRECTION('',(0.,0.,-1.));
#3253=VECTOR('',#3252,1.);
#3254=CARTESIAN_POINT('',(4.95000000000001,-0.150000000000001,0.));
#3255=LINE('',#3254,#3253);
#3256=CARTESIAN_POINT('',(4.95000000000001,-0.150000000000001,7.25));
#3257=VERTEX_POINT('',#3256);
#3258=EDGE_CURVE('E769',#3125,#3257,#3255,.T.);
#3259=ORIENTED_EDGE('',*,*,#3258,.T.);
#3260=DIRECTION('',(0.,-1.,0.));
#3261=VECTOR('',#3260,1.);
#3262=CARTESIAN_POINT('',(4.95000000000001,0.150000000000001,7.25));
#3263=LINE('',#3262,#3261);
#3264=CARTESIAN_POINT('',(4.95000000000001,0.150000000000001,7.25));
#3265=VERTEX_POINT('',#3264);
#3266=EDGE_CURVE('E1729',#3257,#3265,#3263,.F.);
#3267=ORIENTED_EDGE('',*,*,#3266,.T.);
#3268=DIRECTION('',(0.,0.,-1.));
#3269=VECTOR('',#3268,1.);
#3270=CARTESIAN_POINT('',(4.95000000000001,0.150000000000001,0.));
#3271=LINE('',#3270,#3269);
#3272=EDGE_CURVE('E761',#3182,#3265,#3271,.T.);
#3273=ORIENTED_EDGE('',*,*,#3272,.F.);
#3274=ORIENTED_EDGE('',*,*,#3240,.F.);
#3275=EDGE_LOOP('',(#3259,#3267,#3273,#3274));
#3276=FACE_BOUND('',#3275,.T.);
#3277=ADVANCED_FACE('F1809',(#3276),#3251,.T.);
#3278=CARTESIAN_POINT('',(-8.851,0.150000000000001,0.));
#3279=DIRECTION('',(0.,-1.,0.));
#3280=DIRECTION('',(0.,0.,-1.));
#3281=AXIS2_PLACEMENT_3D('',#3278,#3279,#3280);
#3282=PLANE('',#3281);
#3283=ORIENTED_EDGE('',*,*,#3272,.T.);
#3284=CARTESIAN_POINT('',(3.95000000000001,0.150000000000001,7.25));
#3285=DIRECTION('',(0.,-1.,0.));
#3286=DIRECTION('',(0.,0.,-1.));
#3287=AXIS2_PLACEMENT_3D('',#3284,#3285,#3286);
#3288=CIRCLE('',#3287,1.);
#3289=CARTESIAN_POINT('',(3.95000000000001,0.150000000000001,6.25));
#3290=VERTEX_POINT('',#3289);
#3291=EDGE_CURVE('E1732',#3265,#3290,#3288,.F.);
#3292=ORIENTED_EDGE('',*,*,#3291,.T.);
#3293=DIRECTION('',(1.,0.,0.));
#3294=VECTOR('',#3293,1.);
#3295=CARTESIAN_POINT('',(-8.851,0.150000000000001,6.25));
#3296=LINE('',#3295,#3294);
#3297=EDGE_CURVE('E773',#40,#3290,#3296,.T.);
#3298=ORIENTED_EDGE('',*,*,#3297,.F.);
#3299=ORIENTED_EDGE('',*,*,#3046,.F.);
#3300=ORIENTED_EDGE('',*,*,#3189,.T.);
#3301=EDGE_LOOP('',(#3283,#3292,#3298,#3299,#3300));
#3302=FACE_BOUND('',#3301,.T.);
#3303=ADVANCED_FACE('F2320',(#3302),#3282,.F.);
#3304=CARTESIAN_POINT('',(-8.851,-0.150000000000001,0.));
#3305=DIRECTION('',(0.,-1.,0.));
#3306=DIRECTION('',(0.,0.,-1.));
#3307=AXIS2_PLACEMENT_3D('',#3304,#3305,#3306);
#3308=PLANE('',#3307);
#3309=DIRECTION('',(1.,0.,0.));
#3310=VECTOR('',#3309,1.);
#3311=CARTESIAN_POINT('',(-8.851,-0.150000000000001,6.25));
#3312=LINE('',#3311,#3310);
#3313=CARTESIAN_POINT('',(3.95000000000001,-0.150000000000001,6.25));
#3314=VERTEX_POINT('',#3313);
#3315=EDGE_CURVE('E774',#48,#3314,#3312,.T.);
#3316=ORIENTED_EDGE('',*,*,#3315,.T.);
#3317=CARTESIAN_POINT('',(3.95000000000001,-0.150000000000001,7.25));
#3318=DIRECTION('',(0.,-1.,0.));
#3319=DIRECTION('',(0.,0.,-1.));
#3320=AXIS2_PLACEMENT_3D('',#3317,#3318,#3319);
#3321=CIRCLE('',#3320,1.);
#3322=EDGE_CURVE('E1726',#3314,#3257,#3321,.T.);
#3323=ORIENTED_EDGE('',*,*,#3322,.T.);
#3324=ORIENTED_EDGE('',*,*,#3258,.F.);
#3325=ORIENTED_EDGE('',*,*,#3126,.F.);
#3326=ORIENTED_EDGE('',*,*,#3025,.F.);
#3327=EDGE_LOOP('',(#3316,#3323,#3324,#3325,#3326));
#3328=FACE_BOUND('',#3327,.T.);
#3329=ADVANCED_FACE('F2311',(#3328),#3308,.T.);
#3330=CARTESIAN_POINT('',(-8.851,0.,6.25));
#3331=DIRECTION('',(0.,0.,1.));
#3332=DIRECTION('',(1.,0.,0.));
#3333=AXIS2_PLACEMENT_3D('',#3330,#3331,#3332);
#3334=PLANE('',#3333);
#3335=ORIENTED_EDGE('',*,*,#3297,.T.);
#3336=DIRECTION('',(0.,-1.,0.));
#3337=VECTOR('',#3336,1.);
#3338=CARTESIAN_POINT('',(3.95000000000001,-0.150000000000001,6.25));
#3339=LINE('',#3338,#3337);
#3340=EDGE_CURVE('E1722',#3290,#3314,#3339,.T.);
#3341=ORIENTED_EDGE('',*,*,#3340,.T.);
#3342=ORIENTED_EDGE('',*,*,#3315,.F.);
#3343=ORIENTED_EDGE('',*,*,#49,.T.);
#3344=EDGE_LOOP('',(#3335,#3341,#3342,#3343));
#3345=FACE_BOUND('',#3344,.T.);
#3346=ADVANCED_FACE('F2141',(#3345),#3334,.F.);
#3347=CARTESIAN_POINT('',(3.95000000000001,0.,7.25));
#3348=DIRECTION('',(0.,1.,0.));
#3349=DIRECTION('',(0.,0.,1.));
#3350=AXIS2_PLACEMENT_3D('',#3347,#3348,#3349);
#3351=CYLINDRICAL_SURFACE('',#3350,1.);
#3352=ORIENTED_EDGE('',*,*,#3291,.F.);
#3353=ORIENTED_EDGE('',*,*,#3266,.F.);
#3354=ORIENTED_EDGE('',*,*,#3322,.F.);
#3355=ORIENTED_EDGE('',*,*,#3340,.F.);
#3356=EDGE_LOOP('',(#3352,#3353,#3354,#3355));
#3357=FACE_BOUND('',#3356,.T.);
#3358=ADVANCED_FACE('F2137',(#3357),#3351,.T.);
#3359=CARTESIAN_POINT('',(4.95000000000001,0.,0.));
#3360=DIRECTION('',(1.,0.,0.));
#3361=DIRECTION('',(0.,0.,1.));
#3362=AXIS2_PLACEMENT_3D('',#3359,#3360,#3361);
#3363=PLANE('',#3362);
#3364=DIRECTION('',(0.,-1.,0.));
#3365=VECTOR('',#3364,1.);
#3366=CARTESIAN_POINT('',(4.95000000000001,0.,-6.25));
#3367=LINE('',#3366,#3365);
#3368=CARTESIAN_POINT('',(4.95000000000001,0.150000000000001,-6.25));
#3369=VERTEX_POINT('',#3368);
#3370=CARTESIAN_POINT('',(4.95000000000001,-0.150000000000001,-6.25));
#3371=VERTEX_POINT('',#3370);
#3372=EDGE_CURVE('E722',#3369,#3371,#3367,.T.);
#3373=ORIENTED_EDGE('',*,*,#3372,.T.);
#3374=DIRECTION('',(0.,0.,1.));
#3375=VECTOR('',#3374,1.);
#3376=CARTESIAN_POINT('',(4.95000000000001,-0.150000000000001,0.));
#3377=LINE('',#3376,#3375);
#3378=EDGE_CURVE('E727',#3088,#3371,#3377,.T.);
#3379=ORIENTED_EDGE('',*,*,#3378,.F.);
#3380=ORIENTED_EDGE('',*,*,#3223,.T.);
#3381=DIRECTION('',(0.,0.,1.));
#3382=VECTOR('',#3381,1.);
#3383=CARTESIAN_POINT('',(4.95000000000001,0.150000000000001,0.));
#3384=LINE('',#3383,#3382);
#3385=EDGE_CURVE('E741',#3163,#3369,#3384,.T.);
#3386=ORIENTED_EDGE('',*,*,#3385,.T.);
#3387=EDGE_LOOP('',(#3373,#3379,#3380,#3386));
#3388=FACE_BOUND('',#3387,.T.);
#3389=ADVANCED_FACE('F2140',(#3388),#3363,.T.);
#3390=CARTESIAN_POINT('',(-8.851,-0.150000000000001,0.));
#3391=DIRECTION('',(0.,1.,0.));
#3392=DIRECTION('',(0.,0.,1.));
#3393=AXIS2_PLACEMENT_3D('',#3390,#3391,#3392);
#3394=PLANE('',#3393);
#3395=DIRECTION('',(1.,0.,0.));
#3396=VECTOR('',#3395,1.);
#3397=CARTESIAN_POINT('',(-8.851,-0.150000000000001,-6.25));
#3398=LINE('',#3397,#3396);
#3399=EDGE_CURVE('E106',#29,#3371,#3398,.T.);
#3400=ORIENTED_EDGE('',*,*,#3399,.F.);
#3401=ORIENTED_EDGE('',*,*,#3017,.F.);
#3402=ORIENTED_EDGE('',*,*,#3095,.T.);
#3403=ORIENTED_EDGE('',*,*,#3378,.T.);
#3404=EDGE_LOOP('',(#3400,#3401,#3402,#3403));
#3405=FACE_BOUND('',#3404,.T.);
#3406=ADVANCED_FACE('F2281',(#3405),#3394,.F.);
#3407=CARTESIAN_POINT('',(-8.851,0.150000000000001,0.));
#3408=DIRECTION('',(0.,1.,0.));
#3409=DIRECTION('',(0.,0.,1.));
#3410=AXIS2_PLACEMENT_3D('',#3407,#3408,#3409);
#3411=PLANE('',#3410);
#3412=ORIENTED_EDGE('',*,*,#3056,.F.);
#3413=DIRECTION('',(1.,0.,0.));
#3414=VECTOR('',#3413,1.);
#3415=CARTESIAN_POINT('',(-8.851,0.150000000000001,-6.25));
#3416=LINE('',#3415,#3414);
#3417=EDGE_CURVE('E744',#31,#3369,#3416,.T.);
#3418=ORIENTED_EDGE('',*,*,#3417,.T.);
#3419=ORIENTED_EDGE('',*,*,#3385,.F.);
#3420=ORIENTED_EDGE('',*,*,#3164,.F.);
#3421=EDGE_LOOP('',(#3412,#3418,#3419,#3420));
#3422=FACE_BOUND('',#3421,.T.);
#3423=ADVANCED_FACE('F2273',(#3422),#3411,.T.);
#3424=CARTESIAN_POINT('',(-8.851,0.,-6.25));
#3425=DIRECTION('',(0.,0.,1.));
#3426=DIRECTION('',(1.,0.,0.));
#3427=AXIS2_PLACEMENT_3D('',#3424,#3425,#3426);
#3428=PLANE('',#3427);
#3429=ORIENTED_EDGE('',*,*,#32,.F.);
#3430=ORIENTED_EDGE('',*,*,#3399,.T.);
#3431=ORIENTED_EDGE('',*,*,#3372,.F.);
#3432=ORIENTED_EDGE('',*,*,#3417,.F.);
#3433=EDGE_LOOP('',(#3429,#3430,#3431,#3432));
#3434=FACE_BOUND('',#3433,.T.);
#3435=ADVANCED_FACE('F2264',(#3434),#3428,.T.);
#3436=CARTESIAN_POINT('',(0.,3.45,0.));
#3437=DIRECTION('',(0.,-1.,0.));
#3438=DIRECTION('',(0.,0.,-1.));
#3439=AXIS2_PLACEMENT_3D('',#3436,#3437,#3438);
#3440=PLANE('',#3439);
#3441=DIRECTION('',(-1.,0.,0.));
#3442=VECTOR('',#3441,1.);
#3443=CARTESIAN_POINT('',(0.,3.45,0.649999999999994));
#3444=LINE('',#3443,#3442);
#3445=CARTESIAN_POINT('',(9.05000000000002,3.45,0.65));
#3446=VERTEX_POINT('',#3445);
#3447=CARTESIAN_POINT('',(8.65000000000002,3.45,0.65));
#3448=VERTEX_POINT('',#3447);
#3449=EDGE_CURVE('E55',#3446,#3448,#3444,.T.);
#3450=ORIENTED_EDGE('',*,*,#3449,.T.);
#3451=DIRECTION('',(0.,0.,-1.));
#3452=VECTOR('',#3451,1.);
#3453=CARTESIAN_POINT('',(8.65000000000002,3.45,0.));
#3454=LINE('',#3453,#3452);
#3455=CARTESIAN_POINT('',(8.65000000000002,3.45,-0.65));
#3456=VERTEX_POINT('',#3455);
#3457=EDGE_CURVE('E11',#3448,#3456,#3454,.T.);
#3458=ORIENTED_EDGE('',*,*,#3457,.T.);
#3459=DIRECTION('',(1.,0.,0.));
#3460=VECTOR('',#3459,1.);
#3461=CARTESIAN_POINT('',(0.,3.45,-0.65));
#3462=LINE('',#3461,#3460);
#3463=CARTESIAN_POINT('',(9.05000000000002,3.45,-0.65));
#3464=VERTEX_POINT('',#3463);
#3465=EDGE_CURVE('E611',#3456,#3464,#3462,.T.);
#3466=ORIENTED_EDGE('',*,*,#3465,.T.);
#3467=DIRECTION('',(0.,0.,1.));
#3468=VECTOR('',#3467,1.);
#3469=CARTESIAN_POINT('',(9.05000000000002,3.45,0.));
#3470=LINE('',#3469,#3468);
#3471=EDGE_CURVE('E615',#3464,#3446,#3470,.T.);
#3472=ORIENTED_EDGE('',*,*,#3471,.T.);
#3473=EDGE_LOOP('',(#3450,#3458,#3466,#3472));
#3474=FACE_BOUND('',#3473,.T.);
#3475=ADVANCED_FACE('F613',(#3474),#3440,.T.);
#3476=CARTESIAN_POINT('',(8.65000000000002,3.35,0.));
#3477=DIRECTION('',(0.,0.,-1.));
#3478=DIRECTION('',(-1.,0.,0.));
#3479=AXIS2_PLACEMENT_3D('',#3476,#3477,#3478);
#3480=CYLINDRICAL_SURFACE('',#3479,0.1);
#3481=DIRECTION('',(0.,0.,-1.));
#3482=VECTOR('',#3481,1.);
#3483=CARTESIAN_POINT('',(8.55000000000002,3.35,0.));
#3484=LINE('',#3483,#3482);
#3485=CARTESIAN_POINT('',(8.55000000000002,3.35,-0.65));
#3486=VERTEX_POINT('',#3485);
#3487=CARTESIAN_POINT('',(8.55000000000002,3.35,0.65));
#3488=VERTEX_POINT('',#3487);
#3489=EDGE_CURVE('E711',#3486,#3488,#3484,.F.);
#3490=ORIENTED_EDGE('',*,*,#3489,.F.);
#3491=CARTESIAN_POINT('',(8.65000000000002,3.35,-0.65));
#3492=DIRECTION('',(0.,0.,1.));
#3493=DIRECTION('',(1.,0.,0.));
#3494=AXIS2_PLACEMENT_3D('',#3491,#3492,#3493);
#3495=CIRCLE('',#3494,0.1);
#3496=EDGE_CURVE('E48',#3456,#3486,#3495,.T.);
#3497=ORIENTED_EDGE('',*,*,#3496,.F.);
#3498=ORIENTED_EDGE('',*,*,#3457,.F.);
#3499=CARTESIAN_POINT('',(8.65000000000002,3.35,0.65));
#3500=DIRECTION('',(0.,0.,-1.));
#3501=DIRECTION('',(-1.,0.,0.));
#3502=AXIS2_PLACEMENT_3D('',#3499,#3500,#3501);
#3503=CIRCLE('',#3502,0.1);
#3504=EDGE_CURVE('E90',#3488,#3448,#3503,.T.);
#3505=ORIENTED_EDGE('',*,*,#3504,.F.);
#3506=EDGE_LOOP('',(#3490,#3497,#3498,#3505));
#3507=FACE_BOUND('',#3506,.T.);
#3508=ADVANCED_FACE('F46',(#3507),#3480,.F.);
#3509=CARTESIAN_POINT('',(8.65000000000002,3.35,-0.65));
#3510=DIRECTION('',(0.,0.,1.));
#3511=DIRECTION('',(1.,0.,0.));
#3512=AXIS2_PLACEMENT_3D('',#3509,#3510,#3511);
#3513=SPHERICAL_SURFACE('',#3512,0.1);
#3514=ORIENTED_EDGE('',*,*,#3496,.T.);
#3515=CARTESIAN_POINT('',(8.65000000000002,3.35,-0.65));
#3516=DIRECTION('',(0.,1.,0.));
#3517=DIRECTION('',(0.,0.,1.));
#3518=AXIS2_PLACEMENT_3D('',#3515,#3516,#3517);
#3519=CIRCLE('',#3518,0.1);
#3520=CARTESIAN_POINT('',(8.65000000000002,3.35,-0.75));
#3521=VERTEX_POINT('',#3520);
#3522=EDGE_CURVE('E97',#3521,#3486,#3519,.T.);
#3523=ORIENTED_EDGE('',*,*,#3522,.F.);
#3524=CARTESIAN_POINT('',(8.65000000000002,3.35,-0.65));
#3525=DIRECTION('',(1.,0.,0.));
#3526=DIRECTION('',(0.,0.,-1.));
#3527=AXIS2_PLACEMENT_3D('',#3524,#3525,#3526);
#3528=CIRCLE('',#3527,0.1);
#3529=EDGE_CURVE('E703',#3456,#3521,#3528,.F.);
#3530=ORIENTED_EDGE('',*,*,#3529,.F.);
#3531=EDGE_LOOP('',(#3514,#3523,#3530));
#3532=FACE_BOUND('',#3531,.T.);
#3533=ADVANCED_FACE('F2244',(#3532),#3513,.F.);
#3534=CARTESIAN_POINT('',(8.65000000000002,3.35,0.65));
#3535=DIRECTION('',(0.,0.,1.));
#3536=DIRECTION('',(1.,0.,0.));
#3537=AXIS2_PLACEMENT_3D('',#3534,#3535,#3536);
#3538=SPHERICAL_SURFACE('',#3537,0.1);
#3539=CARTESIAN_POINT('',(8.65000000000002,3.35,0.65));
#3540=DIRECTION('',(0.,-1.,0.));
#3541=DIRECTION('',(0.,0.,-1.));
#3542=AXIS2_PLACEMENT_3D('',#3539,#3540,#3541);
#3543=CIRCLE('',#3542,0.1);
#3544=CARTESIAN_POINT('',(8.65000000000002,3.35,0.75));
#3545=VERTEX_POINT('',#3544);
#3546=EDGE_CURVE('E715',#3488,#3545,#3543,.F.);
#3547=ORIENTED_EDGE('',*,*,#3546,.F.);
#3548=ORIENTED_EDGE('',*,*,#3504,.T.);
#3549=CARTESIAN_POINT('',(8.65000000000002,3.35,0.65));
#3550=DIRECTION('',(1.,0.,0.));
#3551=DIRECTION('',(0.,0.,-1.));
#3552=AXIS2_PLACEMENT_3D('',#3549,#3550,#3551);
#3553=CIRCLE('',#3552,0.1);
#3554=EDGE_CURVE('E699',#3545,#3448,#3553,.F.);
#3555=ORIENTED_EDGE('',*,*,#3554,.F.);
#3556=EDGE_LOOP('',(#3547,#3548,#3555));
#3557=FACE_BOUND('',#3556,.T.);
#3558=ADVANCED_FACE('F2235',(#3557),#3538,.F.);
#3559=CARTESIAN_POINT('',(8.45000000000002,3.35,0.));
#3560=DIRECTION('',(0.,0.,-1.));
#3561=DIRECTION('',(-1.,0.,0.));
#3562=AXIS2_PLACEMENT_3D('',#3559,#3560,#3561);
#3563=CYLINDRICAL_SURFACE('',#3562,0.1);
#3564=CARTESIAN_POINT('',(8.45000000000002,3.35,0.65));
#3565=DIRECTION('',(0.,0.,1.));
#3566=DIRECTION('',(1.,0.,0.));
#3567=AXIS2_PLACEMENT_3D('',#3564,#3565,#3566);
#3568=CIRCLE('',#3567,0.1);
#3569=EDGE_CURVE('E695',#2897,#3488,#3568,.T.);
#3570=ORIENTED_EDGE('',*,*,#3569,.F.);
#3571=ORIENTED_EDGE('',*,*,#2955,.F.);
#3572=CARTESIAN_POINT('',(8.45000000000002,3.35,-0.65));
#3573=DIRECTION('',(0.,0.,-1.));
#3574=DIRECTION('',(-1.,0.,0.));
#3575=AXIS2_PLACEMENT_3D('',#3572,#3573,#3574);
#3576=CIRCLE('',#3575,0.1);
#3577=EDGE_CURVE('E708',#3486,#2948,#3576,.T.);
#3578=ORIENTED_EDGE('',*,*,#3577,.F.);
#3579=ORIENTED_EDGE('',*,*,#3489,.T.);
#3580=EDGE_LOOP('',(#3570,#3571,#3578,#3579));
#3581=FACE_BOUND('',#3580,.T.);
#3582=ADVANCED_FACE('F2227',(#3581),#3563,.T.);
#3583=CARTESIAN_POINT('',(8.65000000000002,3.35,-0.65));
#3584=DIRECTION('',(0.,1.,0.));
#3585=DIRECTION('',(0.,0.,1.));
#3586=AXIS2_PLACEMENT_3D('',#3583,#3584,#3585);
#3587=TOROIDAL_SURFACE('',#3586,0.2,0.1);
#3588=ORIENTED_EDGE('',*,*,#3577,.T.);
#3589=ORIENTED_EDGE('',*,*,#2949,.T.);
#3590=CARTESIAN_POINT('',(8.65000000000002,3.35,-0.85));
#3591=DIRECTION('',(-1.,0.,0.));
#3592=DIRECTION('',(0.,0.,1.));
#3593=AXIS2_PLACEMENT_3D('',#3590,#3591,#3592);
#3594=CIRCLE('',#3593,0.1);
#3595=EDGE_CURVE('E691',#3521,#2939,#3594,.F.);
#3596=ORIENTED_EDGE('',*,*,#3595,.F.);
#3597=ORIENTED_EDGE('',*,*,#3522,.T.);
#3598=EDGE_LOOP('',(#3588,#3589,#3596,#3597));
#3599=FACE_BOUND('',#3598,.T.);
#3600=ADVANCED_FACE('F2219',(#3599),#3587,.T.);
#3601=CARTESIAN_POINT('',(0.,3.35,-0.65));
#3602=DIRECTION('',(1.,0.,0.));
#3603=DIRECTION('',(0.,0.,-1.));
#3604=AXIS2_PLACEMENT_3D('',#3601,#3602,#3603);
#3605=CYLINDRICAL_SURFACE('',#3604,0.1);
#3606=ORIENTED_EDGE('',*,*,#3465,.F.);
#3607=ORIENTED_EDGE('',*,*,#3529,.T.);
#3608=DIRECTION('',(1.,0.,0.));
#3609=VECTOR('',#3608,1.);
#3610=CARTESIAN_POINT('',(0.,3.35,-0.75));
#3611=LINE('',#3610,#3609);
#3612=CARTESIAN_POINT('',(9.05000000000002,3.35,-0.75));
#3613=VERTEX_POINT('',#3612);
#3614=EDGE_CURVE('E627',#3613,#3521,#3611,.F.);
#3615=ORIENTED_EDGE('',*,*,#3614,.F.);
#3616=CARTESIAN_POINT('',(9.05000000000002,3.35,-0.65));
#3617=DIRECTION('',(-1.,0.,0.));
#3618=DIRECTION('',(0.,0.,1.));
#3619=AXIS2_PLACEMENT_3D('',#3616,#3617,#3618);
#3620=CIRCLE('',#3619,0.1);
#3621=EDGE_CURVE('E623',#3464,#3613,#3620,.T.);
#3622=ORIENTED_EDGE('',*,*,#3621,.F.);
#3623=EDGE_LOOP('',(#3606,#3607,#3615,#3622));
#3624=FACE_BOUND('',#3623,.T.);
#3625=ADVANCED_FACE('F625',(#3624),#3605,.F.);
#3626=CARTESIAN_POINT('',(0.,3.35,0.649999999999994));
#3627=DIRECTION('',(-1.,0.,0.));
#3628=DIRECTION('',(0.,0.,1.));
#3629=AXIS2_PLACEMENT_3D('',#3626,#3627,#3628);
#3630=CYLINDRICAL_SURFACE('',#3629,0.1);
#3631=ORIENTED_EDGE('',*,*,#3554,.T.);
#3632=ORIENTED_EDGE('',*,*,#3449,.F.);
#3633=CARTESIAN_POINT('',(9.05000000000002,3.35,0.65));
#3634=DIRECTION('',(-1.,0.,0.));
#3635=DIRECTION('',(0.,0.,1.));
#3636=AXIS2_PLACEMENT_3D('',#3633,#3634,#3635);
#3637=CIRCLE('',#3636,0.1);
#3638=CARTESIAN_POINT('',(9.05000000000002,3.35,0.75));
#3639=VERTEX_POINT('',#3638);
#3640=EDGE_CURVE('E631',#3639,#3446,#3637,.T.);
#3641=ORIENTED_EDGE('',*,*,#3640,.F.);
#3642=DIRECTION('',(-1.,0.,0.));
#3643=VECTOR('',#3642,1.);
#3644=CARTESIAN_POINT('',(0.,3.35,0.749999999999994));
#3645=LINE('',#3644,#3643);
#3646=EDGE_CURVE('E678',#3545,#3639,#3645,.F.);
#3647=ORIENTED_EDGE('',*,*,#3646,.F.);
#3648=EDGE_LOOP('',(#3631,#3632,#3641,#3647));
#3649=FACE_BOUND('',#3648,.T.);
#3650=ADVANCED_FACE('F2202',(#3649),#3630,.F.);
#3651=CARTESIAN_POINT('',(8.65000000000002,3.35,0.65));
#3652=DIRECTION('',(0.,1.,0.));
#3653=DIRECTION('',(0.,0.,1.));
#3654=AXIS2_PLACEMENT_3D('',#3651,#3652,#3653);
#3655=TOROIDAL_SURFACE('',#3654,0.2,0.1);
#3656=ORIENTED_EDGE('',*,*,#3569,.T.);
#3657=ORIENTED_EDGE('',*,*,#3546,.T.);
#3658=CARTESIAN_POINT('',(8.65000000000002,3.35,0.85));
#3659=DIRECTION('',(-1.,0.,0.));
#3660=DIRECTION('',(0.,0.,1.));
#3661=AXIS2_PLACEMENT_3D('',#3658,#3659,#3660);
#3662=CIRCLE('',#3661,0.1);
#3663=EDGE_CURVE('E674',#2895,#3545,#3662,.F.);
#3664=ORIENTED_EDGE('',*,*,#3663,.F.);
#3665=ORIENTED_EDGE('',*,*,#2898,.T.);
#3666=EDGE_LOOP('',(#3656,#3657,#3664,#3665));
#3667=FACE_BOUND('',#3666,.T.);
#3668=ADVANCED_FACE('F2194',(#3667),#3655,.T.);
#3669=CARTESIAN_POINT('',(0.,3.35,-0.85));
#3670=DIRECTION('',(1.,0.,0.));
#3671=DIRECTION('',(0.,0.,-1.));
#3672=AXIS2_PLACEMENT_3D('',#3669,#3670,#3671);
#3673=CYLINDRICAL_SURFACE('',#3672,0.1);
#3674=CARTESIAN_POINT('',(9.05000000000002,3.35,-0.85));
#3675=DIRECTION('',(1.,0.,0.));
#3676=DIRECTION('',(0.,0.,-1.));
#3677=AXIS2_PLACEMENT_3D('',#3674,#3675,#3676);
#3678=CIRCLE('',#3677,0.1);
#3679=EDGE_CURVE('E670',#3613,#2931,#3678,.T.);
#3680=ORIENTED_EDGE('',*,*,#3679,.F.);
#3681=ORIENTED_EDGE('',*,*,#3614,.T.);
#3682=ORIENTED_EDGE('',*,*,#3595,.T.);
#3683=ORIENTED_EDGE('',*,*,#2940,.F.);
#3684=EDGE_LOOP('',(#3680,#3681,#3682,#3683));
#3685=FACE_BOUND('',#3684,.T.);
#3686=ADVANCED_FACE('F1781',(#3685),#3673,.T.);
#3687=CARTESIAN_POINT('',(9.05000000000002,3.35,-0.65));
#3688=DIRECTION('',(0.,0.,1.));
#3689=DIRECTION('',(1.,0.,0.));
#3690=AXIS2_PLACEMENT_3D('',#3687,#3688,#3689);
#3691=SPHERICAL_SURFACE('',#3690,0.1);
#3692=ORIENTED_EDGE('',*,*,#3621,.T.);
#3693=CARTESIAN_POINT('',(9.05000000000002,3.35,-0.65));
#3694=DIRECTION('',(0.,1.,0.));
#3695=DIRECTION('',(0.,0.,1.));
#3696=AXIS2_PLACEMENT_3D('',#3693,#3694,#3695);
#3697=CIRCLE('',#3696,0.1);
#3698=CARTESIAN_POINT('',(9.15000000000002,3.35,-0.65));
#3699=VERTEX_POINT('',#3698);
#3700=EDGE_CURVE('E636',#3699,#3613,#3697,.T.);
#3701=ORIENTED_EDGE('',*,*,#3700,.F.);
#3702=CARTESIAN_POINT('',(9.05000000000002,3.35,-0.65));
#3703=DIRECTION('',(0.,0.,1.));
#3704=DIRECTION('',(1.,0.,0.));
#3705=AXIS2_PLACEMENT_3D('',#3702,#3703,#3704);
#3706=CIRCLE('',#3705,0.1);
#3707=EDGE_CURVE('E634',#3464,#3699,#3706,.F.);
#3708=ORIENTED_EDGE('',*,*,#3707,.F.);
#3709=EDGE_LOOP('',(#3692,#3701,#3708));
#3710=FACE_BOUND('',#3709,.T.);
#3711=ADVANCED_FACE('F635',(#3710),#3691,.F.);
#3712=CARTESIAN_POINT('',(9.05000000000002,3.35,0.65));
#3713=DIRECTION('',(0.,0.,1.));
#3714=DIRECTION('',(1.,0.,0.));
#3715=AXIS2_PLACEMENT_3D('',#3712,#3713,#3714);
#3716=SPHERICAL_SURFACE('',#3715,0.1);
#3717=CARTESIAN_POINT('',(9.05000000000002,3.35,0.65));
#3718=DIRECTION('',(0.,-1.,0.));
#3719=DIRECTION('',(0.,0.,-1.));
#3720=AXIS2_PLACEMENT_3D('',#3717,#3718,#3719);
#3721=CIRCLE('',#3720,0.1);
#3722=CARTESIAN_POINT('',(9.15000000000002,3.35,0.65));
#3723=VERTEX_POINT('',#3722);
#3724=EDGE_CURVE('E682',#3639,#3723,#3721,.F.);
#3725=ORIENTED_EDGE('',*,*,#3724,.F.);
#3726=ORIENTED_EDGE('',*,*,#3640,.T.);
#3727=CARTESIAN_POINT('',(9.05000000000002,3.35,0.65));
#3728=DIRECTION('',(0.,0.,-1.));
#3729=DIRECTION('',(-1.,0.,0.));
#3730=AXIS2_PLACEMENT_3D('',#3727,#3728,#3729);
#3731=CIRCLE('',#3730,0.1);
#3732=EDGE_CURVE('E641',#3723,#3446,#3731,.F.);
#3733=ORIENTED_EDGE('',*,*,#3732,.F.);
#3734=EDGE_LOOP('',(#3725,#3726,#3733));
#3735=FACE_BOUND('',#3734,.T.);
#3736=ADVANCED_FACE('F1790',(#3735),#3716,.F.);
#3737=CARTESIAN_POINT('',(0.,3.35,0.849999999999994));
#3738=DIRECTION('',(-1.,0.,0.));
#3739=DIRECTION('',(0.,0.,1.));
#3740=AXIS2_PLACEMENT_3D('',#3737,#3738,#3739);
#3741=CYLINDRICAL_SURFACE('',#3740,0.1);
#3742=ORIENTED_EDGE('',*,*,#3663,.T.);
#3743=ORIENTED_EDGE('',*,*,#3646,.T.);
#3744=CARTESIAN_POINT('',(9.05000000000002,3.35,0.85));
#3745=DIRECTION('',(1.,0.,0.));
#3746=DIRECTION('',(0.,0.,-1.));
#3747=AXIS2_PLACEMENT_3D('',#3744,#3745,#3746);
#3748=CIRCLE('',#3747,0.1);
#3749=EDGE_CURVE('E662',#2905,#3639,#3748,.T.);
#3750=ORIENTED_EDGE('',*,*,#3749,.F.);
#3751=ORIENTED_EDGE('',*,*,#2906,.F.);
#3752=EDGE_LOOP('',(#3742,#3743,#3750,#3751));
#3753=FACE_BOUND('',#3752,.T.);
#3754=ADVANCED_FACE('F1769',(#3753),#3741,.T.);
#3755=CARTESIAN_POINT('',(9.05000000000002,3.35,-0.65));
#3756=DIRECTION('',(0.,1.,0.));
#3757=DIRECTION('',(0.,0.,1.));
#3758=AXIS2_PLACEMENT_3D('',#3755,#3756,#3757);
#3759=TOROIDAL_SURFACE('',#3758,0.2,0.1);
#3760=ORIENTED_EDGE('',*,*,#3679,.T.);
#3761=ORIENTED_EDGE('',*,*,#2932,.T.);
#3762=CARTESIAN_POINT('',(9.25000000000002,3.35,-0.65));
#3763=DIRECTION('',(0.,0.,-1.));
#3764=DIRECTION('',(-1.,0.,0.));
#3765=AXIS2_PLACEMENT_3D('',#3762,#3763,#3764);
#3766=CIRCLE('',#3765,0.1);
#3767=EDGE_CURVE('E659',#3699,#2922,#3766,.F.);
#3768=ORIENTED_EDGE('',*,*,#3767,.F.);
#3769=ORIENTED_EDGE('',*,*,#3700,.T.);
#3770=EDGE_LOOP('',(#3760,#3761,#3768,#3769));
#3771=FACE_BOUND('',#3770,.T.);
#3772=ADVANCED_FACE('F1782',(#3771),#3759,.T.);
#3773=CARTESIAN_POINT('',(9.05000000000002,3.35,0.));
#3774=DIRECTION('',(0.,0.,1.));
#3775=DIRECTION('',(1.,0.,0.));
#3776=AXIS2_PLACEMENT_3D('',#3773,#3774,#3775);
#3777=CYLINDRICAL_SURFACE('',#3776,0.1);
#3778=ORIENTED_EDGE('',*,*,#3471,.F.);
#3779=ORIENTED_EDGE('',*,*,#3707,.T.);
#3780=DIRECTION('',(0.,0.,1.));
#3781=VECTOR('',#3780,1.);
#3782=CARTESIAN_POINT('',(9.15000000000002,3.35,0.));
#3783=LINE('',#3782,#3781);
#3784=EDGE_CURVE('E655',#3723,#3699,#3783,.F.);
#3785=ORIENTED_EDGE('',*,*,#3784,.F.);
#3786=ORIENTED_EDGE('',*,*,#3732,.T.);
#3787=EDGE_LOOP('',(#3778,#3779,#3785,#3786));
#3788=FACE_BOUND('',#3787,.T.);
#3789=ADVANCED_FACE('F644',(#3788),#3777,.F.);
#3790=CARTESIAN_POINT('',(9.05000000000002,3.35,0.65));
#3791=DIRECTION('',(0.,1.,0.));
#3792=DIRECTION('',(0.,0.,1.));
#3793=AXIS2_PLACEMENT_3D('',#3790,#3791,#3792);
#3794=TOROIDAL_SURFACE('',#3793,0.2,0.1);
#3795=ORIENTED_EDGE('',*,*,#3749,.T.);
#3796=ORIENTED_EDGE('',*,*,#3724,.T.);
#3797=CARTESIAN_POINT('',(9.25000000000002,3.35,0.65));
#3798=DIRECTION('',(0.,0.,1.));
#3799=DIRECTION('',(1.,0.,0.));
#3800=AXIS2_PLACEMENT_3D('',#3797,#3798,#3799);
#3801=CIRCLE('',#3800,0.1);
#3802=EDGE_CURVE('E651',#2914,#3723,#3801,.F.);
#3803=ORIENTED_EDGE('',*,*,#3802,.F.);
#3804=ORIENTED_EDGE('',*,*,#2915,.T.);
#3805=EDGE_LOOP('',(#3795,#3796,#3803,#3804));
#3806=FACE_BOUND('',#3805,.T.);
#3807=ADVANCED_FACE('F1773',(#3806),#3794,.T.);
#3808=CARTESIAN_POINT('',(9.25000000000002,3.35,0.));
#3809=DIRECTION('',(0.,0.,1.));
#3810=DIRECTION('',(1.,0.,0.));
#3811=AXIS2_PLACEMENT_3D('',#3808,#3809,#3810);
#3812=CYLINDRICAL_SURFACE('',#3811,0.1);
#3813=ORIENTED_EDGE('',*,*,#3767,.T.);
#3814=ORIENTED_EDGE('',*,*,#2923,.F.);
#3815=ORIENTED_EDGE('',*,*,#3802,.T.);
#3816=ORIENTED_EDGE('',*,*,#3784,.T.);
#3817=EDGE_LOOP('',(#3813,#3814,#3815,#3816));
#3818=FACE_BOUND('',#3817,.T.);
#3819=ADVANCED_FACE('F1776',(#3818),#3812,.T.);
#3820=CLOSED_SHELL('',(#60,#240,#299,#339,#361,#378,#410,#428,#446,#458,#510,#528,#570,#612,
#654,#685,#710,#734,#1054,#1085,#1121,#1156,#1182,#1208,#1226,#1250,#1268,#1286,#1304,#1322,
#1340,#1352,#1386,#1409,#1434,#1452,#1478,#1495,#1529,#1552,#1577,#1595,#1621,#1638,#1672,#1695,
#1720,#1738,#1764,#1781,#1814,#1840,#1866,#1891,#1916,#1942,#1968,#1985,#2019,#2044,#2069,#2095,
#2121,#2138,#2156,#2173,#2191,#2208,#2220,#2238,#2255,#2273,#2290,#2302,#2320,#2337,#2355,#2372,
#2384,#2407,#2425,#2443,#2460,#2477,#2495,#2513,#2524,#2548,#2565,#2582,#2600,#2618,#2630,#2776,
#2798,#2815,#2832,#2849,#2866,#2883,#2970,#2982,#3029,#3076,#3106,#3132,#3144,#3170,#3200,#3212,
#3229,#3246,#3277,#3303,#3329,#3346,#3358,#3389,#3406,#3423,#3435,#3475,#3508,#3533,#3558,#3582,
#3600,#3625,#3650,#3668,#3686,#3711,#3736,#3754,#3772,#3789,#3807,#3819));
#3821=MANIFOLD_SOLID_BREP('B2',#3820);
#3822=ADVANCED_BREP_SHAPE_REPRESENTATION('',(#18,#3821),#14);
#3823=SHAPE_DEFINITION_REPRESENTATION(#9,#3822);
ENDSEC;
END-ISO-10303-21;
